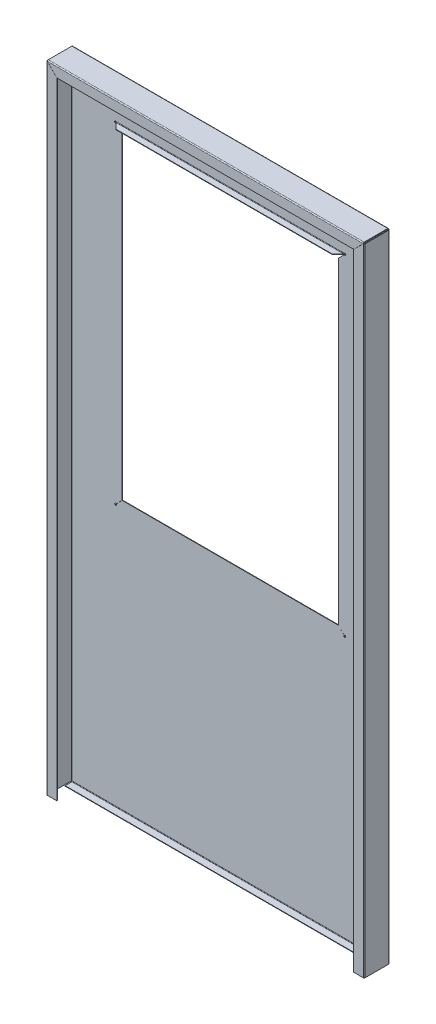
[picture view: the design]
ISO-10303-21;
HEADER;
FILE_DESCRIPTION(('STEP AP214'),'2;1');
FILE_NAME('part.step','',(''),(''),'','','');
FILE_SCHEMA(('AUTOMOTIVE_DESIGN { 1 0 10303 214 1 1 1 1 }'));
ENDSEC;
DATA;
#1=APPLICATION_CONTEXT('core data for automotive mechanical design processes');
#2=APPLICATION_PROTOCOL_DEFINITION('international standard','automotive_design',2000,#1);
#3=PRODUCT_CONTEXT('',#1,'mechanical');
#4=PRODUCT('Part','Part','',(#3));
#5=PRODUCT_RELATED_PRODUCT_CATEGORY('part','',(#4));
#6=PRODUCT_DEFINITION_FORMATION('','',#4);
#7=PRODUCT_DEFINITION_CONTEXT('part definition',#1,'design');
#8=PRODUCT_DEFINITION('design','',#6,#7);
#9=PRODUCT_DEFINITION_SHAPE('','',#8);
#10=(LENGTH_UNIT() NAMED_UNIT(*) SI_UNIT(.MILLI.,.METRE.));
#11=(NAMED_UNIT(*) PLANE_ANGLE_UNIT() SI_UNIT($,.RADIAN.));
#12=(NAMED_UNIT(*) SI_UNIT($,.STERADIAN.) SOLID_ANGLE_UNIT());
#13=UNCERTAINTY_MEASURE_WITH_UNIT(LENGTH_MEASURE(1.E-05),#10,'distance_accuracy_value','');
#14=(GEOMETRIC_REPRESENTATION_CONTEXT(3) GLOBAL_UNCERTAINTY_ASSIGNED_CONTEXT((#13)) GLOBAL_UNIT_ASSIGNED_CONTEXT((#10,
#11,#12)) REPRESENTATION_CONTEXT('',''));
#15=CARTESIAN_POINT('',(0.,0.,0.));
#16=DIRECTION('',(0.,0.,1.));
#17=DIRECTION('',(1.,0.,0.));
#18=AXIS2_PLACEMENT_3D('',#15,#16,#17);
#19=CARTESIAN_POINT('',(430.25,931.75,40.0010000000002));
#20=DIRECTION('',(0.,0.,-1.));
#21=DIRECTION('',(-1.,0.,0.));
#22=AXIS2_PLACEMENT_3D('',#19,#20,#21);
#23=CYLINDRICAL_SURFACE('',#22,1.50000000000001);
#24=CARTESIAN_POINT('',(430.25,931.75,0.750000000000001));
#25=DIRECTION('',(0.,0.,-1.));
#26=DIRECTION('',(-1.,0.,0.));
#27=AXIS2_PLACEMENT_3D('',#24,#25,#26);
#28=CIRCLE('',#27,1.50000000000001);
#29=CARTESIAN_POINT('',(429.32151366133,932.928097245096,0.750000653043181));
#30=VERTEX_POINT('',#29);
#31=CARTESIAN_POINT('',(429.225284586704,930.654573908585,0.750000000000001));
#32=VERTEX_POINT('',#31);
#33=EDGE_CURVE('E675',#30,#32,#28,.T.);
#34=ORIENTED_EDGE('',*,*,#33,.F.);
#35=CARTESIAN_POINT('',(429.32151366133,932.928097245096,6.5304318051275E-07));
#36=CARTESIAN_POINT('',(429.32151366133,932.928097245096,0.750000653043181));
#37=B_SPLINE_CURVE_WITH_KNOTS('',1,(#35,#36),.UNSPECIFIED.,.F.,.F.,(2,2),(0.,1.),.UNSPECIFIED.);
#38=CARTESIAN_POINT('',(429.32151366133,932.928097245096,0.));
#39=VERTEX_POINT('',#38);
#40=EDGE_CURVE('E13',#30,#39,#37,.F.);
#41=ORIENTED_EDGE('',*,*,#40,.T.);
#42=CARTESIAN_POINT('',(430.25,931.75,0.));
#43=DIRECTION('',(0.,0.,-1.));
#44=DIRECTION('',(-1.,0.,0.));
#45=AXIS2_PLACEMENT_3D('',#42,#43,#44);
#46=CIRCLE('',#45,1.50000000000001);
#47=CARTESIAN_POINT('',(429.225284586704,930.654573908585,0.));
#48=VERTEX_POINT('',#47);
#49=EDGE_CURVE('E711',#48,#39,#46,.F.);
#50=ORIENTED_EDGE('',*,*,#49,.F.);
#51=DIRECTION('',(0.,0.,-1.));
#52=VECTOR('',#51,1.);
#53=CARTESIAN_POINT('',(429.225284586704,930.654573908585,40.0010000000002));
#54=LINE('',#53,#52);
#55=EDGE_CURVE('E760',#32,#48,#54,.T.);
#56=ORIENTED_EDGE('',*,*,#55,.F.);
#57=EDGE_LOOP('',(#34,#41,#50,#56));
#58=FACE_BOUND('',#57,.T.);
#59=ADVANCED_FACE('F205',(#58),#23,.F.);
#60=CARTESIAN_POINT('',(0.,1000.,0.));
#61=DIRECTION('',(0.,0.,-1.));
#62=DIRECTION('',(-1.,0.,0.));
#63=AXIS2_PLACEMENT_3D('',#60,#61,#62);
#64=PLANE('',#63);
#65=DIRECTION('',(-1.,0.,0.));
#66=VECTOR('',#65,1.);
#67=CARTESIAN_POINT('',(0.,1000.,0.));
#68=LINE('',#67,#66);
#69=CARTESIAN_POINT('',(498.5,1000.,0.));
#70=VERTEX_POINT('',#69);
#71=CARTESIAN_POINT('',(1.5,1000.,0.));
#72=VERTEX_POINT('',#71);
#73=EDGE_CURVE('E1350',#70,#72,#68,.T.);
#74=ORIENTED_EDGE('',*,*,#73,.F.);
#75=DIRECTION('',(0.,1.,0.));
#76=VECTOR('',#75,1.);
#77=CARTESIAN_POINT('',(498.5,1000.,0.));
#78=LINE('',#77,#76);
#79=CARTESIAN_POINT('',(498.5,0.,0.));
#80=VERTEX_POINT('',#79);
#81=EDGE_CURVE('E1420',#70,#80,#78,.F.);
#82=ORIENTED_EDGE('',*,*,#81,.T.);
#83=DIRECTION('',(1.,0.,0.));
#84=VECTOR('',#83,1.);
#85=CARTESIAN_POINT('',(0.,0.,0.));
#86=LINE('',#85,#84);
#87=CARTESIAN_POINT('',(1.5,0.,0.));
#88=VERTEX_POINT('',#87);
#89=EDGE_CURVE('E1353',#88,#80,#86,.T.);
#90=ORIENTED_EDGE('',*,*,#89,.F.);
#91=DIRECTION('',(0.,-1.,0.));
#92=VECTOR('',#91,1.);
#93=CARTESIAN_POINT('',(1.5,0.,0.));
#94=LINE('',#93,#92);
#95=EDGE_CURVE('E1366',#88,#72,#94,.F.);
#96=ORIENTED_EDGE('',*,*,#95,.T.);
#97=EDGE_LOOP('',(#74,#82,#90,#96));
#98=FACE_BOUND('',#97,.T.);
#99=ORIENTED_EDGE('',*,*,#49,.T.);
#100=DIRECTION('',(-1.,0.,0.));
#101=VECTOR('',#100,1.);
#102=CARTESIAN_POINT('',(0.,932.928097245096,0.));
#103=LINE('',#102,#101);
#104=CARTESIAN_POINT('',(70.67848633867,932.928097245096,6.5304318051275E-07));
#105=VERTEX_POINT('',#104);
#106=EDGE_CURVE('E216',#39,#105,#103,.T.);
#107=ORIENTED_EDGE('',*,*,#106,.T.);
#108=CARTESIAN_POINT('',(69.7499999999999,931.75,0.));
#109=DIRECTION('',(0.,0.,-1.));
#110=DIRECTION('',(-1.,0.,0.));
#111=AXIS2_PLACEMENT_3D('',#108,#109,#110);
#112=CIRCLE('',#111,1.50000000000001);
#113=CARTESIAN_POINT('',(70.7747154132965,930.654573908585,0.));
#114=VERTEX_POINT('',#113);
#115=EDGE_CURVE('E706',#114,#105,#112,.T.);
#116=ORIENTED_EDGE('',*,*,#115,.F.);
#117=DIRECTION('',(-0.707106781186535,0.70710678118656,0.));
#118=VECTOR('',#117,1.);
#119=CARTESIAN_POINT('',(-58.6487222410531,1060.07801156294,0.));
#120=LINE('',#119,#118);
#121=CARTESIAN_POINT('',(79.9999999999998,921.429289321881,0.));
#122=VERTEX_POINT('',#121);
#123=EDGE_CURVE('E232',#122,#114,#120,.T.);
#124=ORIENTED_EDGE('',*,*,#123,.F.);
#125=DIRECTION('',(0.,-1.,0.));
#126=VECTOR('',#125,1.);
#127=CARTESIAN_POINT('',(79.9999999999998,500.,0.));
#128=LINE('',#127,#126);
#129=CARTESIAN_POINT('',(79.9999999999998,421.570710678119,0.));
#130=VERTEX_POINT('',#129);
#131=EDGE_CURVE('E735',#122,#130,#128,.T.);
#132=ORIENTED_EDGE('',*,*,#131,.T.);
#133=DIRECTION('',(-0.707106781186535,-0.70710678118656,0.));
#134=VECTOR('',#133,1.);
#135=CARTESIAN_POINT('',(-230.148722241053,111.421988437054,0.));
#136=LINE('',#135,#134);
#137=CARTESIAN_POINT('',(70.7747154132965,412.345426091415,0.));
#138=VERTEX_POINT('',#137);
#139=EDGE_CURVE('E732',#130,#138,#136,.T.);
#140=ORIENTED_EDGE('',*,*,#139,.T.);
#141=CARTESIAN_POINT('',(69.7499999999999,411.25,0.));
#142=DIRECTION('',(0.,0.,-1.));
#143=DIRECTION('',(-1.,0.,0.));
#144=AXIS2_PLACEMENT_3D('',#141,#142,#143);
#145=CIRCLE('',#144,1.50000000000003);
#146=CARTESIAN_POINT('',(70.8454260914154,412.274715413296,0.));
#147=VERTEX_POINT('',#146);
#148=EDGE_CURVE('E729',#138,#147,#145,.F.);
#149=ORIENTED_EDGE('',*,*,#148,.T.);
#150=DIRECTION('',(-0.707106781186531,-0.707106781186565,0.));
#151=VECTOR('',#150,1.);
#152=CARTESIAN_POINT('',(-230.07801156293,111.351277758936,0.));
#153=LINE('',#152,#151);
#154=CARTESIAN_POINT('',(80.0707106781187,421.5,0.));
#155=VERTEX_POINT('',#154);
#156=EDGE_CURVE('E726',#155,#147,#153,.T.);
#157=ORIENTED_EDGE('',*,*,#156,.F.);
#158=DIRECTION('',(-1.,0.,0.));
#159=VECTOR('',#158,1.);
#160=CARTESIAN_POINT('',(-618.726733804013,421.5,0.));
#161=LINE('',#160,#159);
#162=CARTESIAN_POINT('',(419.929289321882,421.5,0.));
#163=VERTEX_POINT('',#162);
#164=EDGE_CURVE('E723',#163,#155,#161,.T.);
#165=ORIENTED_EDGE('',*,*,#164,.F.);
#166=DIRECTION('',(0.707106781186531,-0.707106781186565,0.));
#167=VECTOR('',#166,1.);
#168=CARTESIAN_POINT('',(-138.648722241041,980.078011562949,0.));
#169=LINE('',#168,#167);
#170=CARTESIAN_POINT('',(429.154573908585,412.274715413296,0.));
#171=VERTEX_POINT('',#170);
#172=EDGE_CURVE('E720',#163,#171,#169,.T.);
#173=ORIENTED_EDGE('',*,*,#172,.T.);
#174=CARTESIAN_POINT('',(430.25,411.25,0.));
#175=DIRECTION('',(0.,0.,-1.));
#176=DIRECTION('',(-1.,0.,0.));
#177=AXIS2_PLACEMENT_3D('',#174,#175,#176);
#178=CIRCLE('',#177,1.50000000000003);
#179=CARTESIAN_POINT('',(429.225284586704,412.345426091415,0.));
#180=VERTEX_POINT('',#179);
#181=EDGE_CURVE('E717',#180,#171,#178,.T.);
#182=ORIENTED_EDGE('',*,*,#181,.F.);
#183=DIRECTION('',(0.707106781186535,-0.70710678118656,0.));
#184=VECTOR('',#183,1.);
#185=CARTESIAN_POINT('',(-138.578011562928,980.148722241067,0.));
#186=LINE('',#185,#184);
#187=CARTESIAN_POINT('',(420.,421.570710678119,0.));
#188=VERTEX_POINT('',#187);
#189=EDGE_CURVE('E714',#188,#180,#186,.T.);
#190=ORIENTED_EDGE('',*,*,#189,.F.);
#191=DIRECTION('',(0.,-1.,0.));
#192=VECTOR('',#191,1.);
#193=CARTESIAN_POINT('',(420.,500.,0.));
#194=LINE('',#193,#192);
#195=CARTESIAN_POINT('',(420.,921.429289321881,0.));
#196=VERTEX_POINT('',#195);
#197=EDGE_CURVE('E710',#196,#188,#194,.T.);
#198=ORIENTED_EDGE('',*,*,#197,.F.);
#199=DIRECTION('',(0.707106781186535,0.70710678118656,0.));
#200=VECTOR('',#199,1.);
#201=CARTESIAN_POINT('',(-310.078011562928,191.351277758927,0.));
#202=LINE('',#201,#200);
#203=EDGE_CURVE('E707',#196,#48,#202,.T.);
#204=ORIENTED_EDGE('',*,*,#203,.T.);
#205=EDGE_LOOP('',(#99,#107,#116,#124,#132,#140,#149,#157,#165,#173,#182,#190,#198,#204));
#206=FACE_BOUND('',#205,.T.);
#207=ADVANCED_FACE('F207',(#98,#206),#64,.T.);
#208=CARTESIAN_POINT('',(0.,1000.,0.75));
#209=DIRECTION('',(0.,0.,-1.));
#210=DIRECTION('',(-1.,0.,0.));
#211=AXIS2_PLACEMENT_3D('',#208,#209,#210);
#212=PLANE('',#211);
#213=DIRECTION('',(-1.,0.,0.));
#214=VECTOR('',#213,1.);
#215=CARTESIAN_POINT('',(0.,932.928097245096,0.75));
#216=LINE('',#215,#214);
#217=CARTESIAN_POINT('',(70.67848633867,932.928097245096,0.750000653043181));
#218=VERTEX_POINT('',#217);
#219=EDGE_CURVE('E1314',#30,#218,#216,.T.);
#220=ORIENTED_EDGE('',*,*,#219,.F.);
#221=ORIENTED_EDGE('',*,*,#33,.T.);
#222=DIRECTION('',(-0.707106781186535,-0.70710678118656,0.));
#223=VECTOR('',#222,1.);
#224=CARTESIAN_POINT('',(-310.078011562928,191.351277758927,0.750000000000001));
#225=LINE('',#224,#223);
#226=CARTESIAN_POINT('',(420.,921.429289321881,0.750000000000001));
#227=VERTEX_POINT('',#226);
#228=EDGE_CURVE('E666',#32,#227,#225,.T.);
#229=ORIENTED_EDGE('',*,*,#228,.T.);
#230=DIRECTION('',(0.,1.,0.));
#231=VECTOR('',#230,1.);
#232=CARTESIAN_POINT('',(420.,500.,0.750000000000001));
#233=LINE('',#232,#231);
#234=CARTESIAN_POINT('',(420.,421.570710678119,0.750000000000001));
#235=VERTEX_POINT('',#234);
#236=EDGE_CURVE('E674',#235,#227,#233,.T.);
#237=ORIENTED_EDGE('',*,*,#236,.F.);
#238=DIRECTION('',(-0.707106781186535,0.70710678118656,0.));
#239=VECTOR('',#238,1.);
#240=CARTESIAN_POINT('',(-138.578011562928,980.148722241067,0.750000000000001));
#241=LINE('',#240,#239);
#242=CARTESIAN_POINT('',(429.225284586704,412.345426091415,0.750000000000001));
#243=VERTEX_POINT('',#242);
#244=EDGE_CURVE('E678',#243,#235,#241,.T.);
#245=ORIENTED_EDGE('',*,*,#244,.F.);
#246=CARTESIAN_POINT('',(430.25,411.25,0.750000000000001));
#247=DIRECTION('',(0.,0.,-1.));
#248=DIRECTION('',(-1.,0.,0.));
#249=AXIS2_PLACEMENT_3D('',#246,#247,#248);
#250=CIRCLE('',#249,1.50000000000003);
#251=CARTESIAN_POINT('',(429.154573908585,412.274715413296,0.750000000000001));
#252=VERTEX_POINT('',#251);
#253=EDGE_CURVE('E681',#252,#243,#250,.F.);
#254=ORIENTED_EDGE('',*,*,#253,.F.);
#255=DIRECTION('',(-0.70710678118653,0.707106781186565,0.));
#256=VECTOR('',#255,1.);
#257=CARTESIAN_POINT('',(-138.648722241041,980.078011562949,0.750000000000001));
#258=LINE('',#257,#256);
#259=CARTESIAN_POINT('',(419.929289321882,421.5,0.750000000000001));
#260=VERTEX_POINT('',#259);
#261=EDGE_CURVE('E684',#252,#260,#258,.T.);
#262=ORIENTED_EDGE('',*,*,#261,.T.);
#263=DIRECTION('',(1.,0.,0.));
#264=VECTOR('',#263,1.);
#265=CARTESIAN_POINT('',(-618.726733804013,421.5,0.750000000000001));
#266=LINE('',#265,#264);
#267=CARTESIAN_POINT('',(80.0707106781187,421.5,0.750000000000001));
#268=VERTEX_POINT('',#267);
#269=EDGE_CURVE('E687',#268,#260,#266,.T.);
#270=ORIENTED_EDGE('',*,*,#269,.F.);
#271=DIRECTION('',(0.70710678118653,0.707106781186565,0.));
#272=VECTOR('',#271,1.);
#273=CARTESIAN_POINT('',(-230.07801156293,111.351277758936,0.750000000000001));
#274=LINE('',#273,#272);
#275=CARTESIAN_POINT('',(70.8454260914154,412.274715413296,0.750000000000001));
#276=VERTEX_POINT('',#275);
#277=EDGE_CURVE('E690',#276,#268,#274,.T.);
#278=ORIENTED_EDGE('',*,*,#277,.F.);
#279=CARTESIAN_POINT('',(69.7499999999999,411.25,0.750000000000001));
#280=DIRECTION('',(0.,0.,-1.));
#281=DIRECTION('',(-1.,0.,0.));
#282=AXIS2_PLACEMENT_3D('',#279,#280,#281);
#283=CIRCLE('',#282,1.50000000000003);
#284=CARTESIAN_POINT('',(70.7747154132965,412.345426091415,0.750000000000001));
#285=VERTEX_POINT('',#284);
#286=EDGE_CURVE('E693',#276,#285,#283,.T.);
#287=ORIENTED_EDGE('',*,*,#286,.T.);
#288=DIRECTION('',(0.707106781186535,0.70710678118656,0.));
#289=VECTOR('',#288,1.);
#290=CARTESIAN_POINT('',(-230.148722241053,111.421988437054,0.750000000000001));
#291=LINE('',#290,#289);
#292=CARTESIAN_POINT('',(79.9999999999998,421.570710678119,0.750000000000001));
#293=VERTEX_POINT('',#292);
#294=EDGE_CURVE('E696',#285,#293,#291,.T.);
#295=ORIENTED_EDGE('',*,*,#294,.T.);
#296=DIRECTION('',(0.,1.,0.));
#297=VECTOR('',#296,1.);
#298=CARTESIAN_POINT('',(79.9999999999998,500.,0.750000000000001));
#299=LINE('',#298,#297);
#300=CARTESIAN_POINT('',(79.9999999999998,921.429289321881,0.750000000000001));
#301=VERTEX_POINT('',#300);
#302=EDGE_CURVE('E699',#293,#301,#299,.T.);
#303=ORIENTED_EDGE('',*,*,#302,.T.);
#304=DIRECTION('',(0.707106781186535,-0.70710678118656,0.));
#305=VECTOR('',#304,1.);
#306=CARTESIAN_POINT('',(-58.6487222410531,1060.07801156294,0.750000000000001));
#307=LINE('',#306,#305);
#308=CARTESIAN_POINT('',(70.7747154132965,930.654573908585,0.750000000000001));
#309=VERTEX_POINT('',#308);
#310=EDGE_CURVE('E702',#309,#301,#307,.T.);
#311=ORIENTED_EDGE('',*,*,#310,.F.);
#312=CARTESIAN_POINT('',(69.7499999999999,931.75,0.750000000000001));
#313=DIRECTION('',(0.,0.,-1.));
#314=DIRECTION('',(-1.,0.,0.));
#315=AXIS2_PLACEMENT_3D('',#312,#313,#314);
#316=CIRCLE('',#315,1.50000000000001);
#317=EDGE_CURVE('E741',#218,#309,#316,.F.);
#318=ORIENTED_EDGE('',*,*,#317,.F.);
#319=EDGE_LOOP('',(#220,#221,#229,#237,#245,#254,#262,#270,#278,#287,#295,#303,#311,#318));
#320=FACE_BOUND('',#319,.T.);
#321=DIRECTION('',(0.,1.,0.));
#322=VECTOR('',#321,1.);
#323=CARTESIAN_POINT('',(498.5,1000.,0.750000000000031));
#324=LINE('',#323,#322);
#325=CARTESIAN_POINT('',(498.5,1000.,0.750000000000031));
#326=VERTEX_POINT('',#325);
#327=CARTESIAN_POINT('',(498.5,0.,0.750000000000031));
#328=VERTEX_POINT('',#327);
#329=EDGE_CURVE('E1428',#326,#328,#324,.F.);
#330=ORIENTED_EDGE('',*,*,#329,.F.);
#331=DIRECTION('',(-1.,0.,0.));
#332=VECTOR('',#331,1.);
#333=CARTESIAN_POINT('',(0.,1000.,0.75));
#334=LINE('',#333,#332);
#335=CARTESIAN_POINT('',(1.5,1000.,0.75));
#336=VERTEX_POINT('',#335);
#337=EDGE_CURVE('E1321',#326,#336,#334,.T.);
#338=ORIENTED_EDGE('',*,*,#337,.T.);
#339=DIRECTION('',(0.,-1.,0.));
#340=VECTOR('',#339,1.);
#341=CARTESIAN_POINT('',(1.5,0.,0.75));
#342=LINE('',#341,#340);
#343=CARTESIAN_POINT('',(1.5,0.,0.75));
#344=VERTEX_POINT('',#343);
#345=EDGE_CURVE('E1374',#344,#336,#342,.F.);
#346=ORIENTED_EDGE('',*,*,#345,.F.);
#347=DIRECTION('',(1.,0.,0.));
#348=VECTOR('',#347,1.);
#349=CARTESIAN_POINT('',(0.,0.,0.75));
#350=LINE('',#349,#348);
#351=EDGE_CURVE('E1347',#344,#328,#350,.T.);
#352=ORIENTED_EDGE('',*,*,#351,.T.);
#353=EDGE_LOOP('',(#330,#338,#346,#352));
#354=FACE_BOUND('',#353,.T.);
#355=ADVANCED_FACE('F1106',(#320,#354),#212,.F.);
#356=CARTESIAN_POINT('',(1.5,1000.,1.5));
#357=DIRECTION('',(0.,1.,0.));
#358=DIRECTION('',(0.,0.,1.));
#359=AXIS2_PLACEMENT_3D('',#356,#357,#358);
#360=PLANE('',#359);
#361=DIRECTION('',(1.,0.,0.));
#362=VECTOR('',#361,1.);
#363=CARTESIAN_POINT('',(0.,1000.,1.49999999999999));
#364=LINE('',#363,#362);
#365=CARTESIAN_POINT('',(0.749999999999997,1000.,1.5));
#366=VERTEX_POINT('',#365);
#367=CARTESIAN_POINT('',(0.,1000.,1.49999999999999));
#368=VERTEX_POINT('',#367);
#369=EDGE_CURVE('E1379',#366,#368,#364,.F.);
#370=ORIENTED_EDGE('',*,*,#369,.F.);
#371=CARTESIAN_POINT('',(1.5,1000.,1.5));
#372=DIRECTION('',(0.,-1.,0.));
#373=DIRECTION('',(0.,0.,-1.));
#374=AXIS2_PLACEMENT_3D('',#371,#372,#373);
#375=CIRCLE('',#374,0.75);
#376=EDGE_CURVE('E1367',#336,#366,#375,.F.);
#377=ORIENTED_EDGE('',*,*,#376,.F.);
#378=DIRECTION('',(0.,0.,-1.));
#379=VECTOR('',#378,1.);
#380=CARTESIAN_POINT('',(1.5,1000.,0.75));
#381=LINE('',#380,#379);
#382=EDGE_CURVE('E1356',#336,#72,#381,.T.);
#383=ORIENTED_EDGE('',*,*,#382,.T.);
#384=CARTESIAN_POINT('',(1.5,1000.,1.5));
#385=DIRECTION('',(0.,-1.,0.));
#386=DIRECTION('',(0.,0.,-1.));
#387=AXIS2_PLACEMENT_3D('',#384,#385,#386);
#388=CIRCLE('',#387,1.5);
#389=EDGE_CURVE('E1360',#72,#368,#388,.F.);
#390=ORIENTED_EDGE('',*,*,#389,.T.);
#391=EDGE_LOOP('',(#370,#377,#383,#390));
#392=FACE_BOUND('',#391,.T.);
#393=ADVANCED_FACE('F1103',(#392),#360,.T.);
#394=CARTESIAN_POINT('',(1.5,0.,1.5));
#395=DIRECTION('',(0.,1.,0.));
#396=DIRECTION('',(0.,0.,1.));
#397=AXIS2_PLACEMENT_3D('',#394,#395,#396);
#398=PLANE('',#397);
#399=CARTESIAN_POINT('',(1.5,0.,1.5));
#400=DIRECTION('',(0.,-1.,0.));
#401=DIRECTION('',(0.,0.,-1.));
#402=AXIS2_PLACEMENT_3D('',#399,#400,#401);
#403=CIRCLE('',#402,0.75);
#404=CARTESIAN_POINT('',(0.749999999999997,0.,1.5));
#405=VERTEX_POINT('',#404);
#406=EDGE_CURVE('E1371',#405,#344,#403,.T.);
#407=ORIENTED_EDGE('',*,*,#406,.F.);
#408=DIRECTION('',(1.,0.,0.));
#409=VECTOR('',#408,1.);
#410=CARTESIAN_POINT('',(0.749999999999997,0.,1.5));
#411=LINE('',#410,#409);
#412=CARTESIAN_POINT('',(0.,0.,1.49999999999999));
#413=VERTEX_POINT('',#412);
#414=EDGE_CURVE('E1385',#405,#413,#411,.F.);
#415=ORIENTED_EDGE('',*,*,#414,.T.);
#416=CARTESIAN_POINT('',(1.5,0.,1.5));
#417=DIRECTION('',(0.,-1.,0.));
#418=DIRECTION('',(0.,0.,-1.));
#419=AXIS2_PLACEMENT_3D('',#416,#417,#418);
#420=CIRCLE('',#419,1.5);
#421=EDGE_CURVE('E1363',#413,#88,#420,.T.);
#422=ORIENTED_EDGE('',*,*,#421,.T.);
#423=DIRECTION('',(0.,0.,-1.));
#424=VECTOR('',#423,1.);
#425=CARTESIAN_POINT('',(1.5,0.,0.75));
#426=LINE('',#425,#424);
#427=EDGE_CURVE('E1357',#344,#88,#426,.T.);
#428=ORIENTED_EDGE('',*,*,#427,.F.);
#429=EDGE_LOOP('',(#407,#415,#422,#428));
#430=FACE_BOUND('',#429,.T.);
#431=ADVANCED_FACE('F1099',(#430),#398,.F.);
#432=CARTESIAN_POINT('',(1.5,0.,1.5));
#433=DIRECTION('',(0.,-1.,0.));
#434=DIRECTION('',(-1.,0.,0.));
#435=AXIS2_PLACEMENT_3D('',#432,#433,#434);
#436=CYLINDRICAL_SURFACE('',#435,1.5);
#437=ORIENTED_EDGE('',*,*,#95,.F.);
#438=ORIENTED_EDGE('',*,*,#421,.F.);
#439=DIRECTION('',(0.,-1.,0.));
#440=VECTOR('',#439,1.);
#441=CARTESIAN_POINT('',(0.,1000.,1.49999999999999));
#442=LINE('',#441,#440);
#443=EDGE_CURVE('E1388',#413,#368,#442,.F.);
#444=ORIENTED_EDGE('',*,*,#443,.T.);
#445=ORIENTED_EDGE('',*,*,#389,.F.);
#446=EDGE_LOOP('',(#437,#438,#444,#445));
#447=FACE_BOUND('',#446,.T.);
#448=ADVANCED_FACE('F1097',(#447),#436,.T.);
#449=CARTESIAN_POINT('',(1.5,0.,1.5));
#450=DIRECTION('',(0.,-1.,0.));
#451=DIRECTION('',(-1.,0.,0.));
#452=AXIS2_PLACEMENT_3D('',#449,#450,#451);
#453=CYLINDRICAL_SURFACE('',#452,0.75);
#454=ORIENTED_EDGE('',*,*,#345,.T.);
#455=ORIENTED_EDGE('',*,*,#376,.T.);
#456=DIRECTION('',(0.,-1.,0.));
#457=VECTOR('',#456,1.);
#458=CARTESIAN_POINT('',(0.749999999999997,1000.,1.5));
#459=LINE('',#458,#457);
#460=EDGE_CURVE('E1382',#366,#405,#459,.T.);
#461=ORIENTED_EDGE('',*,*,#460,.T.);
#462=ORIENTED_EDGE('',*,*,#406,.T.);
#463=EDGE_LOOP('',(#454,#455,#461,#462));
#464=FACE_BOUND('',#463,.T.);
#465=ADVANCED_FACE('F1093',(#464),#453,.F.);
#466=CARTESIAN_POINT('',(0.,1000.,0.749999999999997));
#467=DIRECTION('',(0.,-1.,0.));
#468=DIRECTION('',(0.,0.,-1.));
#469=AXIS2_PLACEMENT_3D('',#466,#467,#468);
#470=PLANE('',#469);
#471=ORIENTED_EDGE('',*,*,#369,.T.);
#472=DIRECTION('',(0.,0.,-1.));
#473=VECTOR('',#472,1.);
#474=CARTESIAN_POINT('',(-1.31838984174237E-13,1000.,38.5));
#475=LINE('',#474,#473);
#476=CARTESIAN_POINT('',(-1.31838984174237E-13,1000.,38.5));
#477=VERTEX_POINT('',#476);
#478=EDGE_CURVE('E1398',#477,#368,#475,.T.);
#479=ORIENTED_EDGE('',*,*,#478,.F.);
#480=DIRECTION('',(1.,0.,0.));
#481=VECTOR('',#480,1.);
#482=CARTESIAN_POINT('',(-1.31803496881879E-13,1000.,38.5));
#483=LINE('',#482,#481);
#484=CARTESIAN_POINT('',(0.749999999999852,1000.,38.5));
#485=VERTEX_POINT('',#484);
#486=EDGE_CURVE('E1407',#477,#485,#483,.T.);
#487=ORIENTED_EDGE('',*,*,#486,.T.);
#488=DIRECTION('',(0.,0.,1.));
#489=VECTOR('',#488,1.);
#490=CARTESIAN_POINT('',(0.75,1000.,0.75));
#491=LINE('',#490,#489);
#492=EDGE_CURVE('E1390',#485,#366,#491,.F.);
#493=ORIENTED_EDGE('',*,*,#492,.T.);
#494=EDGE_LOOP('',(#471,#479,#487,#493));
#495=FACE_BOUND('',#494,.T.);
#496=ADVANCED_FACE('F1089',(#495),#470,.F.);
#497=CARTESIAN_POINT('',(-1.31838984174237E-13,0.,38.5));
#498=DIRECTION('',(0.,1.,0.));
#499=DIRECTION('',(0.,0.,1.));
#500=AXIS2_PLACEMENT_3D('',#497,#498,#499);
#501=PLANE('',#500);
#502=ORIENTED_EDGE('',*,*,#414,.F.);
#503=DIRECTION('',(0.,0.,-1.));
#504=VECTOR('',#503,1.);
#505=CARTESIAN_POINT('',(0.749999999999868,0.,38.5));
#506=LINE('',#505,#504);
#507=CARTESIAN_POINT('',(0.749999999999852,0.,38.5));
#508=VERTEX_POINT('',#507);
#509=EDGE_CURVE('E1393',#405,#508,#506,.F.);
#510=ORIENTED_EDGE('',*,*,#509,.T.);
#511=DIRECTION('',(1.,0.,0.));
#512=VECTOR('',#511,1.);
#513=CARTESIAN_POINT('',(-1.31838984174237E-13,0.,38.5));
#514=LINE('',#513,#512);
#515=CARTESIAN_POINT('',(-1.47668335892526E-13,0.,38.5));
#516=VERTEX_POINT('',#515);
#517=EDGE_CURVE('E1375',#516,#508,#514,.T.);
#518=ORIENTED_EDGE('',*,*,#517,.F.);
#519=DIRECTION('',(0.,0.,1.));
#520=VECTOR('',#519,1.);
#521=CARTESIAN_POINT('',(-1.31838984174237E-13,0.,38.5));
#522=LINE('',#521,#520);
#523=EDGE_CURVE('E1401',#413,#516,#522,.T.);
#524=ORIENTED_EDGE('',*,*,#523,.F.);
#525=EDGE_LOOP('',(#502,#510,#518,#524));
#526=FACE_BOUND('',#525,.T.);
#527=ADVANCED_FACE('F1085',(#526),#501,.F.);
#528=CARTESIAN_POINT('',(-1.31838984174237E-13,1000.,38.5));
#529=DIRECTION('',(1.,0.,0.));
#530=DIRECTION('',(0.,0.,-1.));
#531=AXIS2_PLACEMENT_3D('',#528,#529,#530);
#532=PLANE('',#531);
#533=ORIENTED_EDGE('',*,*,#443,.F.);
#534=ORIENTED_EDGE('',*,*,#523,.T.);
#535=DIRECTION('',(0.,1.,0.));
#536=VECTOR('',#535,1.);
#537=CARTESIAN_POINT('',(-1.31838984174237E-13,1000.,38.5));
#538=LINE('',#537,#536);
#539=EDGE_CURVE('E1404',#516,#477,#538,.T.);
#540=ORIENTED_EDGE('',*,*,#539,.T.);
#541=ORIENTED_EDGE('',*,*,#478,.T.);
#542=EDGE_LOOP('',(#533,#534,#540,#541));
#543=FACE_BOUND('',#542,.T.);
#544=ADVANCED_FACE('F1081',(#543),#532,.F.);
#545=CARTESIAN_POINT('',(0.749999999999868,1000.,38.5));
#546=DIRECTION('',(1.,0.,0.));
#547=DIRECTION('',(0.,0.,-1.));
#548=AXIS2_PLACEMENT_3D('',#545,#546,#547);
#549=PLANE('',#548);
#550=ORIENTED_EDGE('',*,*,#509,.F.);
#551=ORIENTED_EDGE('',*,*,#460,.F.);
#552=ORIENTED_EDGE('',*,*,#492,.F.);
#553=DIRECTION('',(0.,-1.,0.));
#554=VECTOR('',#553,1.);
#555=CARTESIAN_POINT('',(0.749999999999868,1000.,38.5));
#556=LINE('',#555,#554);
#557=EDGE_CURVE('E1396',#508,#485,#556,.F.);
#558=ORIENTED_EDGE('',*,*,#557,.F.);
#559=EDGE_LOOP('',(#550,#551,#552,#558));
#560=FACE_BOUND('',#559,.T.);
#561=ADVANCED_FACE('F1074',(#560),#549,.T.);
#562=CARTESIAN_POINT('',(498.5,0.,1.5));
#563=DIRECTION('',(0.,-1.,0.));
#564=DIRECTION('',(0.,0.,-1.));
#565=AXIS2_PLACEMENT_3D('',#562,#563,#564);
#566=PLANE('',#565);
#567=DIRECTION('',(-1.,0.,0.));
#568=VECTOR('',#567,1.);
#569=CARTESIAN_POINT('',(500.,0.,1.5));
#570=LINE('',#569,#568);
#571=CARTESIAN_POINT('',(499.25,0.,1.5));
#572=VERTEX_POINT('',#571);
#573=CARTESIAN_POINT('',(500.,0.,1.5));
#574=VERTEX_POINT('',#573);
#575=EDGE_CURVE('E1433',#572,#574,#570,.F.);
#576=ORIENTED_EDGE('',*,*,#575,.F.);
#577=CARTESIAN_POINT('',(498.5,0.,1.5));
#578=DIRECTION('',(0.,1.,0.));
#579=DIRECTION('',(0.,0.,1.));
#580=AXIS2_PLACEMENT_3D('',#577,#578,#579);
#581=CIRCLE('',#580,0.749999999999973);
#582=EDGE_CURVE('E1421',#328,#572,#581,.F.);
#583=ORIENTED_EDGE('',*,*,#582,.F.);
#584=DIRECTION('',(0.,0.,-1.));
#585=VECTOR('',#584,1.);
#586=CARTESIAN_POINT('',(498.5,0.,0.750000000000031));
#587=LINE('',#586,#585);
#588=EDGE_CURVE('E1383',#328,#80,#587,.T.);
#589=ORIENTED_EDGE('',*,*,#588,.T.);
#590=CARTESIAN_POINT('',(498.5,0.,1.5));
#591=DIRECTION('',(0.,1.,0.));
#592=DIRECTION('',(0.,0.,1.));
#593=AXIS2_PLACEMENT_3D('',#590,#591,#592);
#594=CIRCLE('',#593,1.49999999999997);
#595=EDGE_CURVE('E1414',#80,#574,#594,.F.);
#596=ORIENTED_EDGE('',*,*,#595,.T.);
#597=EDGE_LOOP('',(#576,#583,#589,#596));
#598=FACE_BOUND('',#597,.T.);
#599=ADVANCED_FACE('F1071',(#598),#566,.T.);
#600=CARTESIAN_POINT('',(498.5,1000.,1.5));
#601=DIRECTION('',(0.,-1.,0.));
#602=DIRECTION('',(0.,0.,-1.));
#603=AXIS2_PLACEMENT_3D('',#600,#601,#602);
#604=PLANE('',#603);
#605=CARTESIAN_POINT('',(498.5,1000.,1.5));
#606=DIRECTION('',(0.,1.,0.));
#607=DIRECTION('',(0.,0.,1.));
#608=AXIS2_PLACEMENT_3D('',#605,#606,#607);
#609=CIRCLE('',#608,0.749999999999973);
#610=CARTESIAN_POINT('',(499.25,1000.,1.5));
#611=VERTEX_POINT('',#610);
#612=EDGE_CURVE('E1425',#611,#326,#609,.T.);
#613=ORIENTED_EDGE('',*,*,#612,.F.);
#614=DIRECTION('',(-1.,0.,0.));
#615=VECTOR('',#614,1.);
#616=CARTESIAN_POINT('',(499.25,1000.,1.5));
#617=LINE('',#616,#615);
#618=CARTESIAN_POINT('',(500.,1000.,1.5));
#619=VERTEX_POINT('',#618);
#620=EDGE_CURVE('E1439',#611,#619,#617,.F.);
#621=ORIENTED_EDGE('',*,*,#620,.T.);
#622=CARTESIAN_POINT('',(498.5,1000.,1.5));
#623=DIRECTION('',(0.,1.,0.));
#624=DIRECTION('',(0.,0.,1.));
#625=AXIS2_PLACEMENT_3D('',#622,#623,#624);
#626=CIRCLE('',#625,1.49999999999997);
#627=EDGE_CURVE('E1417',#619,#70,#626,.T.);
#628=ORIENTED_EDGE('',*,*,#627,.T.);
#629=DIRECTION('',(0.,0.,-1.));
#630=VECTOR('',#629,1.);
#631=CARTESIAN_POINT('',(498.5,1000.,0.750000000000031));
#632=LINE('',#631,#630);
#633=EDGE_CURVE('E1411',#326,#70,#632,.T.);
#634=ORIENTED_EDGE('',*,*,#633,.F.);
#635=EDGE_LOOP('',(#613,#621,#628,#634));
#636=FACE_BOUND('',#635,.T.);
#637=ADVANCED_FACE('F1067',(#636),#604,.F.);
#638=CARTESIAN_POINT('',(498.5,1000.,1.5));
#639=DIRECTION('',(0.,1.,0.));
#640=DIRECTION('',(1.,0.,0.));
#641=AXIS2_PLACEMENT_3D('',#638,#639,#640);
#642=CYLINDRICAL_SURFACE('',#641,1.49999999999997);
#643=ORIENTED_EDGE('',*,*,#81,.F.);
#644=ORIENTED_EDGE('',*,*,#627,.F.);
#645=DIRECTION('',(0.,1.,0.));
#646=VECTOR('',#645,1.);
#647=CARTESIAN_POINT('',(500.,0.,1.5));
#648=LINE('',#647,#646);
#649=EDGE_CURVE('E1442',#619,#574,#648,.F.);
#650=ORIENTED_EDGE('',*,*,#649,.T.);
#651=ORIENTED_EDGE('',*,*,#595,.F.);
#652=EDGE_LOOP('',(#643,#644,#650,#651));
#653=FACE_BOUND('',#652,.T.);
#654=ADVANCED_FACE('F1065',(#653),#642,.T.);
#655=CARTESIAN_POINT('',(498.5,1000.,1.5));
#656=DIRECTION('',(0.,1.,0.));
#657=DIRECTION('',(1.,0.,0.));
#658=AXIS2_PLACEMENT_3D('',#655,#656,#657);
#659=CYLINDRICAL_SURFACE('',#658,0.749999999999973);
#660=ORIENTED_EDGE('',*,*,#329,.T.);
#661=ORIENTED_EDGE('',*,*,#582,.T.);
#662=DIRECTION('',(0.,1.,0.));
#663=VECTOR('',#662,1.);
#664=CARTESIAN_POINT('',(499.25,0.,1.5));
#665=LINE('',#664,#663);
#666=EDGE_CURVE('E1436',#572,#611,#665,.T.);
#667=ORIENTED_EDGE('',*,*,#666,.T.);
#668=ORIENTED_EDGE('',*,*,#612,.T.);
#669=EDGE_LOOP('',(#660,#661,#667,#668));
#670=FACE_BOUND('',#669,.T.);
#671=ADVANCED_FACE('F1061',(#670),#659,.F.);
#672=CARTESIAN_POINT('',(500.,0.,0.749999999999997));
#673=DIRECTION('',(0.,1.,0.));
#674=DIRECTION('',(0.,0.,1.));
#675=AXIS2_PLACEMENT_3D('',#672,#673,#674);
#676=PLANE('',#675);
#677=ORIENTED_EDGE('',*,*,#575,.T.);
#678=DIRECTION('',(0.,0.,-1.));
#679=VECTOR('',#678,1.);
#680=CARTESIAN_POINT('',(500.,0.,38.5));
#681=LINE('',#680,#679);
#682=CARTESIAN_POINT('',(500.,0.,38.5));
#683=VERTEX_POINT('',#682);
#684=EDGE_CURVE('E1452',#683,#574,#681,.T.);
#685=ORIENTED_EDGE('',*,*,#684,.F.);
#686=DIRECTION('',(-1.,0.,0.));
#687=VECTOR('',#686,1.);
#688=CARTESIAN_POINT('',(500.,0.,38.5));
#689=LINE('',#688,#687);
#690=CARTESIAN_POINT('',(499.25,0.,38.5));
#691=VERTEX_POINT('',#690);
#692=EDGE_CURVE('E1461',#683,#691,#689,.T.);
#693=ORIENTED_EDGE('',*,*,#692,.T.);
#694=DIRECTION('',(0.,0.,1.));
#695=VECTOR('',#694,1.);
#696=CARTESIAN_POINT('',(499.25,0.,0.75));
#697=LINE('',#696,#695);
#698=EDGE_CURVE('E1444',#691,#572,#697,.F.);
#699=ORIENTED_EDGE('',*,*,#698,.T.);
#700=EDGE_LOOP('',(#677,#685,#693,#699));
#701=FACE_BOUND('',#700,.T.);
#702=ADVANCED_FACE('F1057',(#701),#676,.F.);
#703=CARTESIAN_POINT('',(500.,1000.,38.5));
#704=DIRECTION('',(0.,-1.,0.));
#705=DIRECTION('',(0.,0.,-1.));
#706=AXIS2_PLACEMENT_3D('',#703,#704,#705);
#707=PLANE('',#706);
#708=ORIENTED_EDGE('',*,*,#620,.F.);
#709=DIRECTION('',(0.,0.,-1.));
#710=VECTOR('',#709,1.);
#711=CARTESIAN_POINT('',(499.25,1000.,38.5));
#712=LINE('',#711,#710);
#713=CARTESIAN_POINT('',(499.25,1000.,38.5));
#714=VERTEX_POINT('',#713);
#715=EDGE_CURVE('E1447',#611,#714,#712,.F.);
#716=ORIENTED_EDGE('',*,*,#715,.T.);
#717=DIRECTION('',(-1.,0.,0.));
#718=VECTOR('',#717,1.);
#719=CARTESIAN_POINT('',(500.,1000.,38.5));
#720=LINE('',#719,#718);
#721=CARTESIAN_POINT('',(500.,1000.,38.5));
#722=VERTEX_POINT('',#721);
#723=EDGE_CURVE('E1429',#722,#714,#720,.T.);
#724=ORIENTED_EDGE('',*,*,#723,.F.);
#725=DIRECTION('',(0.,0.,1.));
#726=VECTOR('',#725,1.);
#727=CARTESIAN_POINT('',(500.,1000.,38.5));
#728=LINE('',#727,#726);
#729=EDGE_CURVE('E1455',#619,#722,#728,.T.);
#730=ORIENTED_EDGE('',*,*,#729,.F.);
#731=EDGE_LOOP('',(#708,#716,#724,#730));
#732=FACE_BOUND('',#731,.T.);
#733=ADVANCED_FACE('F1053',(#732),#707,.F.);
#734=CARTESIAN_POINT('',(500.,0.,38.5));
#735=DIRECTION('',(-1.,0.,0.));
#736=DIRECTION('',(0.,0.,1.));
#737=AXIS2_PLACEMENT_3D('',#734,#735,#736);
#738=PLANE('',#737);
#739=ORIENTED_EDGE('',*,*,#649,.F.);
#740=ORIENTED_EDGE('',*,*,#729,.T.);
#741=DIRECTION('',(0.,-1.,0.));
#742=VECTOR('',#741,1.);
#743=CARTESIAN_POINT('',(500.,0.,38.5));
#744=LINE('',#743,#742);
#745=EDGE_CURVE('E1458',#722,#683,#744,.T.);
#746=ORIENTED_EDGE('',*,*,#745,.T.);
#747=ORIENTED_EDGE('',*,*,#684,.T.);
#748=EDGE_LOOP('',(#739,#740,#746,#747));
#749=FACE_BOUND('',#748,.T.);
#750=ADVANCED_FACE('F1049',(#749),#738,.F.);
#751=CARTESIAN_POINT('',(499.25,0.,38.5));
#752=DIRECTION('',(-1.,0.,0.));
#753=DIRECTION('',(0.,0.,1.));
#754=AXIS2_PLACEMENT_3D('',#751,#752,#753);
#755=PLANE('',#754);
#756=ORIENTED_EDGE('',*,*,#715,.F.);
#757=ORIENTED_EDGE('',*,*,#666,.F.);
#758=ORIENTED_EDGE('',*,*,#698,.F.);
#759=DIRECTION('',(0.,1.,0.));
#760=VECTOR('',#759,1.);
#761=CARTESIAN_POINT('',(499.25,0.,38.5));
#762=LINE('',#761,#760);
#763=EDGE_CURVE('E1450',#714,#691,#762,.F.);
#764=ORIENTED_EDGE('',*,*,#763,.F.);
#765=EDGE_LOOP('',(#756,#757,#758,#764));
#766=FACE_BOUND('',#765,.T.);
#767=ADVANCED_FACE('F1042',(#766),#755,.T.);
#768=CARTESIAN_POINT('',(498.5,1000.,1.50000000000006));
#769=DIRECTION('',(1.,0.,0.));
#770=DIRECTION('',(0.,0.,-1.));
#771=AXIS2_PLACEMENT_3D('',#768,#769,#770);
#772=PLANE('',#771);
#773=DIRECTION('',(0.,1.,0.));
#774=VECTOR('',#773,1.);
#775=CARTESIAN_POINT('',(498.5,1001.5,1.50000000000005));
#776=LINE('',#775,#774);
#777=CARTESIAN_POINT('',(498.5,1000.75,1.50000000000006));
#778=VERTEX_POINT('',#777);
#779=CARTESIAN_POINT('',(498.5,1001.5,1.50000000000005));
#780=VERTEX_POINT('',#779);
#781=EDGE_CURVE('E1477',#778,#780,#776,.T.);
#782=ORIENTED_EDGE('',*,*,#781,.F.);
#783=CARTESIAN_POINT('',(498.5,1000.,1.50000000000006));
#784=DIRECTION('',(-1.,0.,0.));
#785=DIRECTION('',(0.,0.,1.));
#786=AXIS2_PLACEMENT_3D('',#783,#784,#785);
#787=CIRCLE('',#786,0.750000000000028);
#788=EDGE_CURVE('E1468',#326,#778,#787,.F.);
#789=ORIENTED_EDGE('',*,*,#788,.F.);
#790=ORIENTED_EDGE('',*,*,#633,.T.);
#791=CARTESIAN_POINT('',(498.5,1000.,1.50000000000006));
#792=DIRECTION('',(-1.,0.,0.));
#793=DIRECTION('',(0.,0.,1.));
#794=AXIS2_PLACEMENT_3D('',#791,#792,#793);
#795=CIRCLE('',#794,1.50000000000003);
#796=EDGE_CURVE('E1437',#70,#780,#795,.F.);
#797=ORIENTED_EDGE('',*,*,#796,.T.);
#798=EDGE_LOOP('',(#782,#789,#790,#797));
#799=FACE_BOUND('',#798,.T.);
#800=ADVANCED_FACE('F1039',(#799),#772,.T.);
#801=CARTESIAN_POINT('',(1.5,1000.,1.50000000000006));
#802=DIRECTION('',(1.,0.,0.));
#803=DIRECTION('',(0.,0.,-1.));
#804=AXIS2_PLACEMENT_3D('',#801,#802,#803);
#805=PLANE('',#804);
#806=CARTESIAN_POINT('',(1.5,1000.,1.50000000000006));
#807=DIRECTION('',(-1.,0.,0.));
#808=DIRECTION('',(0.,0.,1.));
#809=AXIS2_PLACEMENT_3D('',#806,#807,#808);
#810=CIRCLE('',#809,0.750000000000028);
#811=CARTESIAN_POINT('',(1.5,1000.75,1.50000000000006));
#812=VERTEX_POINT('',#811);
#813=EDGE_CURVE('E1471',#812,#336,#810,.T.);
#814=ORIENTED_EDGE('',*,*,#813,.F.);
#815=DIRECTION('',(0.,1.,0.));
#816=VECTOR('',#815,1.);
#817=CARTESIAN_POINT('',(1.5,1000.75,1.50000000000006));
#818=LINE('',#817,#816);
#819=CARTESIAN_POINT('',(1.5,1001.5,1.50000000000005));
#820=VERTEX_POINT('',#819);
#821=EDGE_CURVE('E1483',#812,#820,#818,.T.);
#822=ORIENTED_EDGE('',*,*,#821,.T.);
#823=CARTESIAN_POINT('',(1.5,1000.,1.50000000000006));
#824=DIRECTION('',(-1.,0.,0.));
#825=DIRECTION('',(0.,0.,1.));
#826=AXIS2_PLACEMENT_3D('',#823,#824,#825);
#827=CIRCLE('',#826,1.50000000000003);
#828=EDGE_CURVE('E1465',#820,#72,#827,.T.);
#829=ORIENTED_EDGE('',*,*,#828,.T.);
#830=ORIENTED_EDGE('',*,*,#382,.F.);
#831=EDGE_LOOP('',(#814,#822,#829,#830));
#832=FACE_BOUND('',#831,.T.);
#833=ADVANCED_FACE('F1035',(#832),#805,.F.);
#834=CARTESIAN_POINT('',(1.49999999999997,1000.,1.50000000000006));
#835=DIRECTION('',(-1.,0.,0.));
#836=DIRECTION('',(0.,1.,0.));
#837=AXIS2_PLACEMENT_3D('',#834,#835,#836);
#838=CYLINDRICAL_SURFACE('',#837,1.50000000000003);
#839=ORIENTED_EDGE('',*,*,#73,.T.);
#840=ORIENTED_EDGE('',*,*,#828,.F.);
#841=DIRECTION('',(-1.,0.,0.));
#842=VECTOR('',#841,1.);
#843=CARTESIAN_POINT('',(1.5,1001.5,1.50000000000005));
#844=LINE('',#843,#842);
#845=EDGE_CURVE('E1486',#780,#820,#844,.T.);
#846=ORIENTED_EDGE('',*,*,#845,.F.);
#847=ORIENTED_EDGE('',*,*,#796,.F.);
#848=EDGE_LOOP('',(#839,#840,#846,#847));
#849=FACE_BOUND('',#848,.T.);
#850=ADVANCED_FACE('F1033',(#849),#838,.T.);
#851=CARTESIAN_POINT('',(1.49999999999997,1000.,1.50000000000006));
#852=DIRECTION('',(-1.,0.,0.));
#853=DIRECTION('',(0.,1.,0.));
#854=AXIS2_PLACEMENT_3D('',#851,#852,#853);
#855=CYLINDRICAL_SURFACE('',#854,0.750000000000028);
#856=ORIENTED_EDGE('',*,*,#337,.F.);
#857=ORIENTED_EDGE('',*,*,#788,.T.);
#858=DIRECTION('',(1.,0.,0.));
#859=VECTOR('',#858,1.);
#860=CARTESIAN_POINT('',(498.5,1000.75,1.50000000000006));
#861=LINE('',#860,#859);
#862=EDGE_CURVE('E1480',#778,#812,#861,.F.);
#863=ORIENTED_EDGE('',*,*,#862,.T.);
#864=ORIENTED_EDGE('',*,*,#813,.T.);
#865=EDGE_LOOP('',(#856,#857,#863,#864));
#866=FACE_BOUND('',#865,.T.);
#867=ADVANCED_FACE('F1026',(#866),#855,.F.);
#868=CARTESIAN_POINT('',(1.5,1001.5,0.749999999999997));
#869=DIRECTION('',(-1.,0.,0.));
#870=DIRECTION('',(0.,0.,1.));
#871=AXIS2_PLACEMENT_3D('',#868,#869,#870);
#872=PLANE('',#871);
#873=DIRECTION('',(0.,0.,-1.));
#874=VECTOR('',#873,1.);
#875=CARTESIAN_POINT('',(1.5,1001.5,0.749999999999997));
#876=LINE('',#875,#874);
#877=CARTESIAN_POINT('',(1.49999999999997,1001.5,38.5));
#878=VERTEX_POINT('',#877);
#879=EDGE_CURVE('E1501',#878,#820,#876,.T.);
#880=ORIENTED_EDGE('',*,*,#879,.T.);
#881=ORIENTED_EDGE('',*,*,#821,.F.);
#882=DIRECTION('',(0.,0.,1.));
#883=VECTOR('',#882,1.);
#884=CARTESIAN_POINT('',(1.5,1000.75,0.75));
#885=LINE('',#884,#883);
#886=CARTESIAN_POINT('',(1.5,1000.75,38.5));
#887=VERTEX_POINT('',#886);
#888=EDGE_CURVE('E1493',#887,#812,#885,.F.);
#889=ORIENTED_EDGE('',*,*,#888,.F.);
#890=DIRECTION('',(0.,-1.,0.));
#891=VECTOR('',#890,1.);
#892=CARTESIAN_POINT('',(1.5,1001.5,38.5));
#893=LINE('',#892,#891);
#894=EDGE_CURVE('E1474',#878,#887,#893,.T.);
#895=ORIENTED_EDGE('',*,*,#894,.F.);
#896=EDGE_LOOP('',(#880,#881,#889,#895));
#897=FACE_BOUND('',#896,.T.);
#898=ADVANCED_FACE('F1023',(#897),#872,.T.);
#899=CARTESIAN_POINT('',(498.5,1001.5,38.5));
#900=DIRECTION('',(1.,0.,0.));
#901=DIRECTION('',(0.,1.,0.));
#902=AXIS2_PLACEMENT_3D('',#899,#900,#901);
#903=PLANE('',#902);
#904=DIRECTION('',(0.,0.,-1.));
#905=VECTOR('',#904,1.);
#906=CARTESIAN_POINT('',(498.5,1000.75,0.75));
#907=LINE('',#906,#905);
#908=CARTESIAN_POINT('',(498.5,1000.75,38.5));
#909=VERTEX_POINT('',#908);
#910=EDGE_CURVE('E1489',#778,#909,#907,.F.);
#911=ORIENTED_EDGE('',*,*,#910,.F.);
#912=ORIENTED_EDGE('',*,*,#781,.T.);
#913=DIRECTION('',(0.,0.,1.));
#914=VECTOR('',#913,1.);
#915=CARTESIAN_POINT('',(498.5,1001.5,38.5));
#916=LINE('',#915,#914);
#917=CARTESIAN_POINT('',(498.5,1001.5,38.5));
#918=VERTEX_POINT('',#917);
#919=EDGE_CURVE('E1496',#780,#918,#916,.T.);
#920=ORIENTED_EDGE('',*,*,#919,.T.);
#921=DIRECTION('',(0.,-1.,0.));
#922=VECTOR('',#921,1.);
#923=CARTESIAN_POINT('',(498.5,1001.5,38.5));
#924=LINE('',#923,#922);
#925=EDGE_CURVE('E1504',#918,#909,#924,.T.);
#926=ORIENTED_EDGE('',*,*,#925,.T.);
#927=EDGE_LOOP('',(#911,#912,#920,#926));
#928=FACE_BOUND('',#927,.T.);
#929=ADVANCED_FACE('F1021',(#928),#903,.T.);
#930=CARTESIAN_POINT('',(1.5,1001.5,0.749999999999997));
#931=DIRECTION('',(0.,1.,0.));
#932=DIRECTION('',(0.,0.,1.));
#933=AXIS2_PLACEMENT_3D('',#930,#931,#932);
#934=PLANE('',#933);
#935=ORIENTED_EDGE('',*,*,#919,.F.);
#936=ORIENTED_EDGE('',*,*,#845,.T.);
#937=ORIENTED_EDGE('',*,*,#879,.F.);
#938=DIRECTION('',(-1.,0.,0.));
#939=VECTOR('',#938,1.);
#940=CARTESIAN_POINT('',(1.5,1001.5,38.5));
#941=LINE('',#940,#939);
#942=EDGE_CURVE('E1498',#918,#878,#941,.T.);
#943=ORIENTED_EDGE('',*,*,#942,.F.);
#944=EDGE_LOOP('',(#935,#936,#937,#943));
#945=FACE_BOUND('',#944,.T.);
#946=ADVANCED_FACE('F1017',(#945),#934,.T.);
#947=CARTESIAN_POINT('',(1.5,1000.75,0.75));
#948=DIRECTION('',(0.,1.,0.));
#949=DIRECTION('',(0.,0.,1.));
#950=AXIS2_PLACEMENT_3D('',#947,#948,#949);
#951=PLANE('',#950);
#952=ORIENTED_EDGE('',*,*,#862,.F.);
#953=ORIENTED_EDGE('',*,*,#910,.T.);
#954=DIRECTION('',(1.,0.,0.));
#955=VECTOR('',#954,1.);
#956=CARTESIAN_POINT('',(1.5,1000.75,38.5));
#957=LINE('',#956,#955);
#958=EDGE_CURVE('E1491',#909,#887,#957,.F.);
#959=ORIENTED_EDGE('',*,*,#958,.T.);
#960=ORIENTED_EDGE('',*,*,#888,.T.);
#961=EDGE_LOOP('',(#952,#953,#959,#960));
#962=FACE_BOUND('',#961,.T.);
#963=ADVANCED_FACE('F1010',(#962),#951,.F.);
#964=CARTESIAN_POINT('',(1.49999999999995,0.,1.50000000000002));
#965=DIRECTION('',(-1.,0.,0.));
#966=DIRECTION('',(0.,0.,1.));
#967=AXIS2_PLACEMENT_3D('',#964,#965,#966);
#968=PLANE('',#967);
#969=DIRECTION('',(0.,1.,0.));
#970=VECTOR('',#969,1.);
#971=CARTESIAN_POINT('',(1.5,-1.5,1.49999999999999));
#972=LINE('',#971,#970);
#973=CARTESIAN_POINT('',(1.49999999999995,-0.75,1.50000000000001));
#974=VERTEX_POINT('',#973);
#975=CARTESIAN_POINT('',(1.49999999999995,-1.5,1.50000000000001));
#976=VERTEX_POINT('',#975);
#977=EDGE_CURVE('E1521',#974,#976,#972,.F.);
#978=ORIENTED_EDGE('',*,*,#977,.F.);
#979=CARTESIAN_POINT('',(1.49999999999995,0.,1.50000000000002));
#980=DIRECTION('',(1.,0.,0.));
#981=DIRECTION('',(0.,0.,-1.));
#982=AXIS2_PLACEMENT_3D('',#979,#980,#981);
#983=CIRCLE('',#982,0.75);
#984=EDGE_CURVE('E1512',#344,#974,#983,.F.);
#985=ORIENTED_EDGE('',*,*,#984,.F.);
#986=ORIENTED_EDGE('',*,*,#427,.T.);
#987=CARTESIAN_POINT('',(1.49999999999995,0.,1.50000000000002));
#988=DIRECTION('',(1.,0.,0.));
#989=DIRECTION('',(0.,0.,-1.));
#990=AXIS2_PLACEMENT_3D('',#987,#988,#989);
#991=CIRCLE('',#990,1.5);
#992=EDGE_CURVE('E1481',#88,#976,#991,.F.);
#993=ORIENTED_EDGE('',*,*,#992,.T.);
#994=EDGE_LOOP('',(#978,#985,#986,#993));
#995=FACE_BOUND('',#994,.T.);
#996=ADVANCED_FACE('F1007',(#995),#968,.T.);
#997=CARTESIAN_POINT('',(498.5,0.,1.50000000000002));
#998=DIRECTION('',(-1.,0.,0.));
#999=DIRECTION('',(0.,0.,1.));
#1000=AXIS2_PLACEMENT_3D('',#997,#998,#999);
#1001=PLANE('',#1000);
#1002=CARTESIAN_POINT('',(498.5,0.,1.50000000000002));
#1003=DIRECTION('',(1.,0.,0.));
#1004=DIRECTION('',(0.,0.,-1.));
#1005=AXIS2_PLACEMENT_3D('',#1002,#1003,#1004);
#1006=CIRCLE('',#1005,0.75);
#1007=CARTESIAN_POINT('',(498.5,-0.75,1.50000000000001));
#1008=VERTEX_POINT('',#1007);
#1009=EDGE_CURVE('E1515',#1008,#328,#1006,.T.);
#1010=ORIENTED_EDGE('',*,*,#1009,.F.);
#1011=DIRECTION('',(0.,1.,0.));
#1012=VECTOR('',#1011,1.);
#1013=CARTESIAN_POINT('',(498.5,-0.75,1.50000000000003));
#1014=LINE('',#1013,#1012);
#1015=CARTESIAN_POINT('',(498.5,-1.5,1.50000000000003));
#1016=VERTEX_POINT('',#1015);
#1017=EDGE_CURVE('E1526',#1008,#1016,#1014,.F.);
#1018=ORIENTED_EDGE('',*,*,#1017,.T.);
#1019=CARTESIAN_POINT('',(498.5,0.,1.50000000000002));
#1020=DIRECTION('',(1.,0.,0.));
#1021=DIRECTION('',(0.,0.,-1.));
#1022=AXIS2_PLACEMENT_3D('',#1019,#1020,#1021);
#1023=CIRCLE('',#1022,1.5);
#1024=EDGE_CURVE('E1509',#1016,#80,#1023,.T.);
#1025=ORIENTED_EDGE('',*,*,#1024,.T.);
#1026=ORIENTED_EDGE('',*,*,#588,.F.);
#1027=EDGE_LOOP('',(#1010,#1018,#1025,#1026));
#1028=FACE_BOUND('',#1027,.T.);
#1029=ADVANCED_FACE('F1003',(#1028),#1001,.F.);
#1030=CARTESIAN_POINT('',(498.5,0.,1.50000000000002));
#1031=DIRECTION('',(1.,0.,0.));
#1032=DIRECTION('',(0.,-1.,0.));
#1033=AXIS2_PLACEMENT_3D('',#1030,#1031,#1032);
#1034=CYLINDRICAL_SURFACE('',#1033,1.5);
#1035=ORIENTED_EDGE('',*,*,#89,.T.);
#1036=ORIENTED_EDGE('',*,*,#1024,.F.);
#1037=DIRECTION('',(1.,0.,0.));
#1038=VECTOR('',#1037,1.);
#1039=CARTESIAN_POINT('',(1.5,-1.5,1.49999999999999));
#1040=LINE('',#1039,#1038);
#1041=EDGE_CURVE('E1529',#1016,#976,#1040,.F.);
#1042=ORIENTED_EDGE('',*,*,#1041,.T.);
#1043=ORIENTED_EDGE('',*,*,#992,.F.);
#1044=EDGE_LOOP('',(#1035,#1036,#1042,#1043));
#1045=FACE_BOUND('',#1044,.T.);
#1046=ADVANCED_FACE('F1001',(#1045),#1034,.T.);
#1047=CARTESIAN_POINT('',(498.5,0.,1.50000000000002));
#1048=DIRECTION('',(1.,0.,0.));
#1049=DIRECTION('',(0.,-1.,0.));
#1050=AXIS2_PLACEMENT_3D('',#1047,#1048,#1049);
#1051=CYLINDRICAL_SURFACE('',#1050,0.75);
#1052=ORIENTED_EDGE('',*,*,#351,.F.);
#1053=ORIENTED_EDGE('',*,*,#984,.T.);
#1054=DIRECTION('',(1.,0.,0.));
#1055=VECTOR('',#1054,1.);
#1056=CARTESIAN_POINT('',(1.5,-0.75,1.5));
#1057=LINE('',#1056,#1055);
#1058=EDGE_CURVE('E1524',#974,#1008,#1057,.T.);
#1059=ORIENTED_EDGE('',*,*,#1058,.T.);
#1060=ORIENTED_EDGE('',*,*,#1009,.T.);
#1061=EDGE_LOOP('',(#1052,#1053,#1059,#1060));
#1062=FACE_BOUND('',#1061,.T.);
#1063=ADVANCED_FACE('F997',(#1062),#1051,.F.);
#1064=CARTESIAN_POINT('',(1.5,-1.5,0.749999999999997));
#1065=DIRECTION('',(1.,0.,0.));
#1066=DIRECTION('',(0.,0.,-1.));
#1067=AXIS2_PLACEMENT_3D('',#1064,#1065,#1066);
#1068=PLANE('',#1067);
#1069=ORIENTED_EDGE('',*,*,#977,.T.);
#1070=DIRECTION('',(0.,0.,-1.));
#1071=VECTOR('',#1070,1.);
#1072=CARTESIAN_POINT('',(1.5,-1.5,0.749999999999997));
#1073=LINE('',#1072,#1071);
#1074=CARTESIAN_POINT('',(1.5,-1.50000000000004,12.));
#1075=VERTEX_POINT('',#1074);
#1076=EDGE_CURVE('E1538',#1075,#976,#1073,.T.);
#1077=ORIENTED_EDGE('',*,*,#1076,.F.);
#1078=DIRECTION('',(0.,1.,0.));
#1079=VECTOR('',#1078,1.);
#1080=CARTESIAN_POINT('',(1.5,-1.50000000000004,12.));
#1081=LINE('',#1080,#1079);
#1082=CARTESIAN_POINT('',(1.5,-0.750000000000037,12.));
#1083=VERTEX_POINT('',#1082);
#1084=EDGE_CURVE('E1545',#1075,#1083,#1081,.T.);
#1085=ORIENTED_EDGE('',*,*,#1084,.T.);
#1086=DIRECTION('',(0.,0.,1.));
#1087=VECTOR('',#1086,1.);
#1088=CARTESIAN_POINT('',(1.5,-0.749999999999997,0.75));
#1089=LINE('',#1088,#1087);
#1090=EDGE_CURVE('E1531',#1083,#974,#1089,.F.);
#1091=ORIENTED_EDGE('',*,*,#1090,.T.);
#1092=EDGE_LOOP('',(#1069,#1077,#1085,#1091));
#1093=FACE_BOUND('',#1092,.T.);
#1094=ADVANCED_FACE('F993',(#1093),#1068,.F.);
#1095=CARTESIAN_POINT('',(498.5,-1.50000000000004,12.));
#1096=DIRECTION('',(-1.,0.,0.));
#1097=DIRECTION('',(0.,-1.,0.));
#1098=AXIS2_PLACEMENT_3D('',#1095,#1096,#1097);
#1099=PLANE('',#1098);
#1100=ORIENTED_EDGE('',*,*,#1017,.F.);
#1101=DIRECTION('',(0.,0.,-1.));
#1102=VECTOR('',#1101,1.);
#1103=CARTESIAN_POINT('',(498.5,-0.750000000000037,12.));
#1104=LINE('',#1103,#1102);
#1105=CARTESIAN_POINT('',(498.5,-0.750000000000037,12.));
#1106=VERTEX_POINT('',#1105);
#1107=EDGE_CURVE('E1534',#1008,#1106,#1104,.F.);
#1108=ORIENTED_EDGE('',*,*,#1107,.T.);
#1109=DIRECTION('',(0.,1.,0.));
#1110=VECTOR('',#1109,1.);
#1111=CARTESIAN_POINT('',(498.5,-1.50000000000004,12.));
#1112=LINE('',#1111,#1110);
#1113=CARTESIAN_POINT('',(498.5,-1.50000000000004,12.));
#1114=VERTEX_POINT('',#1113);
#1115=EDGE_CURVE('E1518',#1114,#1106,#1112,.T.);
#1116=ORIENTED_EDGE('',*,*,#1115,.F.);
#1117=DIRECTION('',(0.,0.,1.));
#1118=VECTOR('',#1117,1.);
#1119=CARTESIAN_POINT('',(498.5,-1.5,0.749999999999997));
#1120=LINE('',#1119,#1118);
#1121=EDGE_CURVE('E1541',#1016,#1114,#1120,.T.);
#1122=ORIENTED_EDGE('',*,*,#1121,.F.);
#1123=EDGE_LOOP('',(#1100,#1108,#1116,#1122));
#1124=FACE_BOUND('',#1123,.T.);
#1125=ADVANCED_FACE('F986',(#1124),#1099,.F.);
#1126=CARTESIAN_POINT('',(1.5,-1.5,0.749999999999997));
#1127=DIRECTION('',(0.,1.,0.));
#1128=DIRECTION('',(0.,0.,1.));
#1129=AXIS2_PLACEMENT_3D('',#1126,#1127,#1128);
#1130=PLANE('',#1129);
#1131=ORIENTED_EDGE('',*,*,#1041,.F.);
#1132=ORIENTED_EDGE('',*,*,#1121,.T.);
#1133=DIRECTION('',(-1.,0.,0.));
#1134=VECTOR('',#1133,1.);
#1135=CARTESIAN_POINT('',(1.5,-1.50000000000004,12.));
#1136=LINE('',#1135,#1134);
#1137=EDGE_CURVE('E1543',#1114,#1075,#1136,.T.);
#1138=ORIENTED_EDGE('',*,*,#1137,.T.);
#1139=ORIENTED_EDGE('',*,*,#1076,.T.);
#1140=EDGE_LOOP('',(#1131,#1132,#1138,#1139));
#1141=FACE_BOUND('',#1140,.T.);
#1142=ADVANCED_FACE('F982',(#1141),#1130,.F.);
#1143=CARTESIAN_POINT('',(1.5,-0.749999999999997,0.75));
#1144=DIRECTION('',(0.,1.,0.));
#1145=DIRECTION('',(0.,0.,1.));
#1146=AXIS2_PLACEMENT_3D('',#1143,#1144,#1145);
#1147=PLANE('',#1146);
#1148=ORIENTED_EDGE('',*,*,#1107,.F.);
#1149=ORIENTED_EDGE('',*,*,#1058,.F.);
#1150=ORIENTED_EDGE('',*,*,#1090,.F.);
#1151=DIRECTION('',(1.,0.,0.));
#1152=VECTOR('',#1151,1.);
#1153=CARTESIAN_POINT('',(1.5,-0.750000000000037,12.));
#1154=LINE('',#1153,#1152);
#1155=EDGE_CURVE('E1536',#1106,#1083,#1154,.F.);
#1156=ORIENTED_EDGE('',*,*,#1155,.F.);
#1157=EDGE_LOOP('',(#1148,#1149,#1150,#1156));
#1158=FACE_BOUND('',#1157,.T.);
#1159=ADVANCED_FACE('F979',(#1158),#1147,.T.);
#1160=CARTESIAN_POINT('',(1.5,-1.50000000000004,12.));
#1161=DIRECTION('',(0.,0.,-1.));
#1162=DIRECTION('',(0.,1.,0.));
#1163=AXIS2_PLACEMENT_3D('',#1160,#1161,#1162);
#1164=PLANE('',#1163);
#1165=ORIENTED_EDGE('',*,*,#1155,.T.);
#1166=ORIENTED_EDGE('',*,*,#1084,.F.);
#1167=ORIENTED_EDGE('',*,*,#1137,.F.);
#1168=ORIENTED_EDGE('',*,*,#1115,.T.);
#1169=EDGE_LOOP('',(#1165,#1166,#1167,#1168));
#1170=FACE_BOUND('',#1169,.T.);
#1171=ADVANCED_FACE('F969',(#1170),#1164,.F.);
#1172=CARTESIAN_POINT('',(-0.00750000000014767,1000.,38.5));
#1173=CARTESIAN_POINT('',(-0.00750000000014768,999.994106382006,38.6973668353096));
#1174=CARTESIAN_POINT('',(0.0317361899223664,999.98821488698,38.8945849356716));
#1175=CARTESIAN_POINT('',(0.18276701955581,999.97642977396,39.2592056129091));
#1176=CARTESIAN_POINT('',(0.294502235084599,999.970537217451,39.4264291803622));
#1177=CARTESIAN_POINT('',(0.573570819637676,999.958752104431,39.7054977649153));
#1178=CARTESIAN_POINT('',(0.740794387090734,999.952859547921,39.8172329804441));
#1179=CARTESIAN_POINT('',(1.10541506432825,999.941074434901,39.9682638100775));
#1180=CARTESIAN_POINT('',(1.3026331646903,999.935182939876,40.0075));
#1181=CARTESIAN_POINT('',(1.49999999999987,999.929289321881,40.0075));
#1182=CARTESIAN_POINT('',(-1.47668335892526E-13,1000.,38.5));
#1183=CARTESIAN_POINT('',(-1.47678589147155E-13,999.994106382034,38.6963849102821));
#1184=CARTESIAN_POINT('',(0.0390409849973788,999.98821488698,38.8926218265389));
#1185=CARTESIAN_POINT('',(0.189320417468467,999.97642977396,39.2554284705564));
#1186=CARTESIAN_POINT('',(0.300499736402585,999.970537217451,39.4218200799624));
#1187=CARTESIAN_POINT('',(0.578179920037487,999.958752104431,39.6995002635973));
#1188=CARTESIAN_POINT('',(0.744571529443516,999.952859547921,39.8106795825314));
#1189=CARTESIAN_POINT('',(1.10737817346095,999.941074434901,39.9609590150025));
#1190=CARTESIAN_POINT('',(1.30361508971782,999.935182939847,40.));
#1191=CARTESIAN_POINT('',(1.49999999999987,999.929289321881,40.));
#1192=CARTESIAN_POINT('',(0.749999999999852,1000.,38.5));
#1193=CARTESIAN_POINT('',(0.749999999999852,999.994106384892,38.5981924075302));
#1194=CARTESIAN_POINT('',(0.769520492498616,999.98821488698,38.6963109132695));
#1195=CARTESIAN_POINT('',(0.844660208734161,999.97642977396,38.8777142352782));
#1196=CARTESIAN_POINT('',(0.90024986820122,999.97053721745,38.9609100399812));
#1197=CARTESIAN_POINT('',(1.03908996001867,999.958752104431,39.0997501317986));
#1198=CARTESIAN_POINT('',(1.12228576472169,999.952859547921,39.1553397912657));
#1199=CARTESIAN_POINT('',(1.3036890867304,999.941074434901,39.2304795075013));
#1200=CARTESIAN_POINT('',(1.40180759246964,999.935182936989,39.25));
#1201=CARTESIAN_POINT('',(1.49999999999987,999.929289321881,39.25));
#1202=CARTESIAN_POINT('',(0.757574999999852,1000.,38.5));
#1203=CARTESIAN_POINT('',(0.757574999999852,999.994106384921,38.5972006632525));
#1204=CARTESIAN_POINT('',(0.776898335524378,999.98821488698,38.6943281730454));
#1205=CARTESIAN_POINT('',(0.851279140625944,999.97642977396,38.8738993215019));
#1206=CARTESIAN_POINT('',(0.906307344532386,999.97053721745,38.9562548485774));
#1207=CARTESIAN_POINT('',(1.04374515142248,999.958752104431,39.0936926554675));
#1208=CARTESIAN_POINT('',(1.12610067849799,999.952859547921,39.1487208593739));
#1209=CARTESIAN_POINT('',(1.30567182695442,999.941074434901,39.2231016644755));
#1210=CARTESIAN_POINT('',(1.40279933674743,999.93518293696,39.242425));
#1211=CARTESIAN_POINT('',(1.49999999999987,999.929289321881,39.242425));
#1212=B_SPLINE_SURFACE_WITH_KNOTS('',1,3,((#1172,#1173,#1174,#1175,#1176,#1177,#1178,#1179,
#1180,#1181),(#1182,#1183,#1184,#1185,#1186,#1187,#1188,#1189,#1190,#1191),(#1192,#1193,#1194,
#1195,#1196,#1197,#1198,#1199,#1200,#1201),(#1202,#1203,#1204,#1205,#1206,#1207,#1208,#1209,
#1210,#1211)),.UNSPECIFIED.,.F.,.F.,.F.,(2,1,1,2),(4,2,2,2,4),(-0.01,0.,1.,1.0101),(0.,0.25,0.5,
0.75,1.),.UNSPECIFIED.);
#1213=DIRECTION('',(0.,0.,-1.));
#1214=VECTOR('',#1213,1.);
#1215=CARTESIAN_POINT('',(1.49999999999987,999.929289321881,39.25));
#1216=LINE('',#1215,#1214);
#1217=CARTESIAN_POINT('',(1.49999999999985,999.929289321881,40.));
#1218=VERTEX_POINT('',#1217);
#1219=CARTESIAN_POINT('',(1.49999999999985,999.929289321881,39.25));
#1220=VERTEX_POINT('',#1219);
#1221=EDGE_CURVE('E909',#1218,#1220,#1216,.T.);
#1222=CARTESIAN_POINT('',(0.749999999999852,1000.,38.5));
#1223=CARTESIAN_POINT('',(0.74999973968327,999.999263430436,38.5122718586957));
#1224=CARTESIAN_POINT('',(0.750301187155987,999.998526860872,38.5245436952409));
#1225=CARTESIAN_POINT('',(0.751505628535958,999.997053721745,38.5490578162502));
#1226=CARTESIAN_POINT('',(0.752408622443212,999.996317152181,38.5613001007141));
#1227=CARTESIAN_POINT('',(0.754814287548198,999.994844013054,38.5857256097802));
#1228=CARTESIAN_POINT('',(0.756316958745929,999.99410744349,38.5979088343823));
#1229=CARTESIAN_POINT('',(0.759918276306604,999.992634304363,38.6221868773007));
#1230=CARTESIAN_POINT('',(0.762016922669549,999.991897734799,38.6342816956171));
#1231=CARTESIAN_POINT('',(0.766805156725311,999.990424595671,38.6583537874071));
#1232=CARTESIAN_POINT('',(0.76949474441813,999.989688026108,38.6703310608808));
#1233=CARTESIAN_POINT('',(0.775458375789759,999.98821488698,38.6941392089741));
#1234=CARTESIAN_POINT('',(0.77873241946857,999.987478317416,38.7059700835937));
#1235=CARTESIAN_POINT('',(0.785857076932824,999.986005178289,38.729456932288));
#1236=CARTESIAN_POINT('',(0.789707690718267,999.985268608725,38.7411129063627));
#1237=CARTESIAN_POINT('',(0.797976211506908,999.983795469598,38.7642218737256));
#1238=CARTESIAN_POINT('',(0.802394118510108,999.983058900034,38.7756748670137));
#1239=CARTESIAN_POINT('',(0.811786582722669,999.981585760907,38.7983502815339));
#1240=CARTESIAN_POINT('',(0.816761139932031,999.980849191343,38.8095727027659));
#1241=CARTESIAN_POINT('',(0.827254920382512,999.979376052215,38.8317599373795));
#1242=CARTESIAN_POINT('',(0.832774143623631,999.978639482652,38.8427247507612));
#1243=CARTESIAN_POINT('',(0.844343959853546,999.977166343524,38.8643703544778));
#1244=CARTESIAN_POINT('',(0.850394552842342,999.97642977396,38.8750511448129));
#1245=CARTESIAN_POINT('',(0.863012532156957,999.974956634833,38.896102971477));
#1246=CARTESIAN_POINT('',(0.869579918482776,999.974220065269,38.9064740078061));
#1247=CARTESIAN_POINT('',(0.883215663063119,999.972746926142,38.9268813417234));
#1248=CARTESIAN_POINT('',(0.890284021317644,999.972010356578,38.9369176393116));
#1249=CARTESIAN_POINT('',(0.904904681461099,999.97053721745,38.9566313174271));
#1250=CARTESIAN_POINT('',(0.912456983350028,999.969800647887,38.9663086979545));
#1251=CARTESIAN_POINT('',(0.928027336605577,999.968327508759,38.985281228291));
#1252=CARTESIAN_POINT('',(0.936045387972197,999.967590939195,38.9945763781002));
#1253=CARTESIAN_POINT('',(0.952527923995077,999.966117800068,39.0127620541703));
#1254=CARTESIAN_POINT('',(0.960992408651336,999.965381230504,39.0216525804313));
#1255=CARTESIAN_POINT('',(0.978347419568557,999.963908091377,39.0390075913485));
#1256=CARTESIAN_POINT('',(0.987237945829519,999.963171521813,39.0474720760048));
#1257=CARTESIAN_POINT('',(1.00542362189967,999.961698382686,39.0639546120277));
#1258=CARTESIAN_POINT('',(1.01471877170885,999.960961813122,39.0719726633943));
#1259=CARTESIAN_POINT('',(1.0336913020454,999.959488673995,39.0875430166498));
#1260=CARTESIAN_POINT('',(1.04336868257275,999.958752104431,39.0950953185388));
#1261=CARTESIAN_POINT('',(1.06308236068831,999.957278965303,39.1097159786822));
#1262=CARTESIAN_POINT('',(1.07311865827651,999.956542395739,39.1167843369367));
#1263=CARTESIAN_POINT('',(1.0935259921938,999.955069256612,39.1304200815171));
#1264=CARTESIAN_POINT('',(1.10389702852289,999.954332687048,39.1369874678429));
#1265=CARTESIAN_POINT('',(1.124948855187,999.952859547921,39.1496054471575));
#1266=CARTESIAN_POINT('',(1.13562964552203,999.952122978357,39.1556560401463));
#1267=CARTESIAN_POINT('',(1.15727524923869,999.95064983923,39.1672258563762));
#1268=CARTESIAN_POINT('',(1.16824006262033,999.949913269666,39.1727450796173));
#1269=CARTESIAN_POINT('',(1.19042729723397,999.948440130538,39.1832388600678));
#1270=CARTESIAN_POINT('',(1.20164971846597,999.947703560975,39.1882134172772));
#1271=CARTESIAN_POINT('',(1.22432513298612,999.946230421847,39.1976058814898));
#1272=CARTESIAN_POINT('',(1.23577812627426,999.945493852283,39.202023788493));
#1273=CARTESIAN_POINT('',(1.25888709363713,999.944020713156,39.2102923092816));
#1274=CARTESIAN_POINT('',(1.27054306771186,999.943284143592,39.214142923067));
#1275=CARTESIAN_POINT('',(1.29402991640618,999.941811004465,39.2212675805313));
#1276=CARTESIAN_POINT('',(1.30586079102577,999.941074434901,39.2245416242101));
#1277=CARTESIAN_POINT('',(1.32966893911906,999.939601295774,39.2305052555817));
#1278=CARTESIAN_POINT('',(1.34164621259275,999.93886472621,39.2331948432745));
#1279=CARTESIAN_POINT('',(1.36571830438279,999.937391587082,39.2379830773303));
#1280=CARTESIAN_POINT('',(1.37781312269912,999.936655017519,39.2400817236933));
#1281=CARTESIAN_POINT('',(1.40209116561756,999.935181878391,39.2436830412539));
#1282=CARTESIAN_POINT('',(1.41427439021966,999.934445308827,39.2451857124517));
#1283=CARTESIAN_POINT('',(1.43869989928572,999.9329721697,39.2475913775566));
#1284=CARTESIAN_POINT('',(1.45094218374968,999.932235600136,39.2484943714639));
#1285=CARTESIAN_POINT('',(1.47545630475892,999.930762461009,39.2496988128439));
#1286=CARTESIAN_POINT('',(1.4877281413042,999.930025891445,39.2500002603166));
#1287=CARTESIAN_POINT('',(1.49999999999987,999.929289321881,39.25));
#1288=B_SPLINE_CURVE_WITH_KNOTS('',3,(#1222,#1223,#1224,#1225,#1226,#1227,#1228,#1229,#1230,
#1231,#1232,#1233,#1234,#1235,#1236,#1237,#1238,#1239,#1240,#1241,#1242,#1243,#1244,#1245,#1246,
#1247,#1248,#1249,#1250,#1251,#1252,#1253,#1254,#1255,#1256,#1257,#1258,#1259,#1260,#1261,#1262,
#1263,#1264,#1265,#1266,#1267,#1268,#1269,#1270,#1271,#1272,#1273,#1274,#1275,#1276,#1277,#1278,
#1279,#1280,#1281,#1282,#1283,#1284,#1285,#1286,#1287),.UNSPECIFIED.,.F.,.F.,(4,2,2,2,2,2,2,2,2,
2,2,2,2,2,2,2,2,2,2,2,2,2,2,2,2,2,2,2,2,2,2,2,4),(0.,0.0368781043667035,0.0737562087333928,
0.110634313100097,0.1475124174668,0.1843905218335,0.221268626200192,0.258146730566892,
0.295024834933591,0.331902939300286,0.368781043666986,0.405659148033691,0.442537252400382,
0.479415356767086,0.516293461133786,0.553171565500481,0.590049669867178,0.626927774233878,
0.663805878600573,0.700683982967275,0.737562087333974,0.77444019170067,0.81131829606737,
0.848196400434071,0.885074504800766,0.921952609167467,0.958830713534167,0.995708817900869,
1.03258692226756,1.06946502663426,1.10634313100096,1.14322123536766,1.18009933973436),.UNSPECIFIED.);
#1289=EDGE_CURVE('E933',#485,#1220,#1288,.T.);
#1290=CARTESIAN_POINT('',(-1.47668335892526E-13,1000.,38.5));
#1291=CARTESIAN_POINT('',(-5.20633310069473E-07,999.999263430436,38.5245437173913));
#1292=CARTESIAN_POINT('',(0.00060237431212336,999.998526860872,38.5490873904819));
#1293=CARTESIAN_POINT('',(0.0030112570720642,999.997053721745,38.5981156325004));
#1294=CARTESIAN_POINT('',(0.00481724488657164,999.996317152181,38.6226002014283));
#1295=CARTESIAN_POINT('',(0.0096285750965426,999.994844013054,38.6714512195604));
#1296=CARTESIAN_POINT('',(0.012633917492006,999.99410744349,38.6958176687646));
#1297=CARTESIAN_POINT('',(0.0198365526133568,999.992634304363,38.7443737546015));
#1298=CARTESIAN_POINT('',(0.0240338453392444,999.991897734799,38.7685633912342));
#1299=CARTESIAN_POINT('',(0.0336103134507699,999.990424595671,38.8167075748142));
#1300=CARTESIAN_POINT('',(0.0389894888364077,999.989688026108,38.8406621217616));
#1301=CARTESIAN_POINT('',(0.0509167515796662,999.98821488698,38.8882784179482));
#1302=CARTESIAN_POINT('',(0.0574648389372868,999.987478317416,38.9119401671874));
#1303=CARTESIAN_POINT('',(0.0717141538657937,999.986005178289,38.958913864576));
#1304=CARTESIAN_POINT('',(0.07941538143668,999.985268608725,38.9822258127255));
#1305=CARTESIAN_POINT('',(0.0959524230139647,999.983795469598,39.0284437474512));
#1306=CARTESIAN_POINT('',(0.104788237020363,999.983058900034,39.0513497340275));
#1307=CARTESIAN_POINT('',(0.123573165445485,999.981585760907,39.0967005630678));
#1308=CARTESIAN_POINT('',(0.133522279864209,999.980849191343,39.1191454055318));
#1309=CARTESIAN_POINT('',(0.15450984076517,999.979376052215,39.1635198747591));
#1310=CARTESIAN_POINT('',(0.165548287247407,999.978639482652,39.1854495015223));
#1311=CARTESIAN_POINT('',(0.188687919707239,999.977166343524,39.2287407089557));
#1312=CARTESIAN_POINT('',(0.200789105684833,999.97642977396,39.2501022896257));
#1313=CARTESIAN_POINT('',(0.226025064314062,999.974956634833,39.292205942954));
#1314=CARTESIAN_POINT('',(0.239159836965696,999.974220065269,39.3129480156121));
#1315=CARTESIAN_POINT('',(0.266431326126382,999.972746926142,39.3537626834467));
#1316=CARTESIAN_POINT('',(0.280568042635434,999.972010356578,39.3738352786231));
#1317=CARTESIAN_POINT('',(0.309809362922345,999.97053721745,39.4132626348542));
#1318=CARTESIAN_POINT('',(0.324913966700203,999.969800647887,39.4326173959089));
#1319=CARTESIAN_POINT('',(0.356054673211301,999.968327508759,39.470562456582));
#1320=CARTESIAN_POINT('',(0.372090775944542,999.967590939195,39.4891527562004));
#1321=CARTESIAN_POINT('',(0.405055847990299,999.966117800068,39.5255241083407));
#1322=CARTESIAN_POINT('',(0.421984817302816,999.965381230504,39.5433051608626));
#1323=CARTESIAN_POINT('',(0.456694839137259,999.963908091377,39.5780151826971));
#1324=CARTESIAN_POINT('',(0.474475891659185,999.963171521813,39.5949441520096));
#1325=CARTESIAN_POINT('',(0.51084724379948,999.961698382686,39.6279092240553));
#1326=CARTESIAN_POINT('',(0.529437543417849,999.960961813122,39.6439453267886));
#1327=CARTESIAN_POINT('',(0.567382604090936,999.959488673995,39.6750860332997));
#1328=CARTESIAN_POINT('',(0.586737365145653,999.958752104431,39.6901906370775));
#1329=CARTESIAN_POINT('',(0.626164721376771,999.957278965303,39.7194319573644));
#1330=CARTESIAN_POINT('',(0.646237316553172,999.956542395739,39.7335686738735));
#1331=CARTESIAN_POINT('',(0.687051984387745,999.955069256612,39.7608401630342));
#1332=CARTESIAN_POINT('',(0.707794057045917,999.954332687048,39.7739749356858));
#1333=CARTESIAN_POINT('',(0.749897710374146,999.952859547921,39.799210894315));
#1334=CARTESIAN_POINT('',(0.771259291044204,999.952122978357,39.8113120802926));
#1335=CARTESIAN_POINT('',(0.814550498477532,999.95064983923,39.8344517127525));
#1336=CARTESIAN_POINT('',(0.836480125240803,999.949913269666,39.8454901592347));
#1337=CARTESIAN_POINT('',(0.88085459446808,999.948440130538,39.8664777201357));
#1338=CARTESIAN_POINT('',(0.903299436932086,999.947703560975,39.8764268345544));
#1339=CARTESIAN_POINT('',(0.94865026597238,999.946230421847,39.8952117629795));
#1340=CARTESIAN_POINT('',(0.971556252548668,999.945493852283,39.9040475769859));
#1341=CARTESIAN_POINT('',(1.01777418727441,999.944020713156,39.9205846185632));
#1342=CARTESIAN_POINT('',(1.04108613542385,999.943284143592,39.9282858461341));
#1343=CARTESIAN_POINT('',(1.08805983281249,999.941811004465,39.9425351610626));
#1344=CARTESIAN_POINT('',(1.11172158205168,999.941074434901,39.9490832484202));
#1345=CARTESIAN_POINT('',(1.15933787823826,999.939601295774,39.9610105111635));
#1346=CARTESIAN_POINT('',(1.18329242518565,999.93886472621,39.9663896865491));
#1347=CARTESIAN_POINT('',(1.23143660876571,999.937391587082,39.9759661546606));
#1348=CARTESIAN_POINT('',(1.25562624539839,999.936655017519,39.9801634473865));
#1349=CARTESIAN_POINT('',(1.30418233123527,999.935181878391,39.9873660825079));
#1350=CARTESIAN_POINT('',(1.32854878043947,999.934445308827,39.9903714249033));
#1351=CARTESIAN_POINT('',(1.37739979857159,999.9329721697,39.9951827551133));
#1352=CARTESIAN_POINT('',(1.40188436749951,999.932235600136,39.9969887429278));
#1353=CARTESIAN_POINT('',(1.45091260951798,999.930762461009,39.9993976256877));
#1354=CARTESIAN_POINT('',(1.47545628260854,999.930025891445,40.0000005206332));
#1355=CARTESIAN_POINT('',(1.49999999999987,999.929289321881,40.));
#1356=B_SPLINE_CURVE_WITH_KNOTS('',3,(#1290,#1291,#1292,#1293,#1294,#1295,#1296,#1297,#1298,
#1299,#1300,#1301,#1302,#1303,#1304,#1305,#1306,#1307,#1308,#1309,#1310,#1311,#1312,#1313,#1314,
#1315,#1316,#1317,#1318,#1319,#1320,#1321,#1322,#1323,#1324,#1325,#1326,#1327,#1328,#1329,#1330,
#1331,#1332,#1333,#1334,#1335,#1336,#1337,#1338,#1339,#1340,#1341,#1342,#1343,#1344,#1345,#1346,
#1347,#1348,#1349,#1350,#1351,#1352,#1353,#1354,#1355),.UNSPECIFIED.,.F.,.F.,(4,2,2,2,2,2,2,2,2,
2,2,2,2,2,2,2,2,2,2,2,2,2,2,2,2,2,2,2,2,2,2,2,4),(0.,0.0736568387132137,0.14731367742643,
0.220970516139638,0.294627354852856,0.368284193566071,0.441941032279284,0.515597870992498,
0.589254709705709,0.662911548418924,0.736568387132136,0.810225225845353,0.883882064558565,
0.95753890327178,1.03119574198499,1.1048525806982,1.17850941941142,1.25216625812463,
1.32582309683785,1.39947993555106,1.47313677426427,1.54679361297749,1.6204504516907,
1.69410729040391,1.76776412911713,1.84142096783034,1.91507780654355,1.98873464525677,
2.06239148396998,2.1360483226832,2.20970516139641,2.28336200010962,2.35701883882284),.UNSPECIFIED.);
#1357=EDGE_CURVE('E937',#477,#1218,#1356,.T.);
#1358=ORIENTED_EDGE('',*,*,#1221,.T.);
#1359=ORIENTED_EDGE('',*,*,#1289,.F.);
#1360=ORIENTED_EDGE('',*,*,#486,.F.);
#1361=ORIENTED_EDGE('',*,*,#1357,.T.);
#1362=EDGE_LOOP('',(#1358,#1359,#1360,#1361));
#1363=FACE_BOUND('',#1362,.T.);
#1364=ADVANCED_FACE('F964',(#1363),#1212,.F.);
#1365=CARTESIAN_POINT('',(1.49999999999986,0.,38.5));
#1366=DIRECTION('',(0.,1.,0.));
#1367=DIRECTION('',(0.,0.,1.));
#1368=AXIS2_PLACEMENT_3D('',#1365,#1366,#1367);
#1369=PLANE('',#1368);
#1370=CARTESIAN_POINT('',(1.49999999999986,0.,38.5));
#1371=DIRECTION('',(0.,-1.,0.));
#1372=DIRECTION('',(0.,0.,-1.));
#1373=AXIS2_PLACEMENT_3D('',#1370,#1371,#1372);
#1374=CIRCLE('',#1373,0.750000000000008);
#1375=CARTESIAN_POINT('',(1.49999999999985,0.,39.25));
#1376=VERTEX_POINT('',#1375);
#1377=EDGE_CURVE('E911',#1376,#508,#1374,.T.);
#1378=ORIENTED_EDGE('',*,*,#1377,.F.);
#1379=DIRECTION('',(0.,0.,1.));
#1380=VECTOR('',#1379,1.);
#1381=CARTESIAN_POINT('',(1.49999999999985,0.,39.25));
#1382=LINE('',#1381,#1380);
#1383=CARTESIAN_POINT('',(1.49999999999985,0.,40.));
#1384=VERTEX_POINT('',#1383);
#1385=EDGE_CURVE('E927',#1376,#1384,#1382,.T.);
#1386=ORIENTED_EDGE('',*,*,#1385,.T.);
#1387=CARTESIAN_POINT('',(1.49999999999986,0.,38.5));
#1388=DIRECTION('',(0.,-1.,0.));
#1389=DIRECTION('',(0.,0.,-1.));
#1390=AXIS2_PLACEMENT_3D('',#1387,#1388,#1389);
#1391=CIRCLE('',#1390,1.50000000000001);
#1392=EDGE_CURVE('E934',#1384,#516,#1391,.T.);
#1393=ORIENTED_EDGE('',*,*,#1392,.T.);
#1394=ORIENTED_EDGE('',*,*,#517,.T.);
#1395=EDGE_LOOP('',(#1378,#1386,#1393,#1394));
#1396=FACE_BOUND('',#1395,.T.);
#1397=ADVANCED_FACE('F957',(#1396),#1369,.F.);
#1398=CARTESIAN_POINT('',(1.49999999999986,0.,38.5));
#1399=DIRECTION('',(0.,-1.,0.));
#1400=DIRECTION('',(0.,0.,1.));
#1401=AXIS2_PLACEMENT_3D('',#1398,#1399,#1400);
#1402=CYLINDRICAL_SURFACE('',#1401,1.50000000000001);
#1403=ORIENTED_EDGE('',*,*,#539,.F.);
#1404=ORIENTED_EDGE('',*,*,#1392,.F.);
#1405=DIRECTION('',(0.,-1.,0.));
#1406=VECTOR('',#1405,1.);
#1407=CARTESIAN_POINT('',(1.49999999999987,1000.,40.));
#1408=LINE('',#1407,#1406);
#1409=EDGE_CURVE('E925',#1384,#1218,#1408,.F.);
#1410=ORIENTED_EDGE('',*,*,#1409,.T.);
#1411=ORIENTED_EDGE('',*,*,#1357,.F.);
#1412=EDGE_LOOP('',(#1403,#1404,#1410,#1411));
#1413=FACE_BOUND('',#1412,.T.);
#1414=ADVANCED_FACE('F955',(#1413),#1402,.T.);
#1415=CARTESIAN_POINT('',(1.49999999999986,0.,38.5));
#1416=DIRECTION('',(0.,-1.,0.));
#1417=DIRECTION('',(0.,0.,1.));
#1418=AXIS2_PLACEMENT_3D('',#1415,#1416,#1417);
#1419=CYLINDRICAL_SURFACE('',#1418,0.750000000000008);
#1420=ORIENTED_EDGE('',*,*,#557,.T.);
#1421=ORIENTED_EDGE('',*,*,#1289,.T.);
#1422=DIRECTION('',(0.,-1.,0.));
#1423=VECTOR('',#1422,1.);
#1424=CARTESIAN_POINT('',(1.49999999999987,1000.,39.25));
#1425=LINE('',#1424,#1423);
#1426=EDGE_CURVE('E908',#1220,#1376,#1425,.T.);
#1427=ORIENTED_EDGE('',*,*,#1426,.T.);
#1428=ORIENTED_EDGE('',*,*,#1377,.T.);
#1429=EDGE_LOOP('',(#1420,#1421,#1427,#1428));
#1430=FACE_BOUND('',#1429,.T.);
#1431=ADVANCED_FACE('F945',(#1430),#1419,.F.);
#1432=CARTESIAN_POINT('',(16.4999999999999,1000.,40.0000000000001));
#1433=DIRECTION('',(0.,0.,-1.));
#1434=DIRECTION('',(-1.,0.,0.));
#1435=AXIS2_PLACEMENT_3D('',#1432,#1433,#1434);
#1436=PLANE('',#1435);
#1437=DIRECTION('',(0.707106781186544,-0.707106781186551,0.));
#1438=VECTOR('',#1437,1.);
#1439=CARTESIAN_POINT('',(1.49999999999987,999.929289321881,40.));
#1440=LINE('',#1439,#1438);
#1441=CARTESIAN_POINT('',(16.4999999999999,984.929289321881,40.0000000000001));
#1442=VERTEX_POINT('',#1441);
#1443=EDGE_CURVE('E895',#1218,#1442,#1440,.T.);
#1444=ORIENTED_EDGE('',*,*,#1443,.F.);
#1445=ORIENTED_EDGE('',*,*,#1409,.F.);
#1446=DIRECTION('',(1.,0.,0.));
#1447=VECTOR('',#1446,1.);
#1448=CARTESIAN_POINT('',(16.4999999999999,0.,40.0000000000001));
#1449=LINE('',#1448,#1447);
#1450=CARTESIAN_POINT('',(16.4999999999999,0.,40.0000000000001));
#1451=VERTEX_POINT('',#1450);
#1452=EDGE_CURVE('E915',#1451,#1384,#1449,.F.);
#1453=ORIENTED_EDGE('',*,*,#1452,.F.);
#1454=DIRECTION('',(0.,1.,0.));
#1455=VECTOR('',#1454,1.);
#1456=CARTESIAN_POINT('',(16.4999999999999,1000.,40.0000000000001));
#1457=LINE('',#1456,#1455);
#1458=EDGE_CURVE('E918',#1442,#1451,#1457,.F.);
#1459=ORIENTED_EDGE('',*,*,#1458,.F.);
#1460=EDGE_LOOP('',(#1444,#1445,#1453,#1459));
#1461=FACE_BOUND('',#1460,.T.);
#1462=ADVANCED_FACE('F954',(#1461),#1436,.F.);
#1463=CARTESIAN_POINT('',(16.4999999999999,1000.,39.2500000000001));
#1464=DIRECTION('',(0.,0.,-1.));
#1465=DIRECTION('',(-1.,0.,0.));
#1466=AXIS2_PLACEMENT_3D('',#1463,#1464,#1465);
#1467=PLANE('',#1466);
#1468=ORIENTED_EDGE('',*,*,#1426,.F.);
#1469=DIRECTION('',(0.707106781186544,-0.707106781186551,0.));
#1470=VECTOR('',#1469,1.);
#1471=CARTESIAN_POINT('',(8.9646446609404,992.464644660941,39.2500000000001));
#1472=LINE('',#1471,#1470);
#1473=CARTESIAN_POINT('',(16.4999999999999,984.929289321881,39.2500000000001));
#1474=VERTEX_POINT('',#1473);
#1475=EDGE_CURVE('E905',#1220,#1474,#1472,.T.);
#1476=ORIENTED_EDGE('',*,*,#1475,.T.);
#1477=DIRECTION('',(0.,-1.,0.));
#1478=VECTOR('',#1477,1.);
#1479=CARTESIAN_POINT('',(16.4999999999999,1000.,39.2500000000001));
#1480=LINE('',#1479,#1478);
#1481=CARTESIAN_POINT('',(16.4999999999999,0.,39.2500000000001));
#1482=VERTEX_POINT('',#1481);
#1483=EDGE_CURVE('E923',#1474,#1482,#1480,.T.);
#1484=ORIENTED_EDGE('',*,*,#1483,.T.);
#1485=DIRECTION('',(-1.,0.,0.));
#1486=VECTOR('',#1485,1.);
#1487=CARTESIAN_POINT('',(16.4999999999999,0.,39.2500000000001));
#1488=LINE('',#1487,#1486);
#1489=EDGE_CURVE('E920',#1482,#1376,#1488,.T.);
#1490=ORIENTED_EDGE('',*,*,#1489,.T.);
#1491=EDGE_LOOP('',(#1468,#1476,#1484,#1490));
#1492=FACE_BOUND('',#1491,.T.);
#1493=ADVANCED_FACE('F1678',(#1492),#1467,.T.);
#1494=CARTESIAN_POINT('',(16.4999999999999,1000.,40.0000000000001));
#1495=DIRECTION('',(1.,0.,0.));
#1496=DIRECTION('',(0.,0.,-1.));
#1497=AXIS2_PLACEMENT_3D('',#1494,#1495,#1496);
#1498=PLANE('',#1497);
#1499=ORIENTED_EDGE('',*,*,#1483,.F.);
#1500=DIRECTION('',(0.,0.,1.));
#1501=VECTOR('',#1500,1.);
#1502=CARTESIAN_POINT('',(16.4999999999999,984.929289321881,40.0000000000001));
#1503=LINE('',#1502,#1501);
#1504=EDGE_CURVE('E902',#1474,#1442,#1503,.T.);
#1505=ORIENTED_EDGE('',*,*,#1504,.T.);
#1506=ORIENTED_EDGE('',*,*,#1458,.T.);
#1507=DIRECTION('',(0.,0.,-1.));
#1508=VECTOR('',#1507,1.);
#1509=CARTESIAN_POINT('',(16.4999999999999,0.,40.0000000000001));
#1510=LINE('',#1509,#1508);
#1511=EDGE_CURVE('E912',#1451,#1482,#1510,.T.);
#1512=ORIENTED_EDGE('',*,*,#1511,.T.);
#1513=EDGE_LOOP('',(#1499,#1505,#1506,#1512));
#1514=FACE_BOUND('',#1513,.T.);
#1515=ADVANCED_FACE('F958',(#1514),#1498,.T.);
#1516=CARTESIAN_POINT('',(16.4999999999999,0.,40.0000000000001));
#1517=DIRECTION('',(0.,-1.,0.));
#1518=DIRECTION('',(1.,0.,0.));
#1519=AXIS2_PLACEMENT_3D('',#1516,#1517,#1518);
#1520=PLANE('',#1519);
#1521=ORIENTED_EDGE('',*,*,#1452,.T.);
#1522=ORIENTED_EDGE('',*,*,#1385,.F.);
#1523=ORIENTED_EDGE('',*,*,#1489,.F.);
#1524=ORIENTED_EDGE('',*,*,#1511,.F.);
#1525=EDGE_LOOP('',(#1521,#1522,#1523,#1524));
#1526=FACE_BOUND('',#1525,.T.);
#1527=ADVANCED_FACE('F1683',(#1526),#1520,.T.);
#1528=CARTESIAN_POINT('',(1.49999999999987,999.929289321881,40.));
#1529=DIRECTION('',(0.707106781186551,0.707106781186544,0.));
#1530=DIRECTION('',(-0.707106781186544,0.707106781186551,0.));
#1531=AXIS2_PLACEMENT_3D('',#1528,#1529,#1530);
#1532=PLANE('',#1531);
#1533=ORIENTED_EDGE('',*,*,#1475,.F.);
#1534=ORIENTED_EDGE('',*,*,#1221,.F.);
#1535=ORIENTED_EDGE('',*,*,#1443,.T.);
#1536=ORIENTED_EDGE('',*,*,#1504,.F.);
#1537=EDGE_LOOP('',(#1533,#1534,#1535,#1536));
#1538=FACE_BOUND('',#1537,.T.);
#1539=ADVANCED_FACE('F1693',(#1538),#1532,.T.);
#1540=CARTESIAN_POINT('',(498.5,1001.5075,38.5));
#1541=CARTESIAN_POINT('',(498.494106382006,1001.5075,38.6973668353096));
#1542=CARTESIAN_POINT('',(498.48821488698,1001.46826381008,38.8945849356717));
#1543=CARTESIAN_POINT('',(498.47642977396,1001.31723298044,39.2592056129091));
#1544=CARTESIAN_POINT('',(498.470537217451,1001.20549776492,39.4264291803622));
#1545=CARTESIAN_POINT('',(498.458752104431,1000.92642918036,39.7054977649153));
#1546=CARTESIAN_POINT('',(498.452859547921,1000.75920561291,39.8172329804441));
#1547=CARTESIAN_POINT('',(498.441074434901,1000.39458493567,39.9682638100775));
#1548=CARTESIAN_POINT('',(498.435182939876,1000.19736683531,40.0075));
#1549=CARTESIAN_POINT('',(498.429289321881,1000.,40.0075));
#1550=CARTESIAN_POINT('',(498.5,1001.5,38.5));
#1551=CARTESIAN_POINT('',(498.494106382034,1001.5,38.6963849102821));
#1552=CARTESIAN_POINT('',(498.48821488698,1001.460959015,38.892621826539));
#1553=CARTESIAN_POINT('',(498.47642977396,1001.31067958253,39.2554284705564));
#1554=CARTESIAN_POINT('',(498.470537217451,1001.1995002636,39.4218200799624));
#1555=CARTESIAN_POINT('',(498.458752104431,1000.92182007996,39.6995002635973));
#1556=CARTESIAN_POINT('',(498.452859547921,1000.75542847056,39.8106795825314));
#1557=CARTESIAN_POINT('',(498.441074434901,1000.39262182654,39.9609590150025));
#1558=CARTESIAN_POINT('',(498.435182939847,1000.19638491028,40.));
#1559=CARTESIAN_POINT('',(498.429289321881,1000.,40.));
#1560=CARTESIAN_POINT('',(498.5,1000.75,38.5));
#1561=CARTESIAN_POINT('',(498.494106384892,1000.75,38.5981924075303));
#1562=CARTESIAN_POINT('',(498.48821488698,1000.7304795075,38.6963109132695));
#1563=CARTESIAN_POINT('',(498.47642977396,1000.65533979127,38.8777142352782));
#1564=CARTESIAN_POINT('',(498.470537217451,1000.5997501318,38.9609100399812));
#1565=CARTESIAN_POINT('',(498.458752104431,1000.46091003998,39.0997501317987));
#1566=CARTESIAN_POINT('',(498.452859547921,1000.37771423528,39.1553397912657));
#1567=CARTESIAN_POINT('',(498.441074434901,1000.19631091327,39.2304795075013));
#1568=CARTESIAN_POINT('',(498.435182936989,1000.09819240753,39.25));
#1569=CARTESIAN_POINT('',(498.429289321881,1000.,39.25));
#1570=CARTESIAN_POINT('',(498.5,1000.742425,38.5));
#1571=CARTESIAN_POINT('',(498.494106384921,1000.742425,38.5972006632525));
#1572=CARTESIAN_POINT('',(498.48821488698,1000.72310166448,38.6943281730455));
#1573=CARTESIAN_POINT('',(498.47642977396,1000.64872085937,38.8738993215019));
#1574=CARTESIAN_POINT('',(498.470537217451,1000.59369265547,38.9562548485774));
#1575=CARTESIAN_POINT('',(498.458752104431,1000.45625484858,39.0936926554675));
#1576=CARTESIAN_POINT('',(498.452859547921,1000.3738993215,39.1487208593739));
#1577=CARTESIAN_POINT('',(498.441074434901,1000.19432817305,39.2231016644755));
#1578=CARTESIAN_POINT('',(498.43518293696,1000.09720066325,39.242425));
#1579=CARTESIAN_POINT('',(498.429289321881,1000.,39.242425));
#1580=B_SPLINE_SURFACE_WITH_KNOTS('',1,3,((#1540,#1541,#1542,#1543,#1544,#1545,#1546,#1547,
#1548,#1549),(#1550,#1551,#1552,#1553,#1554,#1555,#1556,#1557,#1558,#1559),(#1560,#1561,#1562,
#1563,#1564,#1565,#1566,#1567,#1568,#1569),(#1570,#1571,#1572,#1573,#1574,#1575,#1576,#1577,
#1578,#1579)),.UNSPECIFIED.,.F.,.F.,.F.,(2,1,1,2),(4,2,2,2,4),(-0.01,0.,1.,1.0101),(0.,0.25,0.5,
0.75,1.),.UNSPECIFIED.);
#1581=DIRECTION('',(0.,0.,-1.));
#1582=VECTOR('',#1581,1.);
#1583=CARTESIAN_POINT('',(498.429289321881,1000.,39.25));
#1584=LINE('',#1583,#1582);
#1585=CARTESIAN_POINT('',(498.429289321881,1000.,40.));
#1586=VERTEX_POINT('',#1585);
#1587=CARTESIAN_POINT('',(498.429289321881,1000.,39.25));
#1588=VERTEX_POINT('',#1587);
#1589=EDGE_CURVE('E1638',#1586,#1588,#1584,.T.);
#1590=CARTESIAN_POINT('',(498.5,1000.75,38.5));
#1591=CARTESIAN_POINT('',(498.499263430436,1000.75000026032,38.5122718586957));
#1592=CARTESIAN_POINT('',(498.498526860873,1000.74969881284,38.524543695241));
#1593=CARTESIAN_POINT('',(498.497053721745,1000.74849437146,38.5490578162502));
#1594=CARTESIAN_POINT('',(498.496317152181,1000.74759137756,38.5613001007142));
#1595=CARTESIAN_POINT('',(498.494844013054,1000.74518571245,38.5857256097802));
#1596=CARTESIAN_POINT('',(498.49410744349,1000.74368304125,38.5979088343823));
#1597=CARTESIAN_POINT('',(498.492634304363,1000.74008172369,38.6221868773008));
#1598=CARTESIAN_POINT('',(498.491897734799,1000.73798307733,38.6342816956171));
#1599=CARTESIAN_POINT('',(498.490424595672,1000.73319484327,38.6583537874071));
#1600=CARTESIAN_POINT('',(498.489688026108,1000.73050525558,38.6703310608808));
#1601=CARTESIAN_POINT('',(498.48821488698,1000.72454162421,38.6941392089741));
#1602=CARTESIAN_POINT('',(498.487478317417,1000.72126758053,38.7059700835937));
#1603=CARTESIAN_POINT('',(498.486005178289,1000.71414292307,38.729456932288));
#1604=CARTESIAN_POINT('',(498.485268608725,1000.71029230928,38.7411129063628));
#1605=CARTESIAN_POINT('',(498.483795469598,1000.70202378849,38.7642218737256));
#1606=CARTESIAN_POINT('',(498.483058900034,1000.69760588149,38.7756748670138));
#1607=CARTESIAN_POINT('',(498.481585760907,1000.68821341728,38.7983502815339));
#1608=CARTESIAN_POINT('',(498.480849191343,1000.68323886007,38.8095727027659));
#1609=CARTESIAN_POINT('',(498.479376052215,1000.67274507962,38.8317599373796));
#1610=CARTESIAN_POINT('',(498.478639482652,1000.66722585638,38.8427247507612));
#1611=CARTESIAN_POINT('',(498.477166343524,1000.65565604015,38.8643703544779));
#1612=CARTESIAN_POINT('',(498.47642977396,1000.64960544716,38.8750511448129));
#1613=CARTESIAN_POINT('',(498.474956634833,1000.63698746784,38.896102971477));
#1614=CARTESIAN_POINT('',(498.474220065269,1000.63042008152,38.9064740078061));
#1615=CARTESIAN_POINT('',(498.472746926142,1000.61678433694,38.9268813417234));
#1616=CARTESIAN_POINT('',(498.472010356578,1000.60971597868,38.9369176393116));
#1617=CARTESIAN_POINT('',(498.470537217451,1000.59509531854,38.9566313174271));
#1618=CARTESIAN_POINT('',(498.469800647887,1000.58754301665,38.9663086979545));
#1619=CARTESIAN_POINT('',(498.468327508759,1000.57197266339,38.985281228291));
#1620=CARTESIAN_POINT('',(498.467590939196,1000.56395461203,38.9945763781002));
#1621=CARTESIAN_POINT('',(498.466117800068,1000.54747207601,39.0127620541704));
#1622=CARTESIAN_POINT('',(498.465381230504,1000.53900759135,39.0216525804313));
#1623=CARTESIAN_POINT('',(498.463908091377,1000.52165258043,39.0390075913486));
#1624=CARTESIAN_POINT('',(498.463171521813,1000.51276205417,39.0474720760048));
#1625=CARTESIAN_POINT('',(498.461698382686,1000.4945763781,39.0639546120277));
#1626=CARTESIAN_POINT('',(498.460961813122,1000.48528122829,39.0719726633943));
#1627=CARTESIAN_POINT('',(498.459488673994,1000.46630869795,39.0875430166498));
#1628=CARTESIAN_POINT('',(498.458752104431,1000.45663131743,39.0950953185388));
#1629=CARTESIAN_POINT('',(498.457278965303,1000.43691763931,39.1097159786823));
#1630=CARTESIAN_POINT('',(498.45654239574,1000.42688134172,39.1167843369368));
#1631=CARTESIAN_POINT('',(498.455069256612,1000.40647400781,39.1304200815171));
#1632=CARTESIAN_POINT('',(498.454332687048,1000.39610297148,39.1369874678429));
#1633=CARTESIAN_POINT('',(498.452859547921,1000.37505114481,39.1496054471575));
#1634=CARTESIAN_POINT('',(498.452122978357,1000.36437035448,39.1556560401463));
#1635=CARTESIAN_POINT('',(498.45064983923,1000.34272475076,39.1672258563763));
#1636=CARTESIAN_POINT('',(498.449913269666,1000.33175993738,39.1727450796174));
#1637=CARTESIAN_POINT('',(498.448440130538,1000.30957270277,39.1832388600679));
#1638=CARTESIAN_POINT('',(498.447703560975,1000.29835028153,39.1882134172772));
#1639=CARTESIAN_POINT('',(498.446230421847,1000.27567486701,39.1976058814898));
#1640=CARTESIAN_POINT('',(498.445493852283,1000.26422187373,39.202023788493));
#1641=CARTESIAN_POINT('',(498.444020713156,1000.24111290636,39.2102923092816));
#1642=CARTESIAN_POINT('',(498.443284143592,1000.22945693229,39.2141429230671));
#1643=CARTESIAN_POINT('',(498.441811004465,1000.20597008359,39.2212675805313));
#1644=CARTESIAN_POINT('',(498.441074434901,1000.19413920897,39.2245416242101));
#1645=CARTESIAN_POINT('',(498.439601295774,1000.17033106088,39.2305052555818));
#1646=CARTESIAN_POINT('',(498.43886472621,1000.15835378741,39.2331948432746));
#1647=CARTESIAN_POINT('',(498.437391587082,1000.13428169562,39.2379830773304));
#1648=CARTESIAN_POINT('',(498.436655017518,1000.1221868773,39.2400817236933));
#1649=CARTESIAN_POINT('',(498.435181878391,1000.09790883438,39.243683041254));
#1650=CARTESIAN_POINT('',(498.434445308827,1000.08572560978,39.2451857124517));
#1651=CARTESIAN_POINT('',(498.4329721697,1000.06130010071,39.2475913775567));
#1652=CARTESIAN_POINT('',(498.432235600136,1000.04905781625,39.2484943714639));
#1653=CARTESIAN_POINT('',(498.430762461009,1000.02454369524,39.2496988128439));
#1654=CARTESIAN_POINT('',(498.430025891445,1000.0122718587,39.2500002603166));
#1655=CARTESIAN_POINT('',(498.429289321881,1000.,39.25));
#1656=B_SPLINE_CURVE_WITH_KNOTS('',3,(#1590,#1591,#1592,#1593,#1594,#1595,#1596,#1597,#1598,
#1599,#1600,#1601,#1602,#1603,#1604,#1605,#1606,#1607,#1608,#1609,#1610,#1611,#1612,#1613,#1614,
#1615,#1616,#1617,#1618,#1619,#1620,#1621,#1622,#1623,#1624,#1625,#1626,#1627,#1628,#1629,#1630,
#1631,#1632,#1633,#1634,#1635,#1636,#1637,#1638,#1639,#1640,#1641,#1642,#1643,#1644,#1645,#1646,
#1647,#1648,#1649,#1650,#1651,#1652,#1653,#1654,#1655),.UNSPECIFIED.,.F.,.F.,(4,2,2,2,2,2,2,2,2,
2,2,2,2,2,2,2,2,2,2,2,2,2,2,2,2,2,2,2,2,2,2,2,4),(0.,0.0368781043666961,0.0737562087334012,
0.110634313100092,0.14751241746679,0.184390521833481,0.221268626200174,0.258146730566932,
0.295024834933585,0.331902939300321,0.368781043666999,0.405659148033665,0.442537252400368,
0.479415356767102,0.51629346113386,0.55317156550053,0.59004966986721,0.626927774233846,
0.663805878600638,0.70068398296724,0.737562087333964,0.774440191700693,0.811318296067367,
0.848196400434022,0.885074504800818,0.921952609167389,0.958830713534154,0.995708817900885,
1.03258692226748,1.06946502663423,1.10634313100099,1.14322123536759,1.18009933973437),.UNSPECIFIED.);
#1657=EDGE_CURVE('E874',#909,#1588,#1656,.T.);
#1658=CARTESIAN_POINT('',(498.5,1001.5,38.5));
#1659=CARTESIAN_POINT('',(498.499263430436,1001.50000052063,38.5245437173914));
#1660=CARTESIAN_POINT('',(498.498526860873,1001.49939762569,38.5490873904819));
#1661=CARTESIAN_POINT('',(498.497053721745,1001.49698874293,38.5981156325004));
#1662=CARTESIAN_POINT('',(498.496317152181,1001.49518275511,38.6226002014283));
#1663=CARTESIAN_POINT('',(498.494844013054,1001.4903714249,38.6714512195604));
#1664=CARTESIAN_POINT('',(498.49410744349,1001.48736608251,38.6958176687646));
#1665=CARTESIAN_POINT('',(498.492634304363,1001.48016344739,38.7443737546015));
#1666=CARTESIAN_POINT('',(498.491897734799,1001.47596615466,38.7685633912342));
#1667=CARTESIAN_POINT('',(498.490424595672,1001.46638968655,38.8167075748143));
#1668=CARTESIAN_POINT('',(498.489688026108,1001.46101051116,38.8406621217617));
#1669=CARTESIAN_POINT('',(498.48821488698,1001.44908324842,38.8882784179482));
#1670=CARTESIAN_POINT('',(498.487478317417,1001.44253516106,38.9119401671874));
#1671=CARTESIAN_POINT('',(498.486005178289,1001.42828584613,38.9589138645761));
#1672=CARTESIAN_POINT('',(498.485268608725,1001.42058461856,38.9822258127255));
#1673=CARTESIAN_POINT('',(498.483795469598,1001.40404757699,39.0284437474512));
#1674=CARTESIAN_POINT('',(498.483058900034,1001.39521176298,39.0513497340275));
#1675=CARTESIAN_POINT('',(498.481585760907,1001.37642683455,39.0967005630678));
#1676=CARTESIAN_POINT('',(498.480849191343,1001.36647772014,39.1191454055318));
#1677=CARTESIAN_POINT('',(498.479376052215,1001.34549015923,39.1635198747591));
#1678=CARTESIAN_POINT('',(498.478639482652,1001.33445171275,39.1854495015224));
#1679=CARTESIAN_POINT('',(498.477166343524,1001.31131208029,39.2287407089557));
#1680=CARTESIAN_POINT('',(498.47642977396,1001.29921089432,39.2501022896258));
#1681=CARTESIAN_POINT('',(498.474956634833,1001.27397493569,39.292205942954));
#1682=CARTESIAN_POINT('',(498.474220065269,1001.26084016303,39.3129480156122));
#1683=CARTESIAN_POINT('',(498.472746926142,1001.23356867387,39.3537626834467));
#1684=CARTESIAN_POINT('',(498.472010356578,1001.21943195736,39.3738352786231));
#1685=CARTESIAN_POINT('',(498.470537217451,1001.19019063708,39.4132626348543));
#1686=CARTESIAN_POINT('',(498.469800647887,1001.1750860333,39.432617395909));
#1687=CARTESIAN_POINT('',(498.468327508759,1001.14394532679,39.4705624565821));
#1688=CARTESIAN_POINT('',(498.467590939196,1001.12790922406,39.4891527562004));
#1689=CARTESIAN_POINT('',(498.466117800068,1001.09494415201,39.5255241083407));
#1690=CARTESIAN_POINT('',(498.465381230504,1001.0780151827,39.5433051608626));
#1691=CARTESIAN_POINT('',(498.463908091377,1001.04330516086,39.5780151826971));
#1692=CARTESIAN_POINT('',(498.463171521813,1001.02552410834,39.5949441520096));
#1693=CARTESIAN_POINT('',(498.461698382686,1000.9891527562,39.6279092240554));
#1694=CARTESIAN_POINT('',(498.460961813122,1000.97056245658,39.6439453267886));
#1695=CARTESIAN_POINT('',(498.459488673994,1000.93261739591,39.6750860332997));
#1696=CARTESIAN_POINT('',(498.458752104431,1000.91326263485,39.6901906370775));
#1697=CARTESIAN_POINT('',(498.457278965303,1000.87383527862,39.7194319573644));
#1698=CARTESIAN_POINT('',(498.45654239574,1000.85376268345,39.7335686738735));
#1699=CARTESIAN_POINT('',(498.455069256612,1000.81294801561,39.7608401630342));
#1700=CARTESIAN_POINT('',(498.454332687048,1000.79220594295,39.7739749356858));
#1701=CARTESIAN_POINT('',(498.452859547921,1000.75010228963,39.7992108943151));
#1702=CARTESIAN_POINT('',(498.452122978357,1000.72874070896,39.8113120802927));
#1703=CARTESIAN_POINT('',(498.45064983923,1000.68544950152,39.8344517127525));
#1704=CARTESIAN_POINT('',(498.449913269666,1000.66351987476,39.8454901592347));
#1705=CARTESIAN_POINT('',(498.448440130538,1000.61914540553,39.8664777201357));
#1706=CARTESIAN_POINT('',(498.447703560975,1000.59670056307,39.8764268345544));
#1707=CARTESIAN_POINT('',(498.446230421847,1000.55134973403,39.8952117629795));
#1708=CARTESIAN_POINT('',(498.445493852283,1000.52844374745,39.9040475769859));
#1709=CARTESIAN_POINT('',(498.444020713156,1000.48222581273,39.9205846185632));
#1710=CARTESIAN_POINT('',(498.443284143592,1000.45891386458,39.9282858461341));
#1711=CARTESIAN_POINT('',(498.441811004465,1000.41194016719,39.9425351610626));
#1712=CARTESIAN_POINT('',(498.441074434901,1000.38827841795,39.9490832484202));
#1713=CARTESIAN_POINT('',(498.439601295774,1000.34066212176,39.9610105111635));
#1714=CARTESIAN_POINT('',(498.43886472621,1000.31670757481,39.9663896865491));
#1715=CARTESIAN_POINT('',(498.437391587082,1000.26856339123,39.9759661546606));
#1716=CARTESIAN_POINT('',(498.436655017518,1000.2443737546,39.9801634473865));
#1717=CARTESIAN_POINT('',(498.435181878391,1000.19581766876,39.9873660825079));
#1718=CARTESIAN_POINT('',(498.434445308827,1000.17145121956,39.9903714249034));
#1719=CARTESIAN_POINT('',(498.4329721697,1000.12260020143,39.9951827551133));
#1720=CARTESIAN_POINT('',(498.432235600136,1000.0981156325,39.9969887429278));
#1721=CARTESIAN_POINT('',(498.430762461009,1000.04908739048,39.9993976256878));
#1722=CARTESIAN_POINT('',(498.430025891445,1000.02454371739,40.0000005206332));
#1723=CARTESIAN_POINT('',(498.429289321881,1000.,40.));
#1724=B_SPLINE_CURVE_WITH_KNOTS('',3,(#1658,#1659,#1660,#1661,#1662,#1663,#1664,#1665,#1666,
#1667,#1668,#1669,#1670,#1671,#1672,#1673,#1674,#1675,#1676,#1677,#1678,#1679,#1680,#1681,#1682,
#1683,#1684,#1685,#1686,#1687,#1688,#1689,#1690,#1691,#1692,#1693,#1694,#1695,#1696,#1697,#1698,
#1699,#1700,#1701,#1702,#1703,#1704,#1705,#1706,#1707,#1708,#1709,#1710,#1711,#1712,#1713,#1714,
#1715,#1716,#1717,#1718,#1719,#1720,#1721,#1722,#1723),.UNSPECIFIED.,.F.,.F.,(4,2,2,2,2,2,2,2,2,
2,2,2,2,2,2,2,2,2,2,2,2,2,2,2,2,2,2,2,2,2,2,2,4),(0.,0.0736568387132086,0.147313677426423,
0.220970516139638,0.294627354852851,0.368284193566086,0.441941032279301,0.515597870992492,
0.589254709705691,0.662911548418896,0.736568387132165,0.810225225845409,0.883882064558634,
0.957538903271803,1.03119574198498,1.10485258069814,1.17850941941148,1.25216625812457,
1.32582309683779,1.39947993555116,1.47313677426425,1.54679361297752,1.62045045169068,
1.69410729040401,1.76776412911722,1.84142096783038,1.91507780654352,1.9887346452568,
2.06239148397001,2.13604832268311,2.20970516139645,2.2833620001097,2.35701883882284),.UNSPECIFIED.);
#1725=EDGE_CURVE('E884',#918,#1586,#1724,.T.);
#1726=ORIENTED_EDGE('',*,*,#1589,.T.);
#1727=ORIENTED_EDGE('',*,*,#1657,.F.);
#1728=ORIENTED_EDGE('',*,*,#925,.F.);
#1729=ORIENTED_EDGE('',*,*,#1725,.T.);
#1730=EDGE_LOOP('',(#1726,#1727,#1728,#1729));
#1731=FACE_BOUND('',#1730,.T.);
#1732=ADVANCED_FACE('F1619',(#1731),#1580,.F.);
#1733=CARTESIAN_POINT('',(1.57071067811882,1000.,40.0075));
#1734=CARTESIAN_POINT('',(1.56481706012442,1000.19736683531,40.0075));
#1735=CARTESIAN_POINT('',(1.55892556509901,1000.39458493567,39.9682638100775));
#1736=CARTESIAN_POINT('',(1.5471404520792,1000.75920561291,39.8172329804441));
#1737=CARTESIAN_POINT('',(1.5412478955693,1000.92642918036,39.7054977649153));
#1738=CARTESIAN_POINT('',(1.52946278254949,1001.20549776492,39.4264291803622));
#1739=CARTESIAN_POINT('',(1.52357022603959,1001.31723298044,39.2592056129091));
#1740=CARTESIAN_POINT('',(1.51178511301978,1001.46826381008,38.8945849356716));
#1741=CARTESIAN_POINT('',(1.50589361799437,1001.5075,38.6973668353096));
#1742=CARTESIAN_POINT('',(1.49999999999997,1001.5075,38.5));
#1743=CARTESIAN_POINT('',(1.57071067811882,1000.,40.));
#1744=CARTESIAN_POINT('',(1.56481706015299,1000.19638491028,40.));
#1745=CARTESIAN_POINT('',(1.55892556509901,1000.39262182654,39.9609590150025));
#1746=CARTESIAN_POINT('',(1.5471404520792,1000.75542847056,39.8106795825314));
#1747=CARTESIAN_POINT('',(1.5412478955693,1000.92182007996,39.6995002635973));
#1748=CARTESIAN_POINT('',(1.52946278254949,1001.1995002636,39.4218200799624));
#1749=CARTESIAN_POINT('',(1.52357022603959,1001.31067958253,39.2554284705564));
#1750=CARTESIAN_POINT('',(1.51178511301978,1001.460959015,38.8926218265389));
#1751=CARTESIAN_POINT('',(1.50589361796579,1001.5,38.696384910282));
#1752=CARTESIAN_POINT('',(1.49999999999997,1001.5,38.5));
#1753=CARTESIAN_POINT('',(1.57071067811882,1000.,39.25));
#1754=CARTESIAN_POINT('',(1.56481706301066,1000.09819240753,39.25));
#1755=CARTESIAN_POINT('',(1.55892556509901,1000.19631091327,39.2304795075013));
#1756=CARTESIAN_POINT('',(1.5471404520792,1000.37771423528,39.1553397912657));
#1757=CARTESIAN_POINT('',(1.5412478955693,1000.46091003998,39.0997501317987));
#1758=CARTESIAN_POINT('',(1.52946278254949,1000.5997501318,38.9609100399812));
#1759=CARTESIAN_POINT('',(1.52357022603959,1000.65533979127,38.8777142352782));
#1760=CARTESIAN_POINT('',(1.51178511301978,1000.7304795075,38.6963109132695));
#1761=CARTESIAN_POINT('',(1.50589361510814,1000.75,38.5981924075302));
#1762=CARTESIAN_POINT('',(1.49999999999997,1000.75,38.5));
#1763=CARTESIAN_POINT('',(1.57071067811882,1000.,39.242425));
#1764=CARTESIAN_POINT('',(1.56481706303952,1000.09720066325,39.242425));
#1765=CARTESIAN_POINT('',(1.55892556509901,1000.19432817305,39.2231016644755));
#1766=CARTESIAN_POINT('',(1.5471404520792,1000.3738993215,39.1487208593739));
#1767=CARTESIAN_POINT('',(1.5412478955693,1000.45625484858,39.0936926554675));
#1768=CARTESIAN_POINT('',(1.52946278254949,1000.59369265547,38.9562548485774));
#1769=CARTESIAN_POINT('',(1.52357022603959,1000.64872085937,38.8738993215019));
#1770=CARTESIAN_POINT('',(1.51178511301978,1000.72310166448,38.6943281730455));
#1771=CARTESIAN_POINT('',(1.50589361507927,1000.742425,38.5972006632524));
#1772=CARTESIAN_POINT('',(1.49999999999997,1000.742425,38.5));
#1773=B_SPLINE_SURFACE_WITH_KNOTS('',1,3,((#1733,#1734,#1735,#1736,#1737,#1738,#1739,#1740,
#1741,#1742),(#1743,#1744,#1745,#1746,#1747,#1748,#1749,#1750,#1751,#1752),(#1753,#1754,#1755,
#1756,#1757,#1758,#1759,#1760,#1761,#1762),(#1763,#1764,#1765,#1766,#1767,#1768,#1769,#1770,
#1771,#1772)),.UNSPECIFIED.,.F.,.F.,.F.,(2,1,1,2),(4,2,2,2,4),(-0.01,0.,1.,1.0101),(0.,0.25,0.5,
0.75,1.),.UNSPECIFIED.);
#1774=CARTESIAN_POINT('',(1.57071067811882,1000.,39.25));
#1775=CARTESIAN_POINT('',(1.56997410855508,1000.0122718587,39.2500002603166));
#1776=CARTESIAN_POINT('',(1.56923753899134,1000.02454369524,39.2496988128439));
#1777=CARTESIAN_POINT('',(1.56776439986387,1000.04905781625,39.2484943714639));
#1778=CARTESIAN_POINT('',(1.56702783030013,1000.06130010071,39.2475913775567));
#1779=CARTESIAN_POINT('',(1.56555469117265,1000.08572560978,39.2451857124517));
#1780=CARTESIAN_POINT('',(1.56481812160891,1000.09790883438,39.243683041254));
#1781=CARTESIAN_POINT('',(1.56334498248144,1000.1221868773,39.2400817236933));
#1782=CARTESIAN_POINT('',(1.5626084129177,1000.13428169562,39.2379830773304));
#1783=CARTESIAN_POINT('',(1.56113527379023,1000.15835378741,39.2331948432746));
#1784=CARTESIAN_POINT('',(1.56039870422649,1000.17033106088,39.2305052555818));
#1785=CARTESIAN_POINT('',(1.55892556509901,1000.19413920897,39.2245416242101));
#1786=CARTESIAN_POINT('',(1.55818899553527,1000.20597008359,39.2212675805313));
#1787=CARTESIAN_POINT('',(1.5567158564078,1000.22945693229,39.2141429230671));
#1788=CARTESIAN_POINT('',(1.55597928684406,1000.24111290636,39.2102923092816));
#1789=CARTESIAN_POINT('',(1.55450614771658,1000.26422187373,39.202023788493));
#1790=CARTESIAN_POINT('',(1.55376957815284,1000.27567486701,39.1976058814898));
#1791=CARTESIAN_POINT('',(1.55229643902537,1000.29835028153,39.1882134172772));
#1792=CARTESIAN_POINT('',(1.55155986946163,1000.30957270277,39.1832388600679));
#1793=CARTESIAN_POINT('',(1.55008673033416,1000.33175993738,39.1727450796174));
#1794=CARTESIAN_POINT('',(1.54935016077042,1000.34272475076,39.1672258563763));
#1795=CARTESIAN_POINT('',(1.54787702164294,1000.36437035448,39.1556560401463));
#1796=CARTESIAN_POINT('',(1.5471404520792,1000.37505114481,39.1496054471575));
#1797=CARTESIAN_POINT('',(1.54566731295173,1000.39610297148,39.1369874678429));
#1798=CARTESIAN_POINT('',(1.54493074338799,1000.40647400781,39.1304200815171));
#1799=CARTESIAN_POINT('',(1.54345760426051,1000.42688134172,39.1167843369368));
#1800=CARTESIAN_POINT('',(1.54272103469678,1000.43691763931,39.1097159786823));
#1801=CARTESIAN_POINT('',(1.5412478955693,1000.45663131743,39.0950953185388));
#1802=CARTESIAN_POINT('',(1.54051132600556,1000.46630869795,39.0875430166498));
#1803=CARTESIAN_POINT('',(1.53903818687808,1000.48528122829,39.0719726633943));
#1804=CARTESIAN_POINT('',(1.53830161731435,1000.4945763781,39.0639546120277));
#1805=CARTESIAN_POINT('',(1.53682847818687,1000.51276205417,39.0474720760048));
#1806=CARTESIAN_POINT('',(1.53609190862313,1000.52165258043,39.0390075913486));
#1807=CARTESIAN_POINT('',(1.53461876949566,1000.53900759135,39.0216525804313));
#1808=CARTESIAN_POINT('',(1.53388219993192,1000.54747207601,39.0127620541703));
#1809=CARTESIAN_POINT('',(1.53240906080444,1000.56395461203,38.9945763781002));
#1810=CARTESIAN_POINT('',(1.53167249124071,1000.57197266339,38.9852812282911));
#1811=CARTESIAN_POINT('',(1.53019935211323,1000.58754301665,38.9663086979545));
#1812=CARTESIAN_POINT('',(1.52946278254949,1000.59509531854,38.9566313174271));
#1813=CARTESIAN_POINT('',(1.52798964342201,1000.60971597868,38.9369176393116));
#1814=CARTESIAN_POINT('',(1.52725307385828,1000.61678433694,38.9268813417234));
#1815=CARTESIAN_POINT('',(1.5257799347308,1000.63042008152,38.9064740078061));
#1816=CARTESIAN_POINT('',(1.52504336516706,1000.63698746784,38.896102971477));
#1817=CARTESIAN_POINT('',(1.52357022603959,1000.64960544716,38.8750511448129));
#1818=CARTESIAN_POINT('',(1.52283365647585,1000.65565604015,38.8643703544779));
#1819=CARTESIAN_POINT('',(1.52136051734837,1000.66722585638,38.8427247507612));
#1820=CARTESIAN_POINT('',(1.52062394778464,1000.67274507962,38.8317599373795));
#1821=CARTESIAN_POINT('',(1.51915080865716,1000.68323886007,38.8095727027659));
#1822=CARTESIAN_POINT('',(1.51841423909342,1000.68821341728,38.7983502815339));
#1823=CARTESIAN_POINT('',(1.51694109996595,1000.69760588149,38.7756748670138));
#1824=CARTESIAN_POINT('',(1.51620453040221,1000.70202378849,38.7642218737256));
#1825=CARTESIAN_POINT('',(1.51473139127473,1000.71029230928,38.7411129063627));
#1826=CARTESIAN_POINT('',(1.51399482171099,1000.71414292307,38.729456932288));
#1827=CARTESIAN_POINT('',(1.51252168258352,1000.72126758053,38.7059700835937));
#1828=CARTESIAN_POINT('',(1.51178511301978,1000.72454162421,38.6941392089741));
#1829=CARTESIAN_POINT('',(1.5103119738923,1000.73050525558,38.6703310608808));
#1830=CARTESIAN_POINT('',(1.50957540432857,1000.73319484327,38.6583537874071));
#1831=CARTESIAN_POINT('',(1.50810226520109,1000.73798307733,38.6342816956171));
#1832=CARTESIAN_POINT('',(1.50736569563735,1000.74008172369,38.6221868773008));
#1833=CARTESIAN_POINT('',(1.50589255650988,1000.74368304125,38.5979088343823));
#1834=CARTESIAN_POINT('',(1.50515598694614,1000.74518571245,38.5857256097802));
#1835=CARTESIAN_POINT('',(1.50368284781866,1000.74759137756,38.5613001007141));
#1836=CARTESIAN_POINT('',(1.50294627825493,1000.74849437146,38.5490578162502));
#1837=CARTESIAN_POINT('',(1.50147313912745,1000.74969881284,38.524543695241));
#1838=CARTESIAN_POINT('',(1.50073656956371,1000.75000026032,38.5122718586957));
#1839=CARTESIAN_POINT('',(1.49999999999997,1000.75,38.5));
#1840=B_SPLINE_CURVE_WITH_KNOTS('',3,(#1774,#1775,#1776,#1777,#1778,#1779,#1780,#1781,#1782,
#1783,#1784,#1785,#1786,#1787,#1788,#1789,#1790,#1791,#1792,#1793,#1794,#1795,#1796,#1797,#1798,
#1799,#1800,#1801,#1802,#1803,#1804,#1805,#1806,#1807,#1808,#1809,#1810,#1811,#1812,#1813,#1814,
#1815,#1816,#1817,#1818,#1819,#1820,#1821,#1822,#1823,#1824,#1825,#1826,#1827,#1828,#1829,#1830,
#1831,#1832,#1833,#1834,#1835,#1836,#1837,#1838,#1839),.UNSPECIFIED.,.F.,.F.,(4,2,2,2,2,2,2,2,2,
2,2,2,2,2,2,2,2,2,2,2,2,2,2,2,2,2,2,2,2,2,2,2,4),(0.,0.0368781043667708,0.073756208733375,
0.110634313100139,0.147512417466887,0.184390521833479,0.221268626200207,0.258146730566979,
0.295024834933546,0.331902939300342,0.368781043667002,0.405659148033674,0.442537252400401,
0.479415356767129,0.51629346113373,0.55317156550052,0.590049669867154,0.626927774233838,
0.663805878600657,0.70068398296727,0.737562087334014,0.774440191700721,0.81131829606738,
0.848196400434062,0.885074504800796,0.921952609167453,0.95883071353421,0.995708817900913,
1.0325869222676,1.0694650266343,1.10634313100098,1.14322123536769,1.18009933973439),.UNSPECIFIED.);
#1841=CARTESIAN_POINT('',(1.57071067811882,1000.,39.25));
#1842=VERTEX_POINT('',#1841);
#1843=EDGE_CURVE('E879',#1842,#887,#1840,.T.);
#1844=DIRECTION('',(0.,0.,1.));
#1845=VECTOR('',#1844,1.);
#1846=CARTESIAN_POINT('',(1.57071067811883,1000.,39.25));
#1847=LINE('',#1846,#1845);
#1848=CARTESIAN_POINT('',(1.57071067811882,1000.,40.));
#1849=VERTEX_POINT('',#1848);
#1850=EDGE_CURVE('E883',#1849,#1842,#1847,.F.);
#1851=CARTESIAN_POINT('',(1.57071067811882,1000.,40.));
#1852=CARTESIAN_POINT('',(1.56997410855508,1000.02454371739,40.0000005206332));
#1853=CARTESIAN_POINT('',(1.56923753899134,1000.04908739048,39.9993976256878));
#1854=CARTESIAN_POINT('',(1.56776439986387,1000.0981156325,39.9969887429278));
#1855=CARTESIAN_POINT('',(1.56702783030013,1000.12260020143,39.9951827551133));
#1856=CARTESIAN_POINT('',(1.56555469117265,1000.17145121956,39.9903714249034));
#1857=CARTESIAN_POINT('',(1.56481812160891,1000.19581766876,39.9873660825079));
#1858=CARTESIAN_POINT('',(1.56334498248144,1000.2443737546,39.9801634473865));
#1859=CARTESIAN_POINT('',(1.5626084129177,1000.26856339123,39.9759661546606));
#1860=CARTESIAN_POINT('',(1.56113527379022,1000.31670757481,39.9663896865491));
#1861=CARTESIAN_POINT('',(1.56039870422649,1000.34066212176,39.9610105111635));
#1862=CARTESIAN_POINT('',(1.55892556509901,1000.38827841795,39.9490832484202));
#1863=CARTESIAN_POINT('',(1.55818899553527,1000.41194016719,39.9425351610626));
#1864=CARTESIAN_POINT('',(1.5567158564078,1000.45891386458,39.9282858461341));
#1865=CARTESIAN_POINT('',(1.55597928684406,1000.48222581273,39.9205846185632));
#1866=CARTESIAN_POINT('',(1.55450614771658,1000.52844374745,39.9040475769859));
#1867=CARTESIAN_POINT('',(1.55376957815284,1000.55134973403,39.8952117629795));
#1868=CARTESIAN_POINT('',(1.55229643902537,1000.59670056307,39.8764268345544));
#1869=CARTESIAN_POINT('',(1.55155986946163,1000.61914540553,39.8664777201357));
#1870=CARTESIAN_POINT('',(1.55008673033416,1000.66351987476,39.8454901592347));
#1871=CARTESIAN_POINT('',(1.54935016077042,1000.68544950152,39.8344517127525));
#1872=CARTESIAN_POINT('',(1.54787702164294,1000.72874070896,39.8113120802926));
#1873=CARTESIAN_POINT('',(1.5471404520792,1000.75010228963,39.799210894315));
#1874=CARTESIAN_POINT('',(1.54566731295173,1000.79220594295,39.7739749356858));
#1875=CARTESIAN_POINT('',(1.54493074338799,1000.81294801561,39.7608401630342));
#1876=CARTESIAN_POINT('',(1.54345760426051,1000.85376268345,39.7335686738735));
#1877=CARTESIAN_POINT('',(1.54272103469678,1000.87383527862,39.7194319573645));
#1878=CARTESIAN_POINT('',(1.5412478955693,1000.91326263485,39.6901906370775));
#1879=CARTESIAN_POINT('',(1.54051132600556,1000.93261739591,39.6750860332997));
#1880=CARTESIAN_POINT('',(1.53903818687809,1000.97056245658,39.6439453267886));
#1881=CARTESIAN_POINT('',(1.53830161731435,1000.9891527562,39.6279092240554));
#1882=CARTESIAN_POINT('',(1.53682847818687,1001.02552410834,39.5949441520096));
#1883=CARTESIAN_POINT('',(1.53609190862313,1001.04330516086,39.578015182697));
#1884=CARTESIAN_POINT('',(1.53461876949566,1001.0780151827,39.5433051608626));
#1885=CARTESIAN_POINT('',(1.53388219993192,1001.09494415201,39.5255241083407));
#1886=CARTESIAN_POINT('',(1.53240906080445,1001.12790922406,39.4891527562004));
#1887=CARTESIAN_POINT('',(1.53167249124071,1001.14394532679,39.470562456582));
#1888=CARTESIAN_POINT('',(1.53019935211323,1001.1750860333,39.4326173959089));
#1889=CARTESIAN_POINT('',(1.52946278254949,1001.19019063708,39.4132626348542));
#1890=CARTESIAN_POINT('',(1.52798964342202,1001.21943195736,39.3738352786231));
#1891=CARTESIAN_POINT('',(1.52725307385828,1001.23356867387,39.3537626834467));
#1892=CARTESIAN_POINT('',(1.5257799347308,1001.26084016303,39.3129480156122));
#1893=CARTESIAN_POINT('',(1.52504336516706,1001.27397493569,39.292205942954));
#1894=CARTESIAN_POINT('',(1.52357022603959,1001.29921089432,39.2501022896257));
#1895=CARTESIAN_POINT('',(1.52283365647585,1001.31131208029,39.2287407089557));
#1896=CARTESIAN_POINT('',(1.52136051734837,1001.33445171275,39.1854495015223));
#1897=CARTESIAN_POINT('',(1.52062394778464,1001.34549015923,39.1635198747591));
#1898=CARTESIAN_POINT('',(1.51915080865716,1001.36647772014,39.1191454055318));
#1899=CARTESIAN_POINT('',(1.51841423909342,1001.37642683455,39.0967005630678));
#1900=CARTESIAN_POINT('',(1.51694109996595,1001.39521176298,39.0513497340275));
#1901=CARTESIAN_POINT('',(1.51620453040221,1001.40404757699,39.0284437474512));
#1902=CARTESIAN_POINT('',(1.51473139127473,1001.42058461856,38.9822258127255));
#1903=CARTESIAN_POINT('',(1.51399482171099,1001.42828584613,38.958913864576));
#1904=CARTESIAN_POINT('',(1.51252168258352,1001.44253516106,38.9119401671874));
#1905=CARTESIAN_POINT('',(1.51178511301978,1001.44908324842,38.8882784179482));
#1906=CARTESIAN_POINT('',(1.5103119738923,1001.46101051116,38.8406621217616));
#1907=CARTESIAN_POINT('',(1.50957540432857,1001.46638968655,38.8167075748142));
#1908=CARTESIAN_POINT('',(1.50810226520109,1001.47596615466,38.7685633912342));
#1909=CARTESIAN_POINT('',(1.50736569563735,1001.48016344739,38.7443737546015));
#1910=CARTESIAN_POINT('',(1.50589255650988,1001.48736608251,38.6958176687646));
#1911=CARTESIAN_POINT('',(1.50515598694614,1001.4903714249,38.6714512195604));
#1912=CARTESIAN_POINT('',(1.50368284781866,1001.49518275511,38.6226002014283));
#1913=CARTESIAN_POINT('',(1.50294627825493,1001.49698874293,38.5981156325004));
#1914=CARTESIAN_POINT('',(1.50147313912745,1001.49939762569,38.5490873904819));
#1915=CARTESIAN_POINT('',(1.50073656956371,1001.50000052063,38.5245437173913));
#1916=CARTESIAN_POINT('',(1.49999999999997,1001.5,38.5));
#1917=B_SPLINE_CURVE_WITH_KNOTS('',3,(#1851,#1852,#1853,#1854,#1855,#1856,#1857,#1858,#1859,
#1860,#1861,#1862,#1863,#1864,#1865,#1866,#1867,#1868,#1869,#1870,#1871,#1872,#1873,#1874,#1875,
#1876,#1877,#1878,#1879,#1880,#1881,#1882,#1883,#1884,#1885,#1886,#1887,#1888,#1889,#1890,#1891,
#1892,#1893,#1894,#1895,#1896,#1897,#1898,#1899,#1900,#1901,#1902,#1903,#1904,#1905,#1906,#1907,
#1908,#1909,#1910,#1911,#1912,#1913,#1914,#1915,#1916),.UNSPECIFIED.,.F.,.F.,(4,2,2,2,2,2,2,2,2,
2,2,2,2,2,2,2,2,2,2,2,2,2,2,2,2,2,2,2,2,2,2,2,4),(0.,0.0736568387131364,0.147313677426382,
0.220970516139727,0.294627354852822,0.368284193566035,0.441941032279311,0.515597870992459,
0.589254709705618,0.662911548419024,0.736568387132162,0.810225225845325,0.883882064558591,
0.957538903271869,1.03119574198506,1.10485258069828,1.17850941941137,1.25216625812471,
1.32582309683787,1.39947993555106,1.47313677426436,1.54679361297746,1.62045045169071,
1.69410729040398,1.76776412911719,1.84142096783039,1.91507780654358,1.9887346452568,
2.06239148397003,2.13604832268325,2.20970516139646,2.28336200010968,2.3570188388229),.UNSPECIFIED.);
#1918=EDGE_CURVE('E886',#1849,#878,#1917,.T.);
#1919=ORIENTED_EDGE('',*,*,#1843,.F.);
#1920=ORIENTED_EDGE('',*,*,#1850,.F.);
#1921=ORIENTED_EDGE('',*,*,#1918,.T.);
#1922=ORIENTED_EDGE('',*,*,#894,.T.);
#1923=EDGE_LOOP('',(#1919,#1920,#1921,#1922));
#1924=FACE_BOUND('',#1923,.T.);
#1925=ADVANCED_FACE('F869',(#1924),#1773,.F.);
#1926=CARTESIAN_POINT('',(1.49999999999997,1000.,38.5));
#1927=DIRECTION('',(-1.,0.,0.));
#1928=DIRECTION('',(0.,0.,1.));
#1929=AXIS2_PLACEMENT_3D('',#1926,#1927,#1928);
#1930=CYLINDRICAL_SURFACE('',#1929,1.50000000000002);
#1931=ORIENTED_EDGE('',*,*,#942,.T.);
#1932=ORIENTED_EDGE('',*,*,#1918,.F.);
#1933=DIRECTION('',(-1.,0.,0.));
#1934=VECTOR('',#1933,1.);
#1935=CARTESIAN_POINT('',(498.5,1000.,40.));
#1936=LINE('',#1935,#1934);
#1937=EDGE_CURVE('E1624',#1849,#1586,#1936,.F.);
#1938=ORIENTED_EDGE('',*,*,#1937,.T.);
#1939=ORIENTED_EDGE('',*,*,#1725,.F.);
#1940=EDGE_LOOP('',(#1931,#1932,#1938,#1939));
#1941=FACE_BOUND('',#1940,.T.);
#1942=ADVANCED_FACE('F867',(#1941),#1930,.T.);
#1943=CARTESIAN_POINT('',(1.49999999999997,1000.,38.5));
#1944=DIRECTION('',(-1.,0.,0.));
#1945=DIRECTION('',(0.,0.,1.));
#1946=AXIS2_PLACEMENT_3D('',#1943,#1944,#1945);
#1947=CYLINDRICAL_SURFACE('',#1946,0.750000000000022);
#1948=ORIENTED_EDGE('',*,*,#958,.F.);
#1949=ORIENTED_EDGE('',*,*,#1657,.T.);
#1950=DIRECTION('',(-1.,0.,0.));
#1951=VECTOR('',#1950,1.);
#1952=CARTESIAN_POINT('',(498.5,1000.,39.25));
#1953=LINE('',#1952,#1951);
#1954=EDGE_CURVE('E1629',#1588,#1842,#1953,.T.);
#1955=ORIENTED_EDGE('',*,*,#1954,.T.);
#1956=ORIENTED_EDGE('',*,*,#1843,.T.);
#1957=EDGE_LOOP('',(#1948,#1949,#1955,#1956));
#1958=FACE_BOUND('',#1957,.T.);
#1959=ADVANCED_FACE('F859',(#1958),#1947,.F.);
#1960=CARTESIAN_POINT('',(498.5,985.,40.0000000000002));
#1961=DIRECTION('',(0.,0.,-1.));
#1962=DIRECTION('',(0.,1.,0.));
#1963=AXIS2_PLACEMENT_3D('',#1960,#1961,#1962);
#1964=PLANE('',#1963);
#1965=DIRECTION('',(-0.70710678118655,0.707106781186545,0.));
#1966=VECTOR('',#1965,1.);
#1967=CARTESIAN_POINT('',(353.06324948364,648.507461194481,40.0000000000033));
#1968=LINE('',#1967,#1966);
#1969=CARTESIAN_POINT('',(16.5707106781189,985.,40.0000000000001));
#1970=VERTEX_POINT('',#1969);
#1971=EDGE_CURVE('E802',#1970,#1849,#1968,.T.);
#1972=ORIENTED_EDGE('',*,*,#1971,.F.);
#1973=DIRECTION('',(1.,0.,0.));
#1974=VECTOR('',#1973,1.);
#1975=CARTESIAN_POINT('',(498.5,985.,40.0000000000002));
#1976=LINE('',#1975,#1974);
#1977=CARTESIAN_POINT('',(483.429289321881,985.,40.0000000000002));
#1978=VERTEX_POINT('',#1977);
#1979=EDGE_CURVE('E1632',#1978,#1970,#1976,.F.);
#1980=ORIENTED_EDGE('',*,*,#1979,.F.);
#1981=DIRECTION('',(-0.70710678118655,-0.707106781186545,0.));
#1982=VECTOR('',#1981,1.);
#1983=CARTESIAN_POINT('',(498.429289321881,1000.,40.));
#1984=LINE('',#1983,#1982);
#1985=EDGE_CURVE('E1647',#1586,#1978,#1984,.T.);
#1986=ORIENTED_EDGE('',*,*,#1985,.F.);
#1987=ORIENTED_EDGE('',*,*,#1937,.F.);
#1988=EDGE_LOOP('',(#1972,#1980,#1986,#1987));
#1989=FACE_BOUND('',#1988,.T.);
#1990=ADVANCED_FACE('F855',(#1989),#1964,.F.);
#1991=CARTESIAN_POINT('',(498.5,985.,39.2500000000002));
#1992=DIRECTION('',(0.,0.,-1.));
#1993=DIRECTION('',(0.,1.,0.));
#1994=AXIS2_PLACEMENT_3D('',#1991,#1992,#1993);
#1995=PLANE('',#1994);
#1996=DIRECTION('',(-1.,0.,0.));
#1997=VECTOR('',#1996,1.);
#1998=CARTESIAN_POINT('',(498.5,985.,39.2500000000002));
#1999=LINE('',#1998,#1997);
#2000=CARTESIAN_POINT('',(483.429289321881,985.,39.2500000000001));
#2001=VERTEX_POINT('',#2000);
#2002=CARTESIAN_POINT('',(16.5707106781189,985.,39.2500000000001));
#2003=VERTEX_POINT('',#2002);
#2004=EDGE_CURVE('E1628',#2001,#2003,#1999,.T.);
#2005=ORIENTED_EDGE('',*,*,#2004,.T.);
#2006=DIRECTION('',(-0.70710678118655,0.707106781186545,0.));
#2007=VECTOR('',#2006,1.);
#2008=CARTESIAN_POINT('',(257.535355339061,744.03535533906,39.2500000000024));
#2009=LINE('',#2008,#2007);
#2010=EDGE_CURVE('E1649',#2003,#1842,#2009,.T.);
#2011=ORIENTED_EDGE('',*,*,#2010,.T.);
#2012=ORIENTED_EDGE('',*,*,#1954,.F.);
#2013=DIRECTION('',(-0.70710678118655,-0.707106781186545,0.));
#2014=VECTOR('',#2013,1.);
#2015=CARTESIAN_POINT('',(490.964644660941,992.53535533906,39.2500000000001));
#2016=LINE('',#2015,#2014);
#2017=EDGE_CURVE('E1634',#1588,#2001,#2016,.T.);
#2018=ORIENTED_EDGE('',*,*,#2017,.T.);
#2019=EDGE_LOOP('',(#2005,#2011,#2012,#2018));
#2020=FACE_BOUND('',#2019,.T.);
#2021=ADVANCED_FACE('F852',(#2020),#1995,.T.);
#2022=CARTESIAN_POINT('',(498.5,985.,40.0000000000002));
#2023=DIRECTION('',(0.,-1.,0.));
#2024=DIRECTION('',(0.,0.,-1.));
#2025=AXIS2_PLACEMENT_3D('',#2022,#2023,#2024);
#2026=PLANE('',#2025);
#2027=ORIENTED_EDGE('',*,*,#1979,.T.);
#2028=DIRECTION('',(0.,0.,-1.));
#2029=VECTOR('',#2028,1.);
#2030=CARTESIAN_POINT('',(16.5707106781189,985.,39.9999999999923));
#2031=LINE('',#2030,#2029);
#2032=EDGE_CURVE('E1652',#1970,#2003,#2031,.T.);
#2033=ORIENTED_EDGE('',*,*,#2032,.T.);
#2034=ORIENTED_EDGE('',*,*,#2004,.F.);
#2035=DIRECTION('',(0.,0.,1.));
#2036=VECTOR('',#2035,1.);
#2037=CARTESIAN_POINT('',(483.429289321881,985.,40.0000000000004));
#2038=LINE('',#2037,#2036);
#2039=EDGE_CURVE('E1644',#2001,#1978,#2038,.T.);
#2040=ORIENTED_EDGE('',*,*,#2039,.T.);
#2041=EDGE_LOOP('',(#2027,#2033,#2034,#2040));
#2042=FACE_BOUND('',#2041,.T.);
#2043=ADVANCED_FACE('F850',(#2042),#2026,.T.);
#2044=CARTESIAN_POINT('',(498.429289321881,1000.,40.));
#2045=DIRECTION('',(0.707106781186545,-0.70710678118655,0.));
#2046=DIRECTION('',(0.70710678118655,0.707106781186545,0.));
#2047=AXIS2_PLACEMENT_3D('',#2044,#2045,#2046);
#2048=PLANE('',#2047);
#2049=ORIENTED_EDGE('',*,*,#2017,.F.);
#2050=ORIENTED_EDGE('',*,*,#1589,.F.);
#2051=ORIENTED_EDGE('',*,*,#1985,.T.);
#2052=ORIENTED_EDGE('',*,*,#2039,.F.);
#2053=EDGE_LOOP('',(#2049,#2050,#2051,#2052));
#2054=FACE_BOUND('',#2053,.T.);
#2055=ADVANCED_FACE('F846',(#2054),#2048,.T.);
#2056=CARTESIAN_POINT('',(353.06324948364,648.507461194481,40.0000000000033));
#2057=DIRECTION('',(-0.707106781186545,-0.70710678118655,0.));
#2058=DIRECTION('',(0.70710678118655,-0.707106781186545,0.));
#2059=AXIS2_PLACEMENT_3D('',#2056,#2057,#2058);
#2060=PLANE('',#2059);
#2061=ORIENTED_EDGE('',*,*,#2010,.F.);
#2062=ORIENTED_EDGE('',*,*,#2032,.F.);
#2063=ORIENTED_EDGE('',*,*,#1971,.T.);
#2064=ORIENTED_EDGE('',*,*,#1850,.T.);
#2065=EDGE_LOOP('',(#2061,#2062,#2063,#2064));
#2066=FACE_BOUND('',#2065,.T.);
#2067=ADVANCED_FACE('F832',(#2066),#2060,.T.);
#2068=CARTESIAN_POINT('',(498.5,0.,38.5));
#2069=DIRECTION('',(0.,-1.,0.));
#2070=DIRECTION('',(0.,0.,-1.));
#2071=AXIS2_PLACEMENT_3D('',#2068,#2069,#2070);
#2072=PLANE('',#2071);
#2073=DIRECTION('',(0.,0.,1.));
#2074=VECTOR('',#2073,1.);
#2075=CARTESIAN_POINT('',(498.5,0.,40.));
#2076=LINE('',#2075,#2074);
#2077=CARTESIAN_POINT('',(498.5,0.,39.25));
#2078=VERTEX_POINT('',#2077);
#2079=CARTESIAN_POINT('',(498.5,0.,40.));
#2080=VERTEX_POINT('',#2079);
#2081=EDGE_CURVE('E771',#2078,#2080,#2076,.T.);
#2082=ORIENTED_EDGE('',*,*,#2081,.F.);
#2083=CARTESIAN_POINT('',(498.5,0.,38.5));
#2084=DIRECTION('',(0.,1.,0.));
#2085=DIRECTION('',(0.,0.,1.));
#2086=AXIS2_PLACEMENT_3D('',#2083,#2084,#2085);
#2087=CIRCLE('',#2086,0.750000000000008);
#2088=EDGE_CURVE('E795',#691,#2078,#2087,.F.);
#2089=ORIENTED_EDGE('',*,*,#2088,.F.);
#2090=ORIENTED_EDGE('',*,*,#692,.F.);
#2091=CARTESIAN_POINT('',(498.5,0.,38.5));
#2092=DIRECTION('',(0.,1.,0.));
#2093=DIRECTION('',(0.,0.,1.));
#2094=AXIS2_PLACEMENT_3D('',#2091,#2092,#2093);
#2095=CIRCLE('',#2094,1.50000000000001);
#2096=EDGE_CURVE('E799',#683,#2080,#2095,.F.);
#2097=ORIENTED_EDGE('',*,*,#2096,.T.);
#2098=EDGE_LOOP('',(#2082,#2089,#2090,#2097));
#2099=FACE_BOUND('',#2098,.T.);
#2100=ADVANCED_FACE('F829',(#2099),#2072,.T.);
#2101=CARTESIAN_POINT('',(498.5,999.929289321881,40.0075));
#2102=CARTESIAN_POINT('',(498.69736683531,999.935182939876,40.0075));
#2103=CARTESIAN_POINT('',(498.894584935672,999.941074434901,39.9682638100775));
#2104=CARTESIAN_POINT('',(499.259205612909,999.952859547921,39.8172329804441));
#2105=CARTESIAN_POINT('',(499.426429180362,999.958752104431,39.7054977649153));
#2106=CARTESIAN_POINT('',(499.705497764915,999.97053721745,39.4264291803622));
#2107=CARTESIAN_POINT('',(499.817232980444,999.97642977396,39.2592056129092));
#2108=CARTESIAN_POINT('',(499.968263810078,999.98821488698,38.8945849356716));
#2109=CARTESIAN_POINT('',(500.0075,999.994106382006,38.6973668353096));
#2110=CARTESIAN_POINT('',(500.0075,1000.,38.5));
#2111=CARTESIAN_POINT('',(498.5,999.929289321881,40.));
#2112=CARTESIAN_POINT('',(498.696384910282,999.935182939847,40.));
#2113=CARTESIAN_POINT('',(498.892621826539,999.941074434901,39.9609590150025));
#2114=CARTESIAN_POINT('',(499.255428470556,999.952859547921,39.8106795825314));
#2115=CARTESIAN_POINT('',(499.421820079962,999.958752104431,39.6995002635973));
#2116=CARTESIAN_POINT('',(499.699500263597,999.97053721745,39.4218200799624));
#2117=CARTESIAN_POINT('',(499.810679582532,999.97642977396,39.2554284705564));
#2118=CARTESIAN_POINT('',(499.960959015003,999.98821488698,38.8926218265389));
#2119=CARTESIAN_POINT('',(500.,999.994106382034,38.6963849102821));
#2120=CARTESIAN_POINT('',(500.,1000.,38.5));
#2121=CARTESIAN_POINT('',(498.5,999.929289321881,39.25));
#2122=CARTESIAN_POINT('',(498.59819240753,999.935182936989,39.25));
#2123=CARTESIAN_POINT('',(498.69631091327,999.941074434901,39.2304795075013));
#2124=CARTESIAN_POINT('',(498.877714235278,999.952859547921,39.1553397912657));
#2125=CARTESIAN_POINT('',(498.960910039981,999.958752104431,39.0997501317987));
#2126=CARTESIAN_POINT('',(499.099750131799,999.97053721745,38.9609100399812));
#2127=CARTESIAN_POINT('',(499.155339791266,999.97642977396,38.8777142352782));
#2128=CARTESIAN_POINT('',(499.230479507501,999.98821488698,38.6963109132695));
#2129=CARTESIAN_POINT('',(499.25,999.994106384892,38.5981924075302));
#2130=CARTESIAN_POINT('',(499.25,1000.,38.5));
#2131=CARTESIAN_POINT('',(498.5,999.929289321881,39.242425));
#2132=CARTESIAN_POINT('',(498.597200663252,999.93518293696,39.242425));
#2133=CARTESIAN_POINT('',(498.694328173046,999.941074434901,39.2231016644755));
#2134=CARTESIAN_POINT('',(498.873899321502,999.952859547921,39.1487208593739));
#2135=CARTESIAN_POINT('',(498.956254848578,999.958752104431,39.0936926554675));
#2136=CARTESIAN_POINT('',(499.093692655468,999.97053721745,38.9562548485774));
#2137=CARTESIAN_POINT('',(499.148720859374,999.97642977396,38.8738993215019));
#2138=CARTESIAN_POINT('',(499.223101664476,999.98821488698,38.6943281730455));
#2139=CARTESIAN_POINT('',(499.242425,999.994106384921,38.5972006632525));
#2140=CARTESIAN_POINT('',(499.242425,1000.,38.5));
#2141=B_SPLINE_SURFACE_WITH_KNOTS('',1,3,((#2101,#2102,#2103,#2104,#2105,#2106,#2107,#2108,
#2109,#2110),(#2111,#2112,#2113,#2114,#2115,#2116,#2117,#2118,#2119,#2120),(#2121,#2122,#2123,
#2124,#2125,#2126,#2127,#2128,#2129,#2130),(#2131,#2132,#2133,#2134,#2135,#2136,#2137,#2138,
#2139,#2140)),.UNSPECIFIED.,.F.,.F.,.F.,(2,1,1,2),(4,2,2,2,4),(-0.01,0.,1.,1.0101),(0.,0.25,0.5,
0.75,1.),.UNSPECIFIED.);
#2142=CARTESIAN_POINT('',(498.5,999.929289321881,39.25));
#2143=CARTESIAN_POINT('',(498.512271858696,999.930025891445,39.2500002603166));
#2144=CARTESIAN_POINT('',(498.524543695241,999.930762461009,39.2496988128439));
#2145=CARTESIAN_POINT('',(498.54905781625,999.932235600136,39.2484943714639));
#2146=CARTESIAN_POINT('',(498.561300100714,999.9329721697,39.2475913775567));
#2147=CARTESIAN_POINT('',(498.58572560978,999.934445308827,39.2451857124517));
#2148=CARTESIAN_POINT('',(498.597908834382,999.935181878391,39.2436830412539));
#2149=CARTESIAN_POINT('',(498.622186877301,999.936655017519,39.2400817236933));
#2150=CARTESIAN_POINT('',(498.634281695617,999.937391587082,39.2379830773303));
#2151=CARTESIAN_POINT('',(498.658353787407,999.93886472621,39.2331948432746));
#2152=CARTESIAN_POINT('',(498.670331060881,999.939601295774,39.2305052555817));
#2153=CARTESIAN_POINT('',(498.694139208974,999.941074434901,39.2245416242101));
#2154=CARTESIAN_POINT('',(498.705970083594,999.941811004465,39.2212675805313));
#2155=CARTESIAN_POINT('',(498.729456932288,999.943284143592,39.2141429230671));
#2156=CARTESIAN_POINT('',(498.741112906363,999.944020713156,39.2102923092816));
#2157=CARTESIAN_POINT('',(498.764221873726,999.945493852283,39.202023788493));
#2158=CARTESIAN_POINT('',(498.775674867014,999.946230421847,39.1976058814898));
#2159=CARTESIAN_POINT('',(498.798350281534,999.947703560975,39.1882134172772));
#2160=CARTESIAN_POINT('',(498.809572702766,999.948440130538,39.1832388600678));
#2161=CARTESIAN_POINT('',(498.83175993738,999.949913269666,39.1727450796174));
#2162=CARTESIAN_POINT('',(498.842724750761,999.95064983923,39.1672258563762));
#2163=CARTESIAN_POINT('',(498.864370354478,999.952122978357,39.1556560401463));
#2164=CARTESIAN_POINT('',(498.875051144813,999.952859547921,39.1496054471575));
#2165=CARTESIAN_POINT('',(498.896102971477,999.954332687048,39.1369874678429));
#2166=CARTESIAN_POINT('',(498.906474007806,999.955069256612,39.1304200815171));
#2167=CARTESIAN_POINT('',(498.926881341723,999.956542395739,39.1167843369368));
#2168=CARTESIAN_POINT('',(498.936917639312,999.957278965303,39.1097159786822));
#2169=CARTESIAN_POINT('',(498.956631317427,999.958752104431,39.0950953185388));
#2170=CARTESIAN_POINT('',(498.966308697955,999.959488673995,39.0875430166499));
#2171=CARTESIAN_POINT('',(498.985281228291,999.960961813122,39.0719726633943));
#2172=CARTESIAN_POINT('',(498.9945763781,999.961698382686,39.0639546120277));
#2173=CARTESIAN_POINT('',(499.01276205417,999.963171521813,39.0474720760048));
#2174=CARTESIAN_POINT('',(499.021652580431,999.963908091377,39.0390075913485));
#2175=CARTESIAN_POINT('',(499.039007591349,999.965381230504,39.0216525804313));
#2176=CARTESIAN_POINT('',(499.047472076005,999.966117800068,39.0127620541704));
#2177=CARTESIAN_POINT('',(499.063954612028,999.967590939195,38.9945763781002));
#2178=CARTESIAN_POINT('',(499.071972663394,999.968327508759,38.985281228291));
#2179=CARTESIAN_POINT('',(499.08754301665,999.969800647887,38.9663086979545));
#2180=CARTESIAN_POINT('',(499.095095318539,999.97053721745,38.9566313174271));
#2181=CARTESIAN_POINT('',(499.109715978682,999.972010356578,38.9369176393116));
#2182=CARTESIAN_POINT('',(499.116784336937,999.972746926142,38.9268813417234));
#2183=CARTESIAN_POINT('',(499.130420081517,999.974220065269,38.9064740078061));
#2184=CARTESIAN_POINT('',(499.136987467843,999.974956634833,38.896102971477));
#2185=CARTESIAN_POINT('',(499.149605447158,999.97642977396,38.8750511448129));
#2186=CARTESIAN_POINT('',(499.155656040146,999.977166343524,38.8643703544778));
#2187=CARTESIAN_POINT('',(499.167225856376,999.978639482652,38.8427247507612));
#2188=CARTESIAN_POINT('',(499.172745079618,999.979376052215,38.8317599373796));
#2189=CARTESIAN_POINT('',(499.183238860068,999.980849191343,38.8095727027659));
#2190=CARTESIAN_POINT('',(499.188213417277,999.981585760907,38.7983502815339));
#2191=CARTESIAN_POINT('',(499.19760588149,999.983058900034,38.7756748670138));
#2192=CARTESIAN_POINT('',(499.202023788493,999.983795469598,38.7642218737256));
#2193=CARTESIAN_POINT('',(499.210292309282,999.985268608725,38.7411129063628));
#2194=CARTESIAN_POINT('',(499.214142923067,999.986005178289,38.729456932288));
#2195=CARTESIAN_POINT('',(499.221267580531,999.987478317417,38.7059700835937));
#2196=CARTESIAN_POINT('',(499.22454162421,999.98821488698,38.6941392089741));
#2197=CARTESIAN_POINT('',(499.230505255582,999.989688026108,38.6703310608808));
#2198=CARTESIAN_POINT('',(499.233194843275,999.990424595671,38.6583537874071));
#2199=CARTESIAN_POINT('',(499.23798307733,999.991897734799,38.6342816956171));
#2200=CARTESIAN_POINT('',(499.240081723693,999.992634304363,38.6221868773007));
#2201=CARTESIAN_POINT('',(499.243683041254,999.99410744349,38.5979088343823));
#2202=CARTESIAN_POINT('',(499.245185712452,999.994844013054,38.5857256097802));
#2203=CARTESIAN_POINT('',(499.247591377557,999.996317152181,38.5613001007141));
#2204=CARTESIAN_POINT('',(499.248494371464,999.997053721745,38.5490578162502));
#2205=CARTESIAN_POINT('',(499.249698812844,999.998526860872,38.5245436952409));
#2206=CARTESIAN_POINT('',(499.250000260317,999.999263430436,38.5122718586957));
#2207=CARTESIAN_POINT('',(499.25,1000.,38.5));
#2208=B_SPLINE_CURVE_WITH_KNOTS('',3,(#2142,#2143,#2144,#2145,#2146,#2147,#2148,#2149,#2150,
#2151,#2152,#2153,#2154,#2155,#2156,#2157,#2158,#2159,#2160,#2161,#2162,#2163,#2164,#2165,#2166,
#2167,#2168,#2169,#2170,#2171,#2172,#2173,#2174,#2175,#2176,#2177,#2178,#2179,#2180,#2181,#2182,
#2183,#2184,#2185,#2186,#2187,#2188,#2189,#2190,#2191,#2192,#2193,#2194,#2195,#2196,#2197,#2198,
#2199,#2200,#2201,#2202,#2203,#2204,#2205,#2206,#2207),.UNSPECIFIED.,.F.,.F.,(4,2,2,2,2,2,2,2,2,
2,2,2,2,2,2,2,2,2,2,2,2,2,2,2,2,2,2,2,2,2,2,2,4),(0.,0.0368781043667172,0.0737562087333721,
0.110634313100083,0.147512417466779,0.184390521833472,0.221268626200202,0.258146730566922,
0.295024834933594,0.331902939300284,0.368781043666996,0.405659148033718,0.44253725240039,
0.47941535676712,0.51629346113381,0.553171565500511,0.590049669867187,0.626927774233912,
0.663805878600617,0.700683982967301,0.737562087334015,0.774440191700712,0.811318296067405,
0.848196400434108,0.885074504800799,0.921952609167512,0.958830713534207,0.995708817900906,
1.0325869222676,1.06946502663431,1.10634313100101,1.1432212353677,1.18009933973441),.UNSPECIFIED.);
#2209=CARTESIAN_POINT('',(498.5,999.929289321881,39.25));
#2210=VERTEX_POINT('',#2209);
#2211=EDGE_CURVE('E775',#2210,#714,#2208,.T.);
#2212=DIRECTION('',(0.,0.,1.));
#2213=VECTOR('',#2212,1.);
#2214=CARTESIAN_POINT('',(498.5,999.929289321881,39.25));
#2215=LINE('',#2214,#2213);
#2216=CARTESIAN_POINT('',(498.5,999.929289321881,40.));
#2217=VERTEX_POINT('',#2216);
#2218=EDGE_CURVE('E772',#2217,#2210,#2215,.F.);
#2219=CARTESIAN_POINT('',(498.5,999.929289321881,40.));
#2220=CARTESIAN_POINT('',(498.524543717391,999.930025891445,40.0000005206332));
#2221=CARTESIAN_POINT('',(498.549087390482,999.930762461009,39.9993976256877));
#2222=CARTESIAN_POINT('',(498.5981156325,999.932235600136,39.9969887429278));
#2223=CARTESIAN_POINT('',(498.622600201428,999.9329721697,39.9951827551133));
#2224=CARTESIAN_POINT('',(498.67145121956,999.934445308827,39.9903714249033));
#2225=CARTESIAN_POINT('',(498.695817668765,999.935181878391,39.9873660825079));
#2226=CARTESIAN_POINT('',(498.744373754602,999.936655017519,39.9801634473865));
#2227=CARTESIAN_POINT('',(498.768563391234,999.937391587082,39.9759661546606));
#2228=CARTESIAN_POINT('',(498.816707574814,999.93886472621,39.9663896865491));
#2229=CARTESIAN_POINT('',(498.840662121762,999.939601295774,39.9610105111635));
#2230=CARTESIAN_POINT('',(498.888278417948,999.941074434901,39.9490832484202));
#2231=CARTESIAN_POINT('',(498.911940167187,999.941811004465,39.9425351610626));
#2232=CARTESIAN_POINT('',(498.958913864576,999.943284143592,39.9282858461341));
#2233=CARTESIAN_POINT('',(498.982225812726,999.944020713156,39.9205846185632));
#2234=CARTESIAN_POINT('',(499.028443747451,999.945493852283,39.9040475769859));
#2235=CARTESIAN_POINT('',(499.051349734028,999.946230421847,39.8952117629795));
#2236=CARTESIAN_POINT('',(499.096700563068,999.947703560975,39.8764268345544));
#2237=CARTESIAN_POINT('',(499.119145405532,999.948440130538,39.8664777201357));
#2238=CARTESIAN_POINT('',(499.163519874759,999.949913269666,39.8454901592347));
#2239=CARTESIAN_POINT('',(499.185449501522,999.95064983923,39.8344517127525));
#2240=CARTESIAN_POINT('',(499.228740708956,999.952122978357,39.8113120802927));
#2241=CARTESIAN_POINT('',(499.250102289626,999.952859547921,39.7992108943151));
#2242=CARTESIAN_POINT('',(499.292205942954,999.954332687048,39.7739749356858));
#2243=CARTESIAN_POINT('',(499.312948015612,999.955069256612,39.7608401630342));
#2244=CARTESIAN_POINT('',(499.353762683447,999.956542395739,39.7335686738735));
#2245=CARTESIAN_POINT('',(499.373835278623,999.957278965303,39.7194319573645));
#2246=CARTESIAN_POINT('',(499.413262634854,999.958752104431,39.6901906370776));
#2247=CARTESIAN_POINT('',(499.432617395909,999.959488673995,39.6750860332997));
#2248=CARTESIAN_POINT('',(499.470562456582,999.960961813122,39.6439453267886));
#2249=CARTESIAN_POINT('',(499.4891527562,999.961698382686,39.6279092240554));
#2250=CARTESIAN_POINT('',(499.525524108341,999.963171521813,39.5949441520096));
#2251=CARTESIAN_POINT('',(499.543305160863,999.963908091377,39.5780151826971));
#2252=CARTESIAN_POINT('',(499.578015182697,999.965381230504,39.5433051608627));
#2253=CARTESIAN_POINT('',(499.59494415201,999.966117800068,39.5255241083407));
#2254=CARTESIAN_POINT('',(499.627909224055,999.967590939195,39.4891527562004));
#2255=CARTESIAN_POINT('',(499.643945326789,999.968327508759,39.4705624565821));
#2256=CARTESIAN_POINT('',(499.6750860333,999.969800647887,39.432617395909));
#2257=CARTESIAN_POINT('',(499.690190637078,999.97053721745,39.4132626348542));
#2258=CARTESIAN_POINT('',(499.719431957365,999.972010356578,39.3738352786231));
#2259=CARTESIAN_POINT('',(499.733568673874,999.972746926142,39.3537626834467));
#2260=CARTESIAN_POINT('',(499.760840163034,999.974220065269,39.3129480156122));
#2261=CARTESIAN_POINT('',(499.773974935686,999.974956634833,39.292205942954));
#2262=CARTESIAN_POINT('',(499.799210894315,999.97642977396,39.2501022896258));
#2263=CARTESIAN_POINT('',(499.811312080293,999.977166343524,39.2287407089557));
#2264=CARTESIAN_POINT('',(499.834451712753,999.978639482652,39.1854495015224));
#2265=CARTESIAN_POINT('',(499.845490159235,999.979376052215,39.1635198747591));
#2266=CARTESIAN_POINT('',(499.866477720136,999.980849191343,39.1191454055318));
#2267=CARTESIAN_POINT('',(499.876426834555,999.981585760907,39.0967005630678));
#2268=CARTESIAN_POINT('',(499.89521176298,999.983058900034,39.0513497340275));
#2269=CARTESIAN_POINT('',(499.904047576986,999.983795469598,39.0284437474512));
#2270=CARTESIAN_POINT('',(499.920584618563,999.985268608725,38.9822258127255));
#2271=CARTESIAN_POINT('',(499.928285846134,999.986005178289,38.958913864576));
#2272=CARTESIAN_POINT('',(499.942535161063,999.987478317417,38.9119401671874));
#2273=CARTESIAN_POINT('',(499.94908324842,999.98821488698,38.8882784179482));
#2274=CARTESIAN_POINT('',(499.961010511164,999.989688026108,38.8406621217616));
#2275=CARTESIAN_POINT('',(499.966389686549,999.990424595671,38.8167075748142));
#2276=CARTESIAN_POINT('',(499.975966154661,999.991897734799,38.7685633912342));
#2277=CARTESIAN_POINT('',(499.980163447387,999.992634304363,38.7443737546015));
#2278=CARTESIAN_POINT('',(499.987366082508,999.99410744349,38.6958176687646));
#2279=CARTESIAN_POINT('',(499.990371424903,999.994844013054,38.6714512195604));
#2280=CARTESIAN_POINT('',(499.995182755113,999.996317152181,38.6226002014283));
#2281=CARTESIAN_POINT('',(499.996988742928,999.997053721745,38.5981156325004));
#2282=CARTESIAN_POINT('',(499.999397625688,999.998526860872,38.5490873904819));
#2283=CARTESIAN_POINT('',(500.000000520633,999.999263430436,38.5245437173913));
#2284=CARTESIAN_POINT('',(500.,1000.,38.5));
#2285=B_SPLINE_CURVE_WITH_KNOTS('',3,(#2219,#2220,#2221,#2222,#2223,#2224,#2225,#2226,#2227,
#2228,#2229,#2230,#2231,#2232,#2233,#2234,#2235,#2236,#2237,#2238,#2239,#2240,#2241,#2242,#2243,
#2244,#2245,#2246,#2247,#2248,#2249,#2250,#2251,#2252,#2253,#2254,#2255,#2256,#2257,#2258,#2259,
#2260,#2261,#2262,#2263,#2264,#2265,#2266,#2267,#2268,#2269,#2270,#2271,#2272,#2273,#2274,#2275,
#2276,#2277,#2278,#2279,#2280,#2281,#2282,#2283,#2284),.UNSPECIFIED.,.F.,.F.,(4,2,2,2,2,2,2,2,2,
2,2,2,2,2,2,2,2,2,2,2,2,2,2,2,2,2,2,2,2,2,2,2,4),(0.,0.0736568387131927,0.147313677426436,
0.220970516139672,0.294627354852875,0.368284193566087,0.441941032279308,0.515597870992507,
0.589254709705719,0.662911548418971,0.736568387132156,0.810225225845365,0.883882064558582,
0.957538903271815,1.03119574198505,1.10485258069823,1.17850941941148,1.2521662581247,
1.3258230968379,1.39947993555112,1.47313677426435,1.54679361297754,1.62045045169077,
1.69410729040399,1.76776412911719,1.84142096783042,1.91507780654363,1.98873464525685,
2.06239148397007,2.13604832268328,2.2097051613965,2.28336200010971,2.35701883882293),.UNSPECIFIED.);
#2286=EDGE_CURVE('E798',#2217,#722,#2285,.T.);
#2287=ORIENTED_EDGE('',*,*,#2211,.F.);
#2288=ORIENTED_EDGE('',*,*,#2218,.F.);
#2289=ORIENTED_EDGE('',*,*,#2286,.T.);
#2290=ORIENTED_EDGE('',*,*,#723,.T.);
#2291=EDGE_LOOP('',(#2287,#2288,#2289,#2290));
#2292=FACE_BOUND('',#2291,.T.);
#2293=ADVANCED_FACE('F822',(#2292),#2141,.F.);
#2294=CARTESIAN_POINT('',(498.5,1000.,38.5));
#2295=DIRECTION('',(0.,1.,0.));
#2296=DIRECTION('',(0.,0.,1.));
#2297=AXIS2_PLACEMENT_3D('',#2294,#2295,#2296);
#2298=CYLINDRICAL_SURFACE('',#2297,1.50000000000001);
#2299=ORIENTED_EDGE('',*,*,#745,.F.);
#2300=ORIENTED_EDGE('',*,*,#2286,.F.);
#2301=DIRECTION('',(0.,1.,0.));
#2302=VECTOR('',#2301,1.);
#2303=CARTESIAN_POINT('',(498.5,0.,40.));
#2304=LINE('',#2303,#2302);
#2305=EDGE_CURVE('E789',#2217,#2080,#2304,.F.);
#2306=ORIENTED_EDGE('',*,*,#2305,.T.);
#2307=ORIENTED_EDGE('',*,*,#2096,.F.);
#2308=EDGE_LOOP('',(#2299,#2300,#2306,#2307));
#2309=FACE_BOUND('',#2308,.T.);
#2310=ADVANCED_FACE('F820',(#2309),#2298,.T.);
#2311=CARTESIAN_POINT('',(498.5,1000.,38.5));
#2312=DIRECTION('',(0.,1.,0.));
#2313=DIRECTION('',(0.,0.,1.));
#2314=AXIS2_PLACEMENT_3D('',#2311,#2312,#2313);
#2315=CYLINDRICAL_SURFACE('',#2314,0.750000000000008);
#2316=ORIENTED_EDGE('',*,*,#763,.T.);
#2317=ORIENTED_EDGE('',*,*,#2088,.T.);
#2318=DIRECTION('',(0.,1.,0.));
#2319=VECTOR('',#2318,1.);
#2320=CARTESIAN_POINT('',(498.5,0.,39.25));
#2321=LINE('',#2320,#2319);
#2322=EDGE_CURVE('E791',#2078,#2210,#2321,.T.);
#2323=ORIENTED_EDGE('',*,*,#2322,.T.);
#2324=ORIENTED_EDGE('',*,*,#2211,.T.);
#2325=EDGE_LOOP('',(#2316,#2317,#2323,#2324));
#2326=FACE_BOUND('',#2325,.T.);
#2327=ADVANCED_FACE('F810',(#2326),#2315,.F.);
#2328=CARTESIAN_POINT('',(483.5,0.,40.0000000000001));
#2329=DIRECTION('',(0.,0.,-1.));
#2330=DIRECTION('',(-1.,0.,0.));
#2331=AXIS2_PLACEMENT_3D('',#2328,#2329,#2330);
#2332=PLANE('',#2331);
#2333=DIRECTION('',(0.707106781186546,0.707106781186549,0.));
#2334=VECTOR('',#2333,1.);
#2335=CARTESIAN_POINT('',(-208.636530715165,292.792758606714,40.0000000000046));
#2336=LINE('',#2335,#2334);
#2337=CARTESIAN_POINT('',(483.5,984.929289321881,40.0000000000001));
#2338=VERTEX_POINT('',#2337);
#2339=EDGE_CURVE('E763',#2338,#2217,#2336,.T.);
#2340=ORIENTED_EDGE('',*,*,#2339,.F.);
#2341=DIRECTION('',(0.,-1.,0.));
#2342=VECTOR('',#2341,1.);
#2343=CARTESIAN_POINT('',(483.5,0.,40.0000000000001));
#2344=LINE('',#2343,#2342);
#2345=CARTESIAN_POINT('',(483.5,0.,40.0000000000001));
#2346=VERTEX_POINT('',#2345);
#2347=EDGE_CURVE('E779',#2346,#2338,#2344,.F.);
#2348=ORIENTED_EDGE('',*,*,#2347,.F.);
#2349=DIRECTION('',(1.,0.,0.));
#2350=VECTOR('',#2349,1.);
#2351=CARTESIAN_POINT('',(499.25,0.,40.));
#2352=LINE('',#2351,#2350);
#2353=EDGE_CURVE('E782',#2080,#2346,#2352,.F.);
#2354=ORIENTED_EDGE('',*,*,#2353,.F.);
#2355=ORIENTED_EDGE('',*,*,#2305,.F.);
#2356=EDGE_LOOP('',(#2340,#2348,#2354,#2355));
#2357=FACE_BOUND('',#2356,.T.);
#2358=ADVANCED_FACE('F819',(#2357),#2332,.F.);
#2359=CARTESIAN_POINT('',(483.5,0.,39.2500000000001));
#2360=DIRECTION('',(0.,0.,-1.));
#2361=DIRECTION('',(-1.,0.,0.));
#2362=AXIS2_PLACEMENT_3D('',#2359,#2360,#2361);
#2363=PLANE('',#2362);
#2364=DIRECTION('',(0.,1.,0.));
#2365=VECTOR('',#2364,1.);
#2366=CARTESIAN_POINT('',(483.5,0.,39.2500000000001));
#2367=LINE('',#2366,#2365);
#2368=CARTESIAN_POINT('',(483.5,0.,39.2500000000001));
#2369=VERTEX_POINT('',#2368);
#2370=CARTESIAN_POINT('',(483.5,984.929289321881,39.2500000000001));
#2371=VERTEX_POINT('',#2370);
#2372=EDGE_CURVE('E784',#2369,#2371,#2367,.T.);
#2373=ORIENTED_EDGE('',*,*,#2372,.T.);
#2374=DIRECTION('',(0.707106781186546,0.707106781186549,0.));
#2375=VECTOR('',#2374,1.);
#2376=CARTESIAN_POINT('',(-8.96464466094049,492.464644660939,39.2500000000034));
#2377=LINE('',#2376,#2375);
#2378=EDGE_CURVE('E768',#2371,#2210,#2377,.T.);
#2379=ORIENTED_EDGE('',*,*,#2378,.T.);
#2380=ORIENTED_EDGE('',*,*,#2322,.F.);
#2381=DIRECTION('',(-1.,0.,0.));
#2382=VECTOR('',#2381,1.);
#2383=CARTESIAN_POINT('',(483.5,0.,39.2500000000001));
#2384=LINE('',#2383,#2382);
#2385=EDGE_CURVE('E787',#2078,#2369,#2384,.T.);
#2386=ORIENTED_EDGE('',*,*,#2385,.T.);
#2387=EDGE_LOOP('',(#2373,#2379,#2380,#2386));
#2388=FACE_BOUND('',#2387,.T.);
#2389=ADVANCED_FACE('F1583',(#2388),#2363,.T.);
#2390=CARTESIAN_POINT('',(483.5,0.,40.0000000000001));
#2391=DIRECTION('',(-1.,0.,0.));
#2392=DIRECTION('',(0.,0.,1.));
#2393=AXIS2_PLACEMENT_3D('',#2390,#2391,#2392);
#2394=PLANE('',#2393);
#2395=ORIENTED_EDGE('',*,*,#2347,.T.);
#2396=DIRECTION('',(0.,0.,-1.));
#2397=VECTOR('',#2396,1.);
#2398=CARTESIAN_POINT('',(483.5,984.929289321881,40.0000000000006));
#2399=LINE('',#2398,#2397);
#2400=EDGE_CURVE('E766',#2338,#2371,#2399,.T.);
#2401=ORIENTED_EDGE('',*,*,#2400,.T.);
#2402=ORIENTED_EDGE('',*,*,#2372,.F.);
#2403=DIRECTION('',(0.,0.,-1.));
#2404=VECTOR('',#2403,1.);
#2405=CARTESIAN_POINT('',(483.5,0.,40.0000000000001));
#2406=LINE('',#2405,#2404);
#2407=EDGE_CURVE('E776',#2346,#2369,#2406,.T.);
#2408=ORIENTED_EDGE('',*,*,#2407,.F.);
#2409=EDGE_LOOP('',(#2395,#2401,#2402,#2408));
#2410=FACE_BOUND('',#2409,.T.);
#2411=ADVANCED_FACE('F1591',(#2410),#2394,.T.);
#2412=CARTESIAN_POINT('',(499.25,0.,40.));
#2413=DIRECTION('',(0.,-1.,0.));
#2414=DIRECTION('',(0.,0.,-1.));
#2415=AXIS2_PLACEMENT_3D('',#2412,#2413,#2414);
#2416=PLANE('',#2415);
#2417=ORIENTED_EDGE('',*,*,#2385,.F.);
#2418=ORIENTED_EDGE('',*,*,#2081,.T.);
#2419=ORIENTED_EDGE('',*,*,#2353,.T.);
#2420=ORIENTED_EDGE('',*,*,#2407,.T.);
#2421=EDGE_LOOP('',(#2417,#2418,#2419,#2420));
#2422=FACE_BOUND('',#2421,.T.);
#2423=ADVANCED_FACE('F823',(#2422),#2416,.T.);
#2424=CARTESIAN_POINT('',(-208.636530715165,292.792758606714,40.0000000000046));
#2425=DIRECTION('',(-0.707106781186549,0.707106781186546,0.));
#2426=DIRECTION('',(-0.707106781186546,-0.707106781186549,0.));
#2427=AXIS2_PLACEMENT_3D('',#2424,#2425,#2426);
#2428=PLANE('',#2427);
#2429=ORIENTED_EDGE('',*,*,#2378,.F.);
#2430=ORIENTED_EDGE('',*,*,#2400,.F.);
#2431=ORIENTED_EDGE('',*,*,#2339,.T.);
#2432=ORIENTED_EDGE('',*,*,#2218,.T.);
#2433=EDGE_LOOP('',(#2429,#2430,#2431,#2432));
#2434=FACE_BOUND('',#2433,.T.);
#2435=ADVANCED_FACE('F1594',(#2434),#2428,.T.);
#2436=CARTESIAN_POINT('',(-58.6487222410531,1060.07801156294,40.0010000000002));
#2437=DIRECTION('',(-0.70710678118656,-0.707106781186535,0.));
#2438=DIRECTION('',(0.707106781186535,-0.70710678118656,0.));
#2439=AXIS2_PLACEMENT_3D('',#2436,#2437,#2438);
#2440=PLANE('',#2439);
#2441=ORIENTED_EDGE('',*,*,#310,.T.);
#2442=DIRECTION('',(0.,0.,-1.));
#2443=VECTOR('',#2442,1.);
#2444=CARTESIAN_POINT('',(79.9999999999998,921.429289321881,40.0010000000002));
#2445=LINE('',#2444,#2443);
#2446=EDGE_CURVE('E739',#301,#122,#2445,.T.);
#2447=ORIENTED_EDGE('',*,*,#2446,.T.);
#2448=ORIENTED_EDGE('',*,*,#123,.T.);
#2449=DIRECTION('',(0.,0.,-1.));
#2450=VECTOR('',#2449,1.);
#2451=CARTESIAN_POINT('',(70.7747154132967,930.654573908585,40.0010000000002));
#2452=LINE('',#2451,#2450);
#2453=EDGE_CURVE('E738',#309,#114,#2452,.T.);
#2454=ORIENTED_EDGE('',*,*,#2453,.F.);
#2455=EDGE_LOOP('',(#2441,#2447,#2448,#2454));
#2456=FACE_BOUND('',#2455,.T.);
#2457=ADVANCED_FACE('F1332',(#2456),#2440,.F.);
#2458=CARTESIAN_POINT('',(79.9999999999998,500.,40.0010000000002));
#2459=DIRECTION('',(1.,0.,0.));
#2460=DIRECTION('',(0.,0.,-1.));
#2461=AXIS2_PLACEMENT_3D('',#2458,#2459,#2460);
#2462=PLANE('',#2461);
#2463=DIRECTION('',(0.,0.,-1.));
#2464=VECTOR('',#2463,1.);
#2465=CARTESIAN_POINT('',(79.9999999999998,421.570710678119,40.0010000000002));
#2466=LINE('',#2465,#2464);
#2467=EDGE_CURVE('E742',#293,#130,#2466,.T.);
#2468=ORIENTED_EDGE('',*,*,#2467,.T.);
#2469=ORIENTED_EDGE('',*,*,#131,.F.);
#2470=ORIENTED_EDGE('',*,*,#2446,.F.);
#2471=ORIENTED_EDGE('',*,*,#302,.F.);
#2472=EDGE_LOOP('',(#2468,#2469,#2470,#2471));
#2473=FACE_BOUND('',#2472,.T.);
#2474=ADVANCED_FACE('F631',(#2473),#2462,.T.);
#2475=CARTESIAN_POINT('',(-230.148722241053,111.421988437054,40.0010000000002));
#2476=DIRECTION('',(0.70710678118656,-0.707106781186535,0.));
#2477=DIRECTION('',(0.707106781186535,0.70710678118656,0.));
#2478=AXIS2_PLACEMENT_3D('',#2475,#2476,#2477);
#2479=PLANE('',#2478);
#2480=DIRECTION('',(0.,0.,-1.));
#2481=VECTOR('',#2480,1.);
#2482=CARTESIAN_POINT('',(70.7747154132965,412.345426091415,40.0010000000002));
#2483=LINE('',#2482,#2481);
#2484=EDGE_CURVE('E744',#285,#138,#2483,.T.);
#2485=ORIENTED_EDGE('',*,*,#2484,.T.);
#2486=ORIENTED_EDGE('',*,*,#139,.F.);
#2487=ORIENTED_EDGE('',*,*,#2467,.F.);
#2488=ORIENTED_EDGE('',*,*,#294,.F.);
#2489=EDGE_LOOP('',(#2485,#2486,#2487,#2488));
#2490=FACE_BOUND('',#2489,.T.);
#2491=ADVANCED_FACE('F2048',(#2490),#2479,.T.);
#2492=CARTESIAN_POINT('',(69.7499999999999,411.25,40.0010000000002));
#2493=DIRECTION('',(0.,0.,-1.));
#2494=DIRECTION('',(-1.,0.,0.));
#2495=AXIS2_PLACEMENT_3D('',#2492,#2493,#2494);
#2496=CYLINDRICAL_SURFACE('',#2495,1.50000000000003);
#2497=DIRECTION('',(0.,0.,-1.));
#2498=VECTOR('',#2497,1.);
#2499=CARTESIAN_POINT('',(70.8454260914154,412.274715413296,40.0010000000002));
#2500=LINE('',#2499,#2498);
#2501=EDGE_CURVE('E746',#276,#147,#2500,.T.);
#2502=ORIENTED_EDGE('',*,*,#2501,.T.);
#2503=ORIENTED_EDGE('',*,*,#148,.F.);
#2504=ORIENTED_EDGE('',*,*,#2484,.F.);
#2505=ORIENTED_EDGE('',*,*,#286,.F.);
#2506=EDGE_LOOP('',(#2502,#2503,#2504,#2505));
#2507=FACE_BOUND('',#2506,.T.);
#2508=ADVANCED_FACE('F2058',(#2507),#2496,.F.);
#2509=CARTESIAN_POINT('',(-230.07801156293,111.351277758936,40.0010000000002));
#2510=DIRECTION('',(0.707106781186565,-0.70710678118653,0.));
#2511=DIRECTION('',(0.70710678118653,0.707106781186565,0.));
#2512=AXIS2_PLACEMENT_3D('',#2509,#2510,#2511);
#2513=PLANE('',#2512);
#2514=ORIENTED_EDGE('',*,*,#277,.T.);
#2515=DIRECTION('',(0.,0.,-1.));
#2516=VECTOR('',#2515,1.);
#2517=CARTESIAN_POINT('',(80.0707106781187,421.5,40.0010000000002));
#2518=LINE('',#2517,#2516);
#2519=EDGE_CURVE('E748',#268,#155,#2518,.T.);
#2520=ORIENTED_EDGE('',*,*,#2519,.T.);
#2521=ORIENTED_EDGE('',*,*,#156,.T.);
#2522=ORIENTED_EDGE('',*,*,#2501,.F.);
#2523=EDGE_LOOP('',(#2514,#2520,#2521,#2522));
#2524=FACE_BOUND('',#2523,.T.);
#2525=ADVANCED_FACE('F2068',(#2524),#2513,.F.);
#2526=CARTESIAN_POINT('',(-618.726733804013,421.5,40.0010000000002));
#2527=DIRECTION('',(0.,-1.,0.));
#2528=DIRECTION('',(0.,0.,-1.));
#2529=AXIS2_PLACEMENT_3D('',#2526,#2527,#2528);
#2530=PLANE('',#2529);
#2531=ORIENTED_EDGE('',*,*,#269,.T.);
#2532=DIRECTION('',(0.,0.,-1.));
#2533=VECTOR('',#2532,1.);
#2534=CARTESIAN_POINT('',(419.929289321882,421.5,40.0010000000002));
#2535=LINE('',#2534,#2533);
#2536=EDGE_CURVE('E750',#260,#163,#2535,.T.);
#2537=ORIENTED_EDGE('',*,*,#2536,.T.);
#2538=ORIENTED_EDGE('',*,*,#164,.T.);
#2539=ORIENTED_EDGE('',*,*,#2519,.F.);
#2540=EDGE_LOOP('',(#2531,#2537,#2538,#2539));
#2541=FACE_BOUND('',#2540,.T.);
#2542=ADVANCED_FACE('F2080',(#2541),#2530,.F.);
#2543=CARTESIAN_POINT('',(-138.648722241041,980.078011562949,40.0010000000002));
#2544=DIRECTION('',(0.707106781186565,0.70710678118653,0.));
#2545=DIRECTION('',(-0.70710678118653,0.707106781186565,0.));
#2546=AXIS2_PLACEMENT_3D('',#2543,#2544,#2545);
#2547=PLANE('',#2546);
#2548=DIRECTION('',(0.,0.,-1.));
#2549=VECTOR('',#2548,1.);
#2550=CARTESIAN_POINT('',(429.154573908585,412.274715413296,40.0010000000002));
#2551=LINE('',#2550,#2549);
#2552=EDGE_CURVE('E752',#252,#171,#2551,.T.);
#2553=ORIENTED_EDGE('',*,*,#2552,.T.);
#2554=ORIENTED_EDGE('',*,*,#172,.F.);
#2555=ORIENTED_EDGE('',*,*,#2536,.F.);
#2556=ORIENTED_EDGE('',*,*,#261,.F.);
#2557=EDGE_LOOP('',(#2553,#2554,#2555,#2556));
#2558=FACE_BOUND('',#2557,.T.);
#2559=ADVANCED_FACE('F2091',(#2558),#2547,.T.);
#2560=CARTESIAN_POINT('',(430.25,411.25,40.0010000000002));
#2561=DIRECTION('',(0.,0.,-1.));
#2562=DIRECTION('',(-1.,0.,0.));
#2563=AXIS2_PLACEMENT_3D('',#2560,#2561,#2562);
#2564=CYLINDRICAL_SURFACE('',#2563,1.50000000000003);
#2565=ORIENTED_EDGE('',*,*,#253,.T.);
#2566=DIRECTION('',(0.,0.,-1.));
#2567=VECTOR('',#2566,1.);
#2568=CARTESIAN_POINT('',(429.225284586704,412.345426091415,40.0010000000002));
#2569=LINE('',#2568,#2567);
#2570=EDGE_CURVE('E754',#243,#180,#2569,.T.);
#2571=ORIENTED_EDGE('',*,*,#2570,.T.);
#2572=ORIENTED_EDGE('',*,*,#181,.T.);
#2573=ORIENTED_EDGE('',*,*,#2552,.F.);
#2574=EDGE_LOOP('',(#2565,#2571,#2572,#2573));
#2575=FACE_BOUND('',#2574,.T.);
#2576=ADVANCED_FACE('F2103',(#2575),#2564,.F.);
#2577=CARTESIAN_POINT('',(-138.578011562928,980.148722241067,40.0010000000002));
#2578=DIRECTION('',(0.70710678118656,0.707106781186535,0.));
#2579=DIRECTION('',(-0.707106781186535,0.70710678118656,0.));
#2580=AXIS2_PLACEMENT_3D('',#2577,#2578,#2579);
#2581=PLANE('',#2580);
#2582=ORIENTED_EDGE('',*,*,#244,.T.);
#2583=DIRECTION('',(0.,0.,-1.));
#2584=VECTOR('',#2583,1.);
#2585=CARTESIAN_POINT('',(420.,421.570710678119,40.0010000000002));
#2586=LINE('',#2585,#2584);
#2587=EDGE_CURVE('E756',#235,#188,#2586,.T.);
#2588=ORIENTED_EDGE('',*,*,#2587,.T.);
#2589=ORIENTED_EDGE('',*,*,#189,.T.);
#2590=ORIENTED_EDGE('',*,*,#2570,.F.);
#2591=EDGE_LOOP('',(#2582,#2588,#2589,#2590));
#2592=FACE_BOUND('',#2591,.T.);
#2593=ADVANCED_FACE('F2114',(#2592),#2581,.F.);
#2594=CARTESIAN_POINT('',(420.,500.,40.0010000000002));
#2595=DIRECTION('',(1.,0.,0.));
#2596=DIRECTION('',(0.,0.,-1.));
#2597=AXIS2_PLACEMENT_3D('',#2594,#2595,#2596);
#2598=PLANE('',#2597);
#2599=ORIENTED_EDGE('',*,*,#236,.T.);
#2600=DIRECTION('',(0.,0.,-1.));
#2601=VECTOR('',#2600,1.);
#2602=CARTESIAN_POINT('',(420.,921.429289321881,40.0010000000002));
#2603=LINE('',#2602,#2601);
#2604=EDGE_CURVE('E758',#227,#196,#2603,.T.);
#2605=ORIENTED_EDGE('',*,*,#2604,.T.);
#2606=ORIENTED_EDGE('',*,*,#197,.T.);
#2607=ORIENTED_EDGE('',*,*,#2587,.F.);
#2608=EDGE_LOOP('',(#2599,#2605,#2606,#2607));
#2609=FACE_BOUND('',#2608,.T.);
#2610=ADVANCED_FACE('F2126',(#2609),#2598,.F.);
#2611=CARTESIAN_POINT('',(-310.078011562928,191.351277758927,40.0010000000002));
#2612=DIRECTION('',(-0.70710678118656,0.707106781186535,0.));
#2613=DIRECTION('',(-0.707106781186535,-0.70710678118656,0.));
#2614=AXIS2_PLACEMENT_3D('',#2611,#2612,#2613);
#2615=PLANE('',#2614);
#2616=ORIENTED_EDGE('',*,*,#55,.T.);
#2617=ORIENTED_EDGE('',*,*,#203,.F.);
#2618=ORIENTED_EDGE('',*,*,#2604,.F.);
#2619=ORIENTED_EDGE('',*,*,#228,.F.);
#2620=EDGE_LOOP('',(#2616,#2617,#2618,#2619));
#2621=FACE_BOUND('',#2620,.T.);
#2622=ADVANCED_FACE('F1115',(#2621),#2615,.T.);
#2623=CARTESIAN_POINT('',(69.7499999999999,931.75,40.0010000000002));
#2624=DIRECTION('',(0.,0.,-1.));
#2625=DIRECTION('',(-1.,0.,0.));
#2626=AXIS2_PLACEMENT_3D('',#2623,#2624,#2625);
#2627=CYLINDRICAL_SURFACE('',#2626,1.50000000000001);
#2628=CARTESIAN_POINT('',(70.67848633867,932.928097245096,0.750000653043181));
#2629=CARTESIAN_POINT('',(70.67848633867,932.928097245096,6.5304318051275E-07));
#2630=B_SPLINE_CURVE_WITH_KNOTS('',1,(#2628,#2629),.UNSPECIFIED.,.F.,.F.,(2,2),(0.,1.),.UNSPECIFIED.);
#2631=EDGE_CURVE('E1284',#218,#105,#2630,.T.);
#2632=ORIENTED_EDGE('',*,*,#2631,.F.);
#2633=ORIENTED_EDGE('',*,*,#317,.T.);
#2634=ORIENTED_EDGE('',*,*,#2453,.T.);
#2635=ORIENTED_EDGE('',*,*,#115,.T.);
#2636=EDGE_LOOP('',(#2632,#2633,#2634,#2635));
#2637=FACE_BOUND('',#2636,.T.);
#2638=ADVANCED_FACE('F1111',(#2637),#2627,.F.);
#2639=CARTESIAN_POINT('',(429.154573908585,931.435933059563,1.34688538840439));
#2640=CARTESIAN_POINT('',(429.006182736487,931.455647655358,1.15475863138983));
#2641=CARTESIAN_POINT('',(428.900001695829,931.513499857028,0.961756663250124));
#2642=CARTESIAN_POINT('',(428.804242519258,931.658061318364,0.695509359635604));
#2643=CARTESIAN_POINT('',(428.78289723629,931.715776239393,0.610661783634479));
#2644=CARTESIAN_POINT('',(428.76674097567,931.815672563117,0.492443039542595));
#2645=CARTESIAN_POINT('',(428.763999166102,931.851184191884,0.454545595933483));
#2646=CARTESIAN_POINT('',(428.763851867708,931.90757801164,0.400355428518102));
#2647=CARTESIAN_POINT('',(428.764463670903,931.926896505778,0.382734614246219));
#2648=CARTESIAN_POINT('',(428.766372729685,931.956626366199,0.357015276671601));
#2649=CARTESIAN_POINT('',(428.767174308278,931.966661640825,0.348560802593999));
#2650=CARTESIAN_POINT('',(428.768624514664,931.981898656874,0.336062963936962));
#2651=CARTESIAN_POINT('',(428.769149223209,931.987008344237,0.331927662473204));
#2652=CARTESIAN_POINT('',(428.770281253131,931.997288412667,0.323719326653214));
#2653=CARTESIAN_POINT('',(428.770946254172,932.002921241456,0.319286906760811));
#2654=CARTESIAN_POINT('',(428.790447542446,932.159273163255,0.197779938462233));
#2655=CARTESIAN_POINT('',(428.845734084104,932.322235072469,0.117897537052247));
#2656=CARTESIAN_POINT('',(429.029059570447,932.637463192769,0.0191866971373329));
#2657=CARTESIAN_POINT('',(429.157211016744,932.789884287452,6.53043180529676E-07));
#2658=CARTESIAN_POINT('',(429.32151366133,932.928097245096,6.5304318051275E-07));
#2659=CARTESIAN_POINT('',(429.154573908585,932.182015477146,1.42344272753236));
#2660=CARTESIAN_POINT('',(429.006159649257,932.191874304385,1.32736444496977));
#2661=CARTESIAN_POINT('',(428.900001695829,932.220798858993,1.23087844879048));
#2662=CARTESIAN_POINT('',(428.804242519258,932.293079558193,1.09775485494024));
#2663=CARTESIAN_POINT('',(428.78289723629,932.321937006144,1.0553310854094));
#2664=CARTESIAN_POINT('',(428.76674097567,932.371885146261,0.996221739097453));
#2665=CARTESIAN_POINT('',(428.763999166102,932.389640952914,0.97727302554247));
#2666=CARTESIAN_POINT('',(428.763851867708,932.417837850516,0.950177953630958));
#2667=CARTESIAN_POINT('',(428.764463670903,932.42749709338,0.941367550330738));
#2668=CARTESIAN_POINT('',(428.766372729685,932.442362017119,0.928507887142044));
#2669=CARTESIAN_POINT('',(428.767174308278,932.447379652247,0.92428065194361));
#2670=CARTESIAN_POINT('',(428.768624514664,932.454998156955,0.918031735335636));
#2671=CARTESIAN_POINT('',(428.769149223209,932.457552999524,0.915964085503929));
#2672=CARTESIAN_POINT('',(428.770281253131,932.462693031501,0.911859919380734));
#2673=CARTESIAN_POINT('',(428.770946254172,932.46550944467,0.909643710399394));
#2674=CARTESIAN_POINT('',(428.790447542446,932.543685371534,0.848890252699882));
#2675=CARTESIAN_POINT('',(428.845734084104,932.625166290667,0.808949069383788));
#2676=CARTESIAN_POINT('',(429.029059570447,932.782780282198,0.759593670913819));
#2677=CARTESIAN_POINT('',(429.157139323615,932.8589606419,0.750000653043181));
#2678=CARTESIAN_POINT('',(429.32151366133,932.928097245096,0.750000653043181));
#2679=B_SPLINE_SURFACE_WITH_KNOTS('',1,3,((#2639,#2640,#2641,#2642,#2643,#2644,#2645,#2646,
#2647,#2648,#2649,#2650,#2651,#2652,#2653,#2654,#2655,#2656,#2657,#2658),(#2659,#2660,#2661,
#2662,#2663,#2664,#2665,#2666,#2667,#2668,#2669,#2670,#2671,#2672,#2673,#2674,#2675,#2676,#2677,
#2678)),.UNSPECIFIED.,.F.,.F.,.F.,(2,2),(4,2,2,2,2,2,2,2,2,4),(0.,1.),(0.,0.25,0.375,0.4375,
0.46875,0.484375,0.4921875,0.5,0.75,1.),.UNSPECIFIED.);
#2680=CARTESIAN_POINT('',(429.154573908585,931.435933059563,1.3468853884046));
#2681=CARTESIAN_POINT('',(429.154573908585,932.182015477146,1.42344272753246));
#2682=B_SPLINE_CURVE_WITH_KNOTS('',1,(#2680,#2681),.UNSPECIFIED.,.F.,.F.,(2,2),(0.,1.),.UNSPECIFIED.);
#2683=CARTESIAN_POINT('',(429.154573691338,931.435933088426,1.34688510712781));
#2684=VERTEX_POINT('',#2683);
#2685=CARTESIAN_POINT('',(429.154573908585,932.182015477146,1.42344272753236));
#2686=VERTEX_POINT('',#2685);
#2687=EDGE_CURVE('E597',#2684,#2686,#2682,.T.);
#2688=CARTESIAN_POINT('',(429.154573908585,931.435933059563,1.34688538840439));
#2689=CARTESIAN_POINT('',(429.006182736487,931.455647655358,1.15475863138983));
#2690=CARTESIAN_POINT('',(428.900001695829,931.513499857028,0.961756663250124));
#2691=CARTESIAN_POINT('',(428.804242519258,931.658061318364,0.695509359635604));
#2692=CARTESIAN_POINT('',(428.78289723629,931.715776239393,0.610661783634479));
#2693=CARTESIAN_POINT('',(428.76674097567,931.815672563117,0.492443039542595));
#2694=CARTESIAN_POINT('',(428.763999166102,931.851184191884,0.454545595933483));
#2695=CARTESIAN_POINT('',(428.763851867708,931.90757801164,0.400355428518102));
#2696=CARTESIAN_POINT('',(428.764463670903,931.926896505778,0.382734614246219));
#2697=CARTESIAN_POINT('',(428.766372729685,931.956626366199,0.357015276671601));
#2698=CARTESIAN_POINT('',(428.767174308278,931.966661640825,0.348560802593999));
#2699=CARTESIAN_POINT('',(428.768624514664,931.981898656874,0.336062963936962));
#2700=CARTESIAN_POINT('',(428.769149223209,931.987008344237,0.331927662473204));
#2701=CARTESIAN_POINT('',(428.770281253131,931.997288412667,0.323719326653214));
#2702=CARTESIAN_POINT('',(428.770946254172,932.002921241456,0.319286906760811));
#2703=CARTESIAN_POINT('',(428.790447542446,932.159273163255,0.197779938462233));
#2704=CARTESIAN_POINT('',(428.845734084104,932.322235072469,0.117897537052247));
#2705=CARTESIAN_POINT('',(429.029059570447,932.637463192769,0.0191866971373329));
#2706=CARTESIAN_POINT('',(429.157211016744,932.789884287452,6.53043180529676E-07));
#2707=CARTESIAN_POINT('',(429.32151366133,932.928097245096,6.5304318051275E-07));
#2708=B_SPLINE_CURVE_WITH_KNOTS('',3,(#2688,#2689,#2690,#2691,#2692,#2693,#2694,#2695,#2696,
#2697,#2698,#2699,#2700,#2701,#2702,#2703,#2704,#2705,#2706,#2707),.UNSPECIFIED.,.F.,.F.,(4,2,2,
2,2,2,2,2,2,4),(0.,0.25,0.375,0.4375,0.46875,0.484375,0.4921875,0.5,0.75,1.),.UNSPECIFIED.);
#2709=EDGE_CURVE('E223',#2684,#39,#2708,.T.);
#2710=CARTESIAN_POINT('',(429.32151366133,932.928097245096,0.750000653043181));
#2711=CARTESIAN_POINT('',(429.157139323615,932.8589606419,0.750000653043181));
#2712=CARTESIAN_POINT('',(429.029059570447,932.782780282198,0.759593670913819));
#2713=CARTESIAN_POINT('',(428.845734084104,932.625166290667,0.808949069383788));
#2714=CARTESIAN_POINT('',(428.790447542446,932.543685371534,0.848890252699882));
#2715=CARTESIAN_POINT('',(428.770946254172,932.46550944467,0.909643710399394));
#2716=CARTESIAN_POINT('',(428.770281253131,932.462693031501,0.911859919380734));
#2717=CARTESIAN_POINT('',(428.769149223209,932.457552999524,0.915964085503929));
#2718=CARTESIAN_POINT('',(428.768624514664,932.454998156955,0.918031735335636));
#2719=CARTESIAN_POINT('',(428.767174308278,932.447379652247,0.92428065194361));
#2720=CARTESIAN_POINT('',(428.766372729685,932.442362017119,0.928507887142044));
#2721=CARTESIAN_POINT('',(428.764463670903,932.42749709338,0.941367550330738));
#2722=CARTESIAN_POINT('',(428.763851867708,932.417837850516,0.950177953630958));
#2723=CARTESIAN_POINT('',(428.763999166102,932.389640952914,0.97727302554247));
#2724=CARTESIAN_POINT('',(428.76674097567,932.371885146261,0.996221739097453));
#2725=CARTESIAN_POINT('',(428.78289723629,932.321937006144,1.0553310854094));
#2726=CARTESIAN_POINT('',(428.804242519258,932.293079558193,1.09775485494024));
#2727=CARTESIAN_POINT('',(428.900001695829,932.220798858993,1.23087844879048));
#2728=CARTESIAN_POINT('',(429.006159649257,932.191874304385,1.32736444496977));
#2729=CARTESIAN_POINT('',(429.154573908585,932.182015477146,1.42344272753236));
#2730=B_SPLINE_CURVE_WITH_KNOTS('',3,(#2710,#2711,#2712,#2713,#2714,#2715,#2716,#2717,#2718,
#2719,#2720,#2721,#2722,#2723,#2724,#2725,#2726,#2727,#2728,#2729),.UNSPECIFIED.,.F.,.F.,(4,2,2,
2,2,2,2,2,2,4),(0.,0.25,0.5,0.5078125,0.515625,0.53125,0.5625,0.625,0.75,1.),.UNSPECIFIED.);
#2731=EDGE_CURVE('E1196',#2686,#30,#2730,.F.);
#2732=ORIENTED_EDGE('',*,*,#2687,.F.);
#2733=ORIENTED_EDGE('',*,*,#2709,.T.);
#2734=ORIENTED_EDGE('',*,*,#40,.F.);
#2735=ORIENTED_EDGE('',*,*,#2731,.F.);
#2736=EDGE_LOOP('',(#2732,#2733,#2734,#2735));
#2737=FACE_BOUND('',#2736,.T.);
#2738=ADVANCED_FACE('F626',(#2737),#2679,.F.);
#2739=CARTESIAN_POINT('',(70.67848633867,932.928097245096,6.5304318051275E-07));
#2740=CARTESIAN_POINT('',(70.8427889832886,932.789884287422,6.53043180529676E-07));
#2741=CARTESIAN_POINT('',(70.9709404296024,932.637463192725,0.0191866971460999));
#2742=CARTESIAN_POINT('',(71.1084345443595,932.401042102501,0.093219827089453));
#2743=CARTESIAN_POINT('',(71.1451718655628,932.321026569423,0.125432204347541));
#2744=CARTESIAN_POINT('',(71.186636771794,932.201935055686,0.186729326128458));
#2745=CARTESIAN_POINT('',(71.1981848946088,932.162401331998,0.20932039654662));
#2746=CARTESIAN_POINT('',(71.2120968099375,932.103761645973,0.246602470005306));
#2747=CARTESIAN_POINT('',(71.2161657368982,932.084325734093,0.259595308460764));
#2748=CARTESIAN_POINT('',(71.2214165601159,932.055394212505,0.279948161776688));
#2749=CARTESIAN_POINT('',(71.2230247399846,932.045787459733,0.2868763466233));
#2750=CARTESIAN_POINT('',(71.2252238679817,932.031440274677,0.297486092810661));
#2751=CARTESIAN_POINT('',(71.2259213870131,932.026668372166,0.301058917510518));
#2752=CARTESIAN_POINT('',(71.2272453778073,932.017146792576,0.308277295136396));
#2753=CARTESIAN_POINT('',(71.227814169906,932.012859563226,0.311563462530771));
#2754=CARTESIAN_POINT('',(71.2492188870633,931.8412468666,0.444930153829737));
#2755=CARTESIAN_POINT('',(71.227677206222,931.706248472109,0.606760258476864));
#2756=CARTESIAN_POINT('',(71.0999983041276,931.513499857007,0.961756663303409));
#2757=CARTESIAN_POINT('',(70.9938172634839,931.455647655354,1.15475863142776));
#2758=CARTESIAN_POINT('',(70.8454260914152,931.435933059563,1.34688538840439));
#2759=CARTESIAN_POINT('',(70.67848633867,932.928097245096,0.750000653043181));
#2760=CARTESIAN_POINT('',(70.8428606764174,932.858960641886,0.750000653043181));
#2761=CARTESIAN_POINT('',(70.9709404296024,932.782780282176,0.759593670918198));
#2762=CARTESIAN_POINT('',(71.1084345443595,932.664569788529,0.796610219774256));
#2763=CARTESIAN_POINT('',(71.1451718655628,932.624562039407,0.812716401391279));
#2764=CARTESIAN_POINT('',(71.186636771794,932.565016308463,0.843364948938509));
#2765=CARTESIAN_POINT('',(71.1981848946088,932.545249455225,0.854660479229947));
#2766=CARTESIAN_POINT('',(71.2120968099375,932.515929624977,0.873301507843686));
#2767=CARTESIAN_POINT('',(71.2161657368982,932.506211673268,0.879797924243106));
#2768=CARTESIAN_POINT('',(71.2214165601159,932.491745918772,0.889974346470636));
#2769=CARTESIAN_POINT('',(71.2230247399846,932.486942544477,0.893438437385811));
#2770=CARTESIAN_POINT('',(71.2252238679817,932.479768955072,0.89874330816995));
#2771=CARTESIAN_POINT('',(71.2259213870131,932.477383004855,0.900529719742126));
#2772=CARTESIAN_POINT('',(71.2272453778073,932.472622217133,0.90413890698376));
#2773=CARTESIAN_POINT('',(71.227814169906,932.470478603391,0.905781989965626));
#2774=CARTESIAN_POINT('',(71.2492188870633,932.384672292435,0.972465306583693));
#2775=CARTESIAN_POINT('',(71.227677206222,932.317173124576,1.05338032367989));
#2776=CARTESIAN_POINT('',(71.0999983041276,932.220798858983,1.23087844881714));
#2777=CARTESIAN_POINT('',(70.9938403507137,932.191874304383,1.32736444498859));
#2778=CARTESIAN_POINT('',(70.8454260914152,932.182015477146,1.42344272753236));
#2779=B_SPLINE_SURFACE_WITH_KNOTS('',1,3,((#2739,#2740,#2741,#2742,#2743,#2744,#2745,#2746,
#2747,#2748,#2749,#2750,#2751,#2752,#2753,#2754,#2755,#2756,#2757,#2758),(#2759,#2760,#2761,
#2762,#2763,#2764,#2765,#2766,#2767,#2768,#2769,#2770,#2771,#2772,#2773,#2774,#2775,#2776,#2777,
#2778)),.UNSPECIFIED.,.F.,.F.,.F.,(2,2),(4,2,2,2,2,2,2,2,2,4),(0.,1.),(0.,0.25,0.375,0.4375,
0.46875,0.484375,0.4921875,0.5,0.75,1.),.UNSPECIFIED.);
#2780=CARTESIAN_POINT('',(70.67848633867,932.928097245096,6.5304318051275E-07));
#2781=CARTESIAN_POINT('',(70.8427889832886,932.789884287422,6.53043180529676E-07));
#2782=CARTESIAN_POINT('',(70.9709404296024,932.637463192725,0.0191866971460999));
#2783=CARTESIAN_POINT('',(71.1084345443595,932.401042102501,0.093219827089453));
#2784=CARTESIAN_POINT('',(71.1451718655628,932.321026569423,0.125432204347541));
#2785=CARTESIAN_POINT('',(71.186636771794,932.201935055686,0.186729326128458));
#2786=CARTESIAN_POINT('',(71.1981848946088,932.162401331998,0.20932039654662));
#2787=CARTESIAN_POINT('',(71.2120968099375,932.103761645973,0.246602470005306));
#2788=CARTESIAN_POINT('',(71.2161657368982,932.084325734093,0.259595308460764));
#2789=CARTESIAN_POINT('',(71.2214165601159,932.055394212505,0.279948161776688));
#2790=CARTESIAN_POINT('',(71.2230247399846,932.045787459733,0.2868763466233));
#2791=CARTESIAN_POINT('',(71.2252238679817,932.031440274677,0.297486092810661));
#2792=CARTESIAN_POINT('',(71.2259213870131,932.026668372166,0.301058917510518));
#2793=CARTESIAN_POINT('',(71.2272453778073,932.017146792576,0.308277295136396));
#2794=CARTESIAN_POINT('',(71.227814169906,932.012859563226,0.311563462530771));
#2795=CARTESIAN_POINT('',(71.2492188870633,931.8412468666,0.444930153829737));
#2796=CARTESIAN_POINT('',(71.227677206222,931.706248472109,0.606760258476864));
#2797=CARTESIAN_POINT('',(71.0999983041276,931.513499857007,0.961756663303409));
#2798=CARTESIAN_POINT('',(70.9938172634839,931.455647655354,1.15475863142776));
#2799=CARTESIAN_POINT('',(70.8454260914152,931.435933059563,1.34688538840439));
#2800=B_SPLINE_CURVE_WITH_KNOTS('',3,(#2780,#2781,#2782,#2783,#2784,#2785,#2786,#2787,#2788,
#2789,#2790,#2791,#2792,#2793,#2794,#2795,#2796,#2797,#2798,#2799),.UNSPECIFIED.,.F.,.F.,(4,2,2,
2,2,2,2,2,2,4),(0.,0.25,0.375,0.4375,0.46875,0.484375,0.4921875,0.5,0.75,1.),.UNSPECIFIED.);
#2801=CARTESIAN_POINT('',(70.8454263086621,931.435933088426,1.3468851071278));
#2802=VERTEX_POINT('',#2801);
#2803=EDGE_CURVE('E2534',#105,#2802,#2800,.T.);
#2804=CARTESIAN_POINT('',(70.8454260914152,931.435933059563,1.34688538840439));
#2805=CARTESIAN_POINT('',(70.8454260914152,932.182015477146,1.42344272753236));
#2806=B_SPLINE_CURVE_WITH_KNOTS('',1,(#2804,#2805),.UNSPECIFIED.,.F.,.F.,(2,2),(0.,1.),.UNSPECIFIED.);
#2807=CARTESIAN_POINT('',(70.8454260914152,932.182015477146,1.42344272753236));
#2808=VERTEX_POINT('',#2807);
#2809=EDGE_CURVE('E601',#2802,#2808,#2806,.T.);
#2810=CARTESIAN_POINT('',(70.8454260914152,932.182015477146,1.42344272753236));
#2811=CARTESIAN_POINT('',(70.9938403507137,932.191874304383,1.32736444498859));
#2812=CARTESIAN_POINT('',(71.0999983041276,932.220798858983,1.23087844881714));
#2813=CARTESIAN_POINT('',(71.227677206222,932.317173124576,1.05338032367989));
#2814=CARTESIAN_POINT('',(71.2492188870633,932.384672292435,0.972465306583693));
#2815=CARTESIAN_POINT('',(71.227814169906,932.470478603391,0.905781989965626));
#2816=CARTESIAN_POINT('',(71.2272453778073,932.472622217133,0.90413890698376));
#2817=CARTESIAN_POINT('',(71.2259213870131,932.477383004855,0.900529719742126));
#2818=CARTESIAN_POINT('',(71.2252238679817,932.479768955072,0.89874330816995));
#2819=CARTESIAN_POINT('',(71.2230247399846,932.486942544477,0.893438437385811));
#2820=CARTESIAN_POINT('',(71.2214165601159,932.491745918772,0.889974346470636));
#2821=CARTESIAN_POINT('',(71.2161657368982,932.506211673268,0.879797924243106));
#2822=CARTESIAN_POINT('',(71.2120968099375,932.515929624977,0.873301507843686));
#2823=CARTESIAN_POINT('',(71.1981848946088,932.545249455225,0.854660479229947));
#2824=CARTESIAN_POINT('',(71.186636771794,932.565016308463,0.843364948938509));
#2825=CARTESIAN_POINT('',(71.1451718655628,932.624562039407,0.812716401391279));
#2826=CARTESIAN_POINT('',(71.1084345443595,932.664569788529,0.796610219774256));
#2827=CARTESIAN_POINT('',(70.9709404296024,932.782780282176,0.759593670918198));
#2828=CARTESIAN_POINT('',(70.8428606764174,932.858960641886,0.750000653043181));
#2829=CARTESIAN_POINT('',(70.67848633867,932.928097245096,0.750000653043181));
#2830=B_SPLINE_CURVE_WITH_KNOTS('',3,(#2810,#2811,#2812,#2813,#2814,#2815,#2816,#2817,#2818,
#2819,#2820,#2821,#2822,#2823,#2824,#2825,#2826,#2827,#2828,#2829),.UNSPECIFIED.,.F.,.F.,(4,2,2,
2,2,2,2,2,2,4),(0.,0.25,0.5,0.5078125,0.515625,0.53125,0.5625,0.625,0.75,1.),.UNSPECIFIED.);
#2831=EDGE_CURVE('E2525',#218,#2808,#2830,.F.);
#2832=ORIENTED_EDGE('',*,*,#2631,.T.);
#2833=ORIENTED_EDGE('',*,*,#2803,.T.);
#2834=ORIENTED_EDGE('',*,*,#2809,.T.);
#2835=ORIENTED_EDGE('',*,*,#2831,.F.);
#2836=EDGE_LOOP('',(#2832,#2833,#2834,#2835));
#2837=FACE_BOUND('',#2836,.T.);
#2838=ADVANCED_FACE('F1235',(#2837),#2779,.F.);
#2839=CARTESIAN_POINT('',(70.8454260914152,931.435933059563,1.34688538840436));
#2840=CARTESIAN_POINT('',(70.8965534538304,931.430714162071,1.39774566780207));
#2841=CARTESIAN_POINT('',(70.9476805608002,931.42809789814,1.44887265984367));
#2842=CARTESIAN_POINT('',(70.9988079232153,931.42809789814,1.49999999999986));
#2843=CARTESIAN_POINT('',(70.8454260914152,932.182015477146,1.42344272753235));
#2844=CARTESIAN_POINT('',(70.8965534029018,932.179406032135,1.44887283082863));
#2845=CARTESIAN_POINT('',(70.9476806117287,932.17809789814,1.47443636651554));
#2846=CARTESIAN_POINT('',(70.9988079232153,932.17809789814,1.49999999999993));
#2847=B_SPLINE_SURFACE_WITH_KNOTS('',1,3,((#2839,#2840,#2841,#2842),(#2843,#2844,#2845,#2846)),
.UNSPECIFIED.,.F.,.F.,.F.,(2,2),(4,4),(0.,1.),(0.,1.),.UNSPECIFIED.);
#2848=CARTESIAN_POINT('',(70.8454260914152,931.435933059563,1.34688538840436));
#2849=CARTESIAN_POINT('',(70.8965534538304,931.430714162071,1.39774566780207));
#2850=CARTESIAN_POINT('',(70.9476805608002,931.42809789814,1.44887265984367));
#2851=CARTESIAN_POINT('',(70.9988079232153,931.42809789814,1.49999999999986));
#2852=B_SPLINE_CURVE_WITH_KNOTS('',3,(#2848,#2849,#2850,#2851),.UNSPECIFIED.,.F.,.F.,(4,4),(0.,
1.),.UNSPECIFIED.);
#2853=CARTESIAN_POINT('',(70.9988079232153,931.428097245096,1.50000000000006));
#2854=VERTEX_POINT('',#2853);
#2855=EDGE_CURVE('E2533',#2802,#2854,#2852,.T.);
#2856=CARTESIAN_POINT('',(70.9988079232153,931.42809789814,1.49999999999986));
#2857=CARTESIAN_POINT('',(70.9988079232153,932.17809789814,1.49999999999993));
#2858=B_SPLINE_CURVE_WITH_KNOTS('',1,(#2856,#2857),.UNSPECIFIED.,.F.,.F.,(2,2),(0.,1.),.UNSPECIFIED.);
#2859=CARTESIAN_POINT('',(70.9988079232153,932.178097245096,1.50000000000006));
#2860=VERTEX_POINT('',#2859);
#2861=EDGE_CURVE('E1145',#2854,#2860,#2858,.T.);
#2862=CARTESIAN_POINT('',(70.9988079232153,932.17809789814,1.49999999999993));
#2863=CARTESIAN_POINT('',(70.9476806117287,932.17809789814,1.47443636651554));
#2864=CARTESIAN_POINT('',(70.8965534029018,932.179406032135,1.44887283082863));
#2865=CARTESIAN_POINT('',(70.8454260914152,932.182015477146,1.42344272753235));
#2866=B_SPLINE_CURVE_WITH_KNOTS('',3,(#2862,#2863,#2864,#2865),.UNSPECIFIED.,.F.,.F.,(4,4),(0.,
1.),.UNSPECIFIED.);
#2867=EDGE_CURVE('E591',#2808,#2860,#2866,.F.);
#2868=ORIENTED_EDGE('',*,*,#2809,.F.);
#2869=ORIENTED_EDGE('',*,*,#2855,.T.);
#2870=ORIENTED_EDGE('',*,*,#2861,.T.);
#2871=ORIENTED_EDGE('',*,*,#2867,.F.);
#2872=EDGE_LOOP('',(#2868,#2869,#2870,#2871));
#2873=FACE_BOUND('',#2872,.T.);
#2874=ADVANCED_FACE('F624',(#2873),#2847,.F.);
#2875=CARTESIAN_POINT('',(429.001192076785,931.42809789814,1.49999999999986));
#2876=CARTESIAN_POINT('',(429.0523194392,931.42809789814,1.44887265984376));
#2877=CARTESIAN_POINT('',(429.10344654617,931.430714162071,1.3977456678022));
#2878=CARTESIAN_POINT('',(429.154573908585,931.435933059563,1.3468853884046));
#2879=CARTESIAN_POINT('',(429.001192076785,932.17809789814,1.49999999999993));
#2880=CARTESIAN_POINT('',(429.052319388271,932.17809789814,1.47443636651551));
#2881=CARTESIAN_POINT('',(429.103446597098,932.179406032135,1.44887283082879));
#2882=CARTESIAN_POINT('',(429.154573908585,932.182015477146,1.42344272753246));
#2883=B_SPLINE_SURFACE_WITH_KNOTS('',1,3,((#2875,#2876,#2877,#2878),(#2879,#2880,#2881,#2882)),
.UNSPECIFIED.,.F.,.F.,.F.,(2,2),(4,4),(0.,1.),(0.,1.),.UNSPECIFIED.);
#2884=CARTESIAN_POINT('',(429.001192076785,931.42809789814,1.49999999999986));
#2885=CARTESIAN_POINT('',(429.0523194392,931.42809789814,1.44887265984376));
#2886=CARTESIAN_POINT('',(429.10344654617,931.430714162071,1.3977456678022));
#2887=CARTESIAN_POINT('',(429.154573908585,931.435933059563,1.3468853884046));
#2888=B_SPLINE_CURVE_WITH_KNOTS('',3,(#2884,#2885,#2886,#2887),.UNSPECIFIED.,.F.,.F.,(4,4),(0.,
1.),.UNSPECIFIED.);
#2889=CARTESIAN_POINT('',(429.001192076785,931.428097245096,1.50000000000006));
#2890=VERTEX_POINT('',#2889);
#2891=EDGE_CURVE('E2531',#2890,#2684,#2888,.T.);
#2892=CARTESIAN_POINT('',(429.154573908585,932.182015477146,1.42344272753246));
#2893=CARTESIAN_POINT('',(429.103446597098,932.179406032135,1.44887283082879));
#2894=CARTESIAN_POINT('',(429.052319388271,932.17809789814,1.47443636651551));
#2895=CARTESIAN_POINT('',(429.001192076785,932.17809789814,1.49999999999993));
#2896=B_SPLINE_CURVE_WITH_KNOTS('',3,(#2892,#2893,#2894,#2895),.UNSPECIFIED.,.F.,.F.,(4,4),(0.,
1.),.UNSPECIFIED.);
#2897=CARTESIAN_POINT('',(429.001192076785,932.17809789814,1.49999999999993));
#2898=VERTEX_POINT('',#2897);
#2899=EDGE_CURVE('E587',#2898,#2686,#2896,.F.);
#2900=CARTESIAN_POINT('',(429.001192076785,932.17809789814,1.49999999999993));
#2901=CARTESIAN_POINT('',(429.001192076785,931.42809789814,1.49999999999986));
#2902=B_SPLINE_CURVE_WITH_KNOTS('',1,(#2900,#2901),.UNSPECIFIED.,.F.,.F.,(2,2),(0.,1.),.UNSPECIFIED.);
#2903=EDGE_CURVE('E564',#2890,#2898,#2902,.F.);
#2904=ORIENTED_EDGE('',*,*,#2891,.T.);
#2905=ORIENTED_EDGE('',*,*,#2687,.T.);
#2906=ORIENTED_EDGE('',*,*,#2899,.F.);
#2907=ORIENTED_EDGE('',*,*,#2903,.F.);
#2908=EDGE_LOOP('',(#2904,#2905,#2906,#2907));
#2909=FACE_BOUND('',#2908,.T.);
#2910=ADVANCED_FACE('F596',(#2909),#2883,.F.);
#2911=CARTESIAN_POINT('',(-108.651551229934,932.928097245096,1.5));
#2912=DIRECTION('',(1.,0.,0.));
#2913=DIRECTION('',(0.,0.,-1.));
#2914=AXIS2_PLACEMENT_3D('',#2911,#2912,#2913);
#2915=CYLINDRICAL_SURFACE('',#2914,0.749999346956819);
#2916=DIRECTION('',(-1.,0.,0.));
#2917=VECTOR('',#2916,1.);
#2918=CARTESIAN_POINT('',(0.,932.178097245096,1.50000000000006));
#2919=LINE('',#2918,#2917);
#2920=EDGE_CURVE('E579',#2898,#2860,#2919,.T.);
#2921=ORIENTED_EDGE('',*,*,#2920,.F.);
#2922=ORIENTED_EDGE('',*,*,#2899,.T.);
#2923=ORIENTED_EDGE('',*,*,#2731,.T.);
#2924=ORIENTED_EDGE('',*,*,#219,.T.);
#2925=ORIENTED_EDGE('',*,*,#2831,.T.);
#2926=ORIENTED_EDGE('',*,*,#2867,.T.);
#2927=EDGE_LOOP('',(#2921,#2922,#2923,#2924,#2925,#2926));
#2928=FACE_BOUND('',#2927,.T.);
#2929=ADVANCED_FACE('F585',(#2928),#2915,.F.);
#2930=CARTESIAN_POINT('',(-108.651551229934,932.928097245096,1.5));
#2931=DIRECTION('',(1.,0.,0.));
#2932=DIRECTION('',(0.,0.,-1.));
#2933=AXIS2_PLACEMENT_3D('',#2930,#2931,#2932);
#2934=CYLINDRICAL_SURFACE('',#2933,1.49999934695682);
#2935=DIRECTION('',(-1.,0.,0.));
#2936=VECTOR('',#2935,1.);
#2937=CARTESIAN_POINT('',(0.,931.428097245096,1.50000000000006));
#2938=LINE('',#2937,#2936);
#2939=EDGE_CURVE('E562',#2890,#2854,#2938,.T.);
#2940=ORIENTED_EDGE('',*,*,#2939,.T.);
#2941=ORIENTED_EDGE('',*,*,#2855,.F.);
#2942=ORIENTED_EDGE('',*,*,#2803,.F.);
#2943=ORIENTED_EDGE('',*,*,#106,.F.);
#2944=ORIENTED_EDGE('',*,*,#2709,.F.);
#2945=ORIENTED_EDGE('',*,*,#2891,.F.);
#2946=EDGE_LOOP('',(#2940,#2941,#2942,#2943,#2944,#2945));
#2947=FACE_BOUND('',#2946,.T.);
#2948=ADVANCED_FACE('F625',(#2947),#2934,.T.);
#2949=CARTESIAN_POINT('',(-618.726733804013,971.429097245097,10.5719027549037));
#2950=DIRECTION('',(0.,0.,1.));
#2951=DIRECTION('',(0.,-1.,0.));
#2952=AXIS2_PLACEMENT_3D('',#2949,#2950,#2951);
#2953=PLANE('',#2952);
#2954=DIRECTION('',(0.,-1.,0.));
#2955=VECTOR('',#2954,1.);
#2956=CARTESIAN_POINT('',(80.0707106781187,971.429097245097,10.5719027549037));
#2957=LINE('',#2956,#2955);
#2958=CARTESIAN_POINT('',(80.0707106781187,932.178097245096,10.5719027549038));
#2959=VERTEX_POINT('',#2958);
#2960=CARTESIAN_POINT('',(80.0707106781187,931.428097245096,10.5719027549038));
#2961=VERTEX_POINT('',#2960);
#2962=EDGE_CURVE('E554',#2959,#2961,#2957,.T.);
#2963=ORIENTED_EDGE('',*,*,#2962,.T.);
#2964=DIRECTION('',(-1.,0.,0.));
#2965=VECTOR('',#2964,1.);
#2966=CARTESIAN_POINT('',(-618.726733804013,931.428097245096,10.5719027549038));
#2967=LINE('',#2966,#2965);
#2968=CARTESIAN_POINT('',(419.929289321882,931.428097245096,10.5719027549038));
#2969=VERTEX_POINT('',#2968);
#2970=EDGE_CURVE('E551',#2969,#2961,#2967,.T.);
#2971=ORIENTED_EDGE('',*,*,#2970,.F.);
#2972=DIRECTION('',(0.,-1.,0.));
#2973=VECTOR('',#2972,1.);
#2974=CARTESIAN_POINT('',(419.929289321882,971.429097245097,10.5719027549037));
#2975=LINE('',#2974,#2973);
#2976=CARTESIAN_POINT('',(419.929289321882,932.178097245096,10.5719027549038));
#2977=VERTEX_POINT('',#2976);
#2978=EDGE_CURVE('E538',#2977,#2969,#2975,.T.);
#2979=ORIENTED_EDGE('',*,*,#2978,.F.);
#2980=DIRECTION('',(1.,0.,0.));
#2981=VECTOR('',#2980,1.);
#2982=CARTESIAN_POINT('',(-618.726733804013,932.178097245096,10.5719027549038));
#2983=LINE('',#2982,#2981);
#2984=EDGE_CURVE('E558',#2959,#2977,#2983,.T.);
#2985=ORIENTED_EDGE('',*,*,#2984,.F.);
#2986=EDGE_LOOP('',(#2963,#2971,#2979,#2985));
#2987=FACE_BOUND('',#2986,.T.);
#2988=ADVANCED_FACE('F552',(#2987),#2953,.T.);
#2989=CARTESIAN_POINT('',(0.,932.178097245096,-67.928097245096));
#2990=DIRECTION('',(0.,-1.,0.));
#2991=DIRECTION('',(-1.,0.,0.));
#2992=AXIS2_PLACEMENT_3D('',#2989,#2990,#2991);
#2993=PLANE('',#2992);
#2994=DIRECTION('',(-0.707106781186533,0.,0.707106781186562));
#2995=VECTOR('',#2994,1.);
#2996=CARTESIAN_POINT('',(-310.148722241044,932.178097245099,740.64991431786));
#2997=LINE('',#2996,#2995);
#2998=EDGE_CURVE('E545',#2898,#2977,#2997,.T.);
#2999=ORIENTED_EDGE('',*,*,#2998,.F.);
#3000=ORIENTED_EDGE('',*,*,#2920,.T.);
#3001=DIRECTION('',(0.707106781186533,0.,0.707106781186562));
#3002=VECTOR('',#3001,1.);
#3003=CARTESIAN_POINT('',(-58.5780115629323,932.178097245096,-128.076819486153));
#3004=LINE('',#3003,#3002);
#3005=EDGE_CURVE('E593',#2860,#2959,#3004,.T.);
#3006=ORIENTED_EDGE('',*,*,#3005,.T.);
#3007=ORIENTED_EDGE('',*,*,#2984,.T.);
#3008=EDGE_LOOP('',(#2999,#3000,#3006,#3007));
#3009=FACE_BOUND('',#3008,.T.);
#3010=ADVANCED_FACE('F578',(#3009),#2993,.F.);
#3011=CARTESIAN_POINT('',(-58.5780115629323,971.429097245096,-128.076819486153));
#3012=DIRECTION('',(-0.707106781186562,0.,0.707106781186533));
#3013=DIRECTION('',(0.707106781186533,0.,0.707106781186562));
#3014=AXIS2_PLACEMENT_3D('',#3011,#3012,#3013);
#3015=PLANE('',#3014);
#3016=ORIENTED_EDGE('',*,*,#2861,.F.);
#3017=DIRECTION('',(-0.707106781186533,0.,-0.707106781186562));
#3018=VECTOR('',#3017,1.);
#3019=CARTESIAN_POINT('',(-58.5780115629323,931.428097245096,-128.076819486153));
#3020=LINE('',#3019,#3018);
#3021=EDGE_CURVE('E557',#2961,#2854,#3020,.T.);
#3022=ORIENTED_EDGE('',*,*,#3021,.F.);
#3023=ORIENTED_EDGE('',*,*,#2962,.F.);
#3024=ORIENTED_EDGE('',*,*,#3005,.F.);
#3025=EDGE_LOOP('',(#3016,#3022,#3023,#3024));
#3026=FACE_BOUND('',#3025,.T.);
#3027=ADVANCED_FACE('F1151',(#3026),#3015,.T.);
#3028=CARTESIAN_POINT('',(0.,931.428097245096,-67.928097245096));
#3029=DIRECTION('',(0.,-1.,0.));
#3030=DIRECTION('',(-1.,0.,0.));
#3031=AXIS2_PLACEMENT_3D('',#3028,#3029,#3030);
#3032=PLANE('',#3031);
#3033=ORIENTED_EDGE('',*,*,#2939,.F.);
#3034=DIRECTION('',(0.707106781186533,0.,-0.707106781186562));
#3035=VECTOR('',#3034,1.);
#3036=CARTESIAN_POINT('',(-310.148722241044,931.428097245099,740.64991431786));
#3037=LINE('',#3036,#3035);
#3038=EDGE_CURVE('E542',#2969,#2890,#3037,.T.);
#3039=ORIENTED_EDGE('',*,*,#3038,.F.);
#3040=ORIENTED_EDGE('',*,*,#2970,.T.);
#3041=ORIENTED_EDGE('',*,*,#3021,.T.);
#3042=EDGE_LOOP('',(#3033,#3039,#3040,#3041));
#3043=FACE_BOUND('',#3042,.T.);
#3044=ADVANCED_FACE('F560',(#3043),#3032,.T.);
#3045=CARTESIAN_POINT('',(-310.148722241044,971.429097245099,740.64991431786));
#3046=DIRECTION('',(-0.707106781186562,0.,-0.707106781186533));
#3047=DIRECTION('',(-0.707106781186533,0.,0.707106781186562));
#3048=AXIS2_PLACEMENT_3D('',#3045,#3046,#3047);
#3049=PLANE('',#3048);
#3050=ORIENTED_EDGE('',*,*,#3038,.T.);
#3051=ORIENTED_EDGE('',*,*,#2903,.T.);
#3052=ORIENTED_EDGE('',*,*,#2998,.T.);
#3053=ORIENTED_EDGE('',*,*,#2978,.T.);
#3054=EDGE_LOOP('',(#3050,#3051,#3052,#3053));
#3055=FACE_BOUND('',#3054,.T.);
#3056=ADVANCED_FACE('F540',(#3055),#3049,.F.);
#3057=CLOSED_SHELL('',(#59,#207,#355,#393,#431,#448,#465,#496,#527,#544,#561,#599,#637,#654,
#671,#702,#733,#750,#767,#800,#833,#850,#867,#898,#929,#946,#963,#996,#1029,#1046,#1063,#1094,
#1125,#1142,#1159,#1171,#1364,#1397,#1414,#1431,#1462,#1493,#1515,#1527,#1539,#1732,#1925,#1942,
#1959,#1990,#2021,#2043,#2055,#2067,#2100,#2293,#2310,#2327,#2358,#2389,#2411,#2423,#2435,#2457,
#2474,#2491,#2508,#2525,#2542,#2559,#2576,#2593,#2610,#2622,#2638,#2738,#2838,#2874,#2910,#2929,
#2948,#2988,#3010,#3027,#3044,#3056));
#3058=MANIFOLD_SOLID_BREP('B2',#3057);
#3059=ADVANCED_BREP_SHAPE_REPRESENTATION('',(#18,#3058),#14);
#3060=SHAPE_DEFINITION_REPRESENTATION(#9,#3059);
ENDSEC;
END-ISO-10303-21;
